VERSION 5.7 ;
BUSBITCHARS "[]" ;
DIVIDERCHAR "/" ;

PROPERTYDEFINITIONS
  MACRO deviceLevel STRING ;
  MACRO CatenaDesignType STRING ;
  MACRO oaTaper STRING ;
END PROPERTYDEFINITIONS

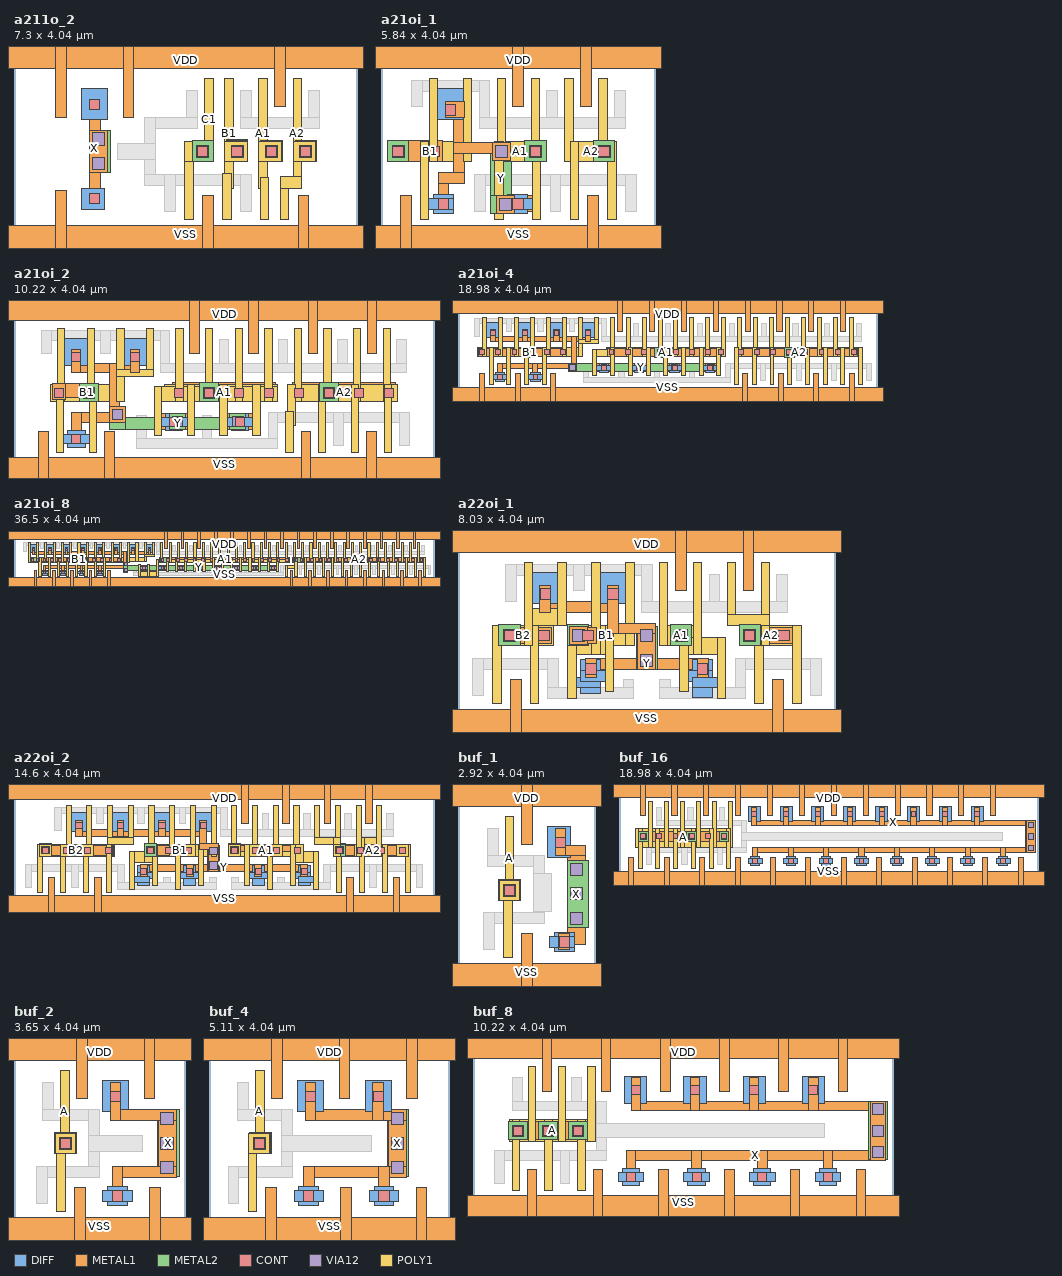
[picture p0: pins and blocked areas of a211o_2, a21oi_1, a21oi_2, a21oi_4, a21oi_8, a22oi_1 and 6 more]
MACRO a211o_2
  CLASS CORE ;
  ORIGIN 0 -0.35 ;
  FOREIGN a211o_2 0 0.35 ;
  SIZE 7.3 BY 4.04 ;
  SYMMETRY X Y ;
  SITE core ;
  PIN X
    DIRECTION INOUT ;
    USE SIGNAL ;
    ANTENNAPARTIALCUTAREA 0.1352 LAYER VIA12 ;
    ANTENNADIFFAREA 0.5676 LAYER METAL2 ;
    ANTENNADIFFAREA 0.5676 LAYER METAL1 ;
    PORT
      LAYER DIFF ;
        RECT 1.445 2.95 1.985 3.61 ;
        RECT 1.445 1.05 1.925 1.49 ;
      LAYER METAL1 ;
        RECT 1.6 1.83 1.98 2.73 ;
        RECT 1.6 1.09 1.83 3.57 ;
      LAYER METAL2 ;
        RECT 1.6 1.83 2.05 2.73 ;
      LAYER CONT ;
        RECT 1.605 3.17 1.825 3.39 ;
        RECT 1.605 1.16 1.825 1.38 ;
      LAYER VIA12 ;
        RECT 1.66 2.41 1.92 2.67 ;
        RECT 1.66 1.89 1.92 2.15 ;
    END
  END X
  PIN VSS
    DIRECTION INOUT ;
    USE GROUND ;
    PORT
      LAYER METAL1 ;
        RECT -0.57 0 7.87 0.7 ;
        RECT 6.04 0 6.27 1.33 ;
        RECT 4.01 0 4.24 1.33 ;
        RECT 0.88 0 1.11 1.45 ;
    END
  END VSS
  PIN A2
    DIRECTION INOUT ;
    USE SIGNAL ;
    ANTENNAPARTIALCUTAREA 0.0676 LAYER VIA12 ;
    ANTENNAMODEL OXIDE1 ;
      ANTENNAGATEAREA 0.1584 LAYER METAL2 ;
      ANTENNAGATEAREA 0.1584 LAYER METAL1 ;
      ANTENNAMAXAREACAR 1.278409 LAYER METAL2 ;
      ANTENNAMAXCUTCAR 0.426768 LAYER VIA12 ;
    PORT
      LAYER POLY1 ;
        RECT 5.935 2.07 6.415 2.49 ;
        RECT 5.935 1.49 6.115 3.83 ;
        RECT 5.665 1.49 6.115 1.74 ;
        RECT 5.665 0.83 5.845 1.74 ;
      LAYER METAL1 ;
        RECT 5.98 2.055 6.43 2.505 ;
      LAYER METAL2 ;
        RECT 5.98 2.055 6.43 2.505 ;
      LAYER CONT ;
        RECT 6.095 2.17 6.315 2.39 ;
      LAYER VIA12 ;
        RECT 6.075 2.15 6.335 2.41 ;
    END
  END A2
  PIN VDD
    DIRECTION INOUT ;
    USE POWER ;
    PORT
      LAYER METAL1 ;
        RECT -0.57 4.04 7.87 4.74 ;
        RECT 5.54 3.23 5.77 4.74 ;
        RECT 2.32 2.99 2.55 4.74 ;
        RECT 0.88 2.99 1.11 4.74 ;
    END
  END VDD
  PIN C1
    DIRECTION INOUT ;
    USE SIGNAL ;
    ANTENNAPARTIALCUTAREA 0.0676 LAYER VIA12 ;
    ANTENNAMODEL OXIDE1 ;
      ANTENNAGATEAREA 0.1584 LAYER METAL2 ;
      ANTENNAGATEAREA 0.1584 LAYER METAL1 ;
      ANTENNAMAXAREACAR 1.278409 LAYER METAL2 ;
      ANTENNAMAXCUTCAR 0.426768 LAYER VIA12 ;
    PORT
      LAYER POLY1 ;
        RECT 4.055 2.07 4.235 3.83 ;
        RECT 3.635 2.07 4.235 2.49 ;
        RECT 3.635 0.83 3.815 2.49 ;
      LAYER METAL1 ;
        RECT 3.79 2.055 4.24 2.505 ;
      LAYER METAL2 ;
        RECT 3.79 2.055 4.24 2.505 ;
      LAYER CONT ;
        RECT 3.905 2.17 4.125 2.39 ;
      LAYER VIA12 ;
        RECT 3.885 2.15 4.145 2.41 ;
    END
  END C1
  PIN B1
    DIRECTION INOUT ;
    USE SIGNAL ;
    ANTENNAPARTIALCUTAREA 0.0676 LAYER VIA12 ;
    ANTENNAMODEL OXIDE1 ;
      ANTENNAGATEAREA 0.1584 LAYER METAL2 ;
      ANTENNAGATEAREA 0.1584 LAYER METAL1 ;
      ANTENNAMAXAREACAR 1.278409 LAYER METAL2 ;
      ANTENNAMAXCUTCAR 0.426768 LAYER VIA12 ;
    PORT
      LAYER POLY1 ;
        RECT 4.485 2.07 4.955 2.49 ;
        RECT 4.485 1.49 4.665 3.83 ;
        RECT 4.435 0.83 4.615 1.815 ;
      LAYER METAL1 ;
        RECT 4.52 2.055 4.97 2.505 ;
      LAYER METAL2 ;
        RECT 4.52 2.055 4.97 2.52 ;
      LAYER CONT ;
        RECT 4.635 2.17 4.855 2.39 ;
      LAYER VIA12 ;
        RECT 4.615 2.15 4.875 2.41 ;
    END
  END B1
  PIN A1
    DIRECTION INOUT ;
    USE SIGNAL ;
    ANTENNAPARTIALCUTAREA 0.0676 LAYER VIA12 ;
    ANTENNAMODEL OXIDE1 ;
      ANTENNAGATEAREA 0.1584 LAYER METAL2 ;
      ANTENNAGATEAREA 0.1584 LAYER METAL1 ;
      ANTENNAMAXAREACAR 1.278409 LAYER METAL2 ;
      ANTENNAMAXCUTCAR 0.426768 LAYER VIA12 ;
    PORT
      LAYER POLY1 ;
        RECT 5.205 2.07 5.685 2.49 ;
        RECT 5.235 0.83 5.415 1.73 ;
        RECT 5.205 1.49 5.385 3.83 ;
      LAYER METAL1 ;
        RECT 5.25 2.055 5.7 2.505 ;
      LAYER METAL2 ;
        RECT 5.25 2.055 5.7 2.505 ;
      LAYER CONT ;
        RECT 5.365 2.17 5.585 2.39 ;
      LAYER VIA12 ;
        RECT 5.345 2.15 5.605 2.41 ;
    END
  END A1
  OBS
    LAYER METAL1 ;
      RECT 6.27 2.77 6.5 3.57 ;
      RECT 4.82 2.77 5.05 3.57 ;
      RECT 4.82 2.77 6.5 3 ;
      RECT 3.67 2.77 3.9 3.57 ;
      RECT 2.78 2.77 3.9 3 ;
      RECT 2.78 1.56 3.01 3 ;
      RECT 2.21 2.11 3.01 2.45 ;
      RECT 2.78 1.56 5.04 1.79 ;
      RECT 4.81 0.99 5.04 1.79 ;
      RECT 3.21 0.99 3.44 1.79 ;
  END
END a211o_2

MACRO a21oi_1
  CLASS CORE ;
  ORIGIN 0 -0.35 ;
  FOREIGN a21oi_1 0 0.35 ;
  SIZE 5.84 BY 4.04 ;
  SYMMETRY X Y ;
  SITE core ;
  PIN Y
    DIRECTION INOUT ;
    USE SIGNAL ;
    ANTENNAPARTIALCUTAREA 0.0676 LAYER VIA12 ;
    ANTENNADIFFAREA 0.7752 LAYER METAL2 ;
    ANTENNADIFFAREA 0.2204 LAYER METAL1 ;
    PORT
      LAYER DIFF ;
        RECT 2.6 1.05 3.22 1.27 ;
        RECT 2.7 0.95 3.12 1.37 ;
        RECT 1.21 2.95 1.75 3.61 ;
        RECT 1.12 0.95 1.54 1.37 ;
        RECT 1.02 1.05 1.54 1.27 ;
      LAYER METAL1 ;
        RECT 2.455 0.99 3.365 1.33 ;
        RECT 2.455 0.95 2.835 1.33 ;
        RECT 1.535 2.24 2.745 2.47 ;
        RECT 2.365 2.09 2.745 2.47 ;
        RECT 1.365 2.99 1.765 3.33 ;
        RECT 1.535 1.595 1.765 3.33 ;
        RECT 1.215 1.595 1.765 1.825 ;
        RECT 1.215 0.99 1.445 1.825 ;
      LAYER METAL2 ;
        RECT 2.33 0.95 2.835 1.33 ;
        RECT 2.33 0.95 2.78 2.47 ;
      LAYER CONT ;
        RECT 1.22 1.05 1.44 1.27 ;
        RECT 1.37 3.05 1.59 3.27 ;
        RECT 2.8 1.05 3.02 1.27 ;
      LAYER VIA12 ;
        RECT 2.425 2.15 2.685 2.41 ;
        RECT 2.515 1.01 2.775 1.27 ;
    END
  END Y
  PIN VSS
    DIRECTION INOUT ;
    USE GROUND ;
    PORT
      LAYER METAL1 ;
        RECT -0.57 0 6.41 0.7 ;
        RECT 4.395 0 4.625 1.33 ;
        RECT 0.415 0 0.645 1.33 ;
    END
  END VSS
  PIN A1
    DIRECTION INOUT ;
    USE SIGNAL ;
    ANTENNAPARTIALCUTAREA 0.0676 LAYER VIA12 ;
    ANTENNAMODEL OXIDE1 ;
      ANTENNAGATEAREA 0.3168 LAYER METAL2 ;
      ANTENNAGATEAREA 0.3168 LAYER METAL1 ;
      ANTENNAMAXAREACAR 0.639205 LAYER METAL2 ;
      ANTENNAMAXCUTCAR 0.213384 LAYER VIA12 ;
    PORT
      LAYER POLY1 ;
        RECT 2.42 2.07 3.495 2.49 ;
        RECT 3.22 0.83 3.4 2.49 ;
        RECT 3.19 2.07 3.37 3.83 ;
        RECT 2.47 2.07 2.65 3.83 ;
        RECT 2.42 0.83 2.6 2.49 ;
      LAYER METAL1 ;
        RECT 3.06 2.055 3.51 2.505 ;
      LAYER METAL2 ;
        RECT 3.06 2.055 3.51 2.505 ;
      LAYER CONT ;
        RECT 3.175 2.17 3.395 2.39 ;
      LAYER VIA12 ;
        RECT 3.155 2.15 3.415 2.41 ;
    END
  END A1
  PIN B1
    DIRECTION INOUT ;
    USE SIGNAL ;
    ANTENNAPARTIALCUTAREA 0.0676 LAYER VIA12 ;
    ANTENNAMODEL OXIDE1 ;
      ANTENNAGATEAREA 0.2772 LAYER METAL2 ;
      ANTENNAGATEAREA 0.2772 LAYER METAL1 ;
      ANTENNAMAXAREACAR 1.852543 LAYER METAL2 ;
      ANTENNAMAXCUTCAR 0.243867 LAYER VIA12 ;
    PORT
      LAYER POLY1 ;
        RECT 1.75 2.07 1.93 3.83 ;
        RECT 0.155 2.07 1.93 2.49 ;
        RECT 1.03 2.07 1.21 3.83 ;
        RECT 0.84 0.83 1.02 2.49 ;
      LAYER METAL1 ;
        RECT 0.14 2.07 1.305 2.505 ;
        RECT 0.14 2.055 0.59 2.505 ;
      LAYER METAL2 ;
        RECT 0.14 2.055 0.59 2.505 ;
      LAYER CONT ;
        RECT 0.255 2.17 0.475 2.39 ;
        RECT 1.025 2.17 1.245 2.39 ;
      LAYER VIA12 ;
        RECT 0.235 2.15 0.495 2.41 ;
    END
  END B1
  PIN VDD
    DIRECTION INOUT ;
    USE POWER ;
    PORT
      LAYER METAL1 ;
        RECT -0.57 4.04 6.41 4.74 ;
        RECT 4.245 3.23 4.475 4.74 ;
        RECT 2.805 3.23 3.035 4.74 ;
    END
  END VDD
  PIN A2
    DIRECTION INOUT ;
    USE SIGNAL ;
    ANTENNAPARTIALCUTAREA 0.0676 LAYER VIA12 ;
    ANTENNAMODEL OXIDE1 ;
      ANTENNAGATEAREA 0.3168 LAYER METAL2 ;
      ANTENNAGATEAREA 0.3168 LAYER METAL1 ;
      ANTENNAMAXAREACAR 0.639205 LAYER METAL2 ;
      ANTENNAMAXCUTCAR 0.213384 LAYER VIA12 ;
    PORT
      LAYER POLY1 ;
        RECT 3.91 2.07 5 2.49 ;
        RECT 4.82 0.83 5 2.49 ;
        RECT 4.63 2.07 4.81 3.83 ;
        RECT 4.02 0.83 4.2 2.49 ;
        RECT 3.91 2.07 4.09 3.83 ;
      LAYER METAL1 ;
        RECT 4.52 2.055 4.97 2.505 ;
      LAYER METAL2 ;
        RECT 4.52 2.055 4.97 2.505 ;
      LAYER CONT ;
        RECT 4.635 2.17 4.855 2.39 ;
      LAYER VIA12 ;
        RECT 4.615 2.15 4.875 2.41 ;
    END
  END A2
  OBS
    LAYER METAL1 ;
      RECT 1.995 1.56 5.425 1.79 ;
      RECT 5.195 0.99 5.425 1.79 ;
      RECT 3.595 0.99 3.825 1.79 ;
      RECT 1.995 0.99 2.225 1.79 ;
      RECT 0.645 3.56 2.315 3.79 ;
      RECT 2.085 2.77 2.315 3.79 ;
      RECT 4.965 2.77 5.195 3.57 ;
      RECT 3.525 2.77 3.755 3.57 ;
      RECT 0.645 3.23 0.875 3.79 ;
      RECT 2.085 2.77 5.195 3 ;
  END
END a21oi_1

MACRO a21oi_2
  CLASS CORE ;
  ORIGIN 0 -0.35 ;
  FOREIGN a21oi_2 0 0.35 ;
  SIZE 10.22 BY 4.04 ;
  SYMMETRY X Y ;
  SITE core ;
  PIN Y
    DIRECTION INOUT ;
    USE SIGNAL ;
    ANTENNAPARTIALCUTAREA 0.0676 LAYER VIA12 ;
    ANTENNADIFFAREA 1.374 LAYER METAL2 ;
    ANTENNADIFFAREA 0.2204 LAYER METAL1 ;
    PORT
      LAYER DIFF ;
        RECT 5.19 1.45 5.81 1.67 ;
        RECT 5.29 1.35 5.71 1.77 ;
        RECT 3.59 1.45 4.21 1.67 ;
        RECT 3.69 1.35 4.11 1.77 ;
        RECT 2.68 2.95 3.22 3.61 ;
        RECT 1.21 1.05 1.83 1.27 ;
        RECT 1.31 0.95 1.73 1.37 ;
        RECT 1.24 2.95 1.78 3.61 ;
      LAYER METAL1 ;
        RECT 5.115 1.39 5.885 1.77 ;
        RECT 3.515 1.39 4.285 1.77 ;
        RECT 2.835 2.77 3.065 3.33 ;
        RECT 1.395 2.77 3.065 3 ;
        RECT 2.33 1.56 2.71 1.94 ;
        RECT 2.33 1.56 2.56 3 ;
        RECT 1.405 1.56 2.71 1.79 ;
        RECT 1.405 0.99 1.635 1.79 ;
        RECT 1.395 2.77 1.625 3.33 ;
      LAYER METAL2 ;
        RECT 5.255 1.39 5.635 1.77 ;
        RECT 2.33 1.39 5.635 1.67 ;
        RECT 3.785 1.39 4.165 1.77 ;
        RECT 2.33 1.39 2.71 1.94 ;
      LAYER CONT ;
        RECT 1.4 3.05 1.62 3.27 ;
        RECT 1.41 1.05 1.63 1.27 ;
        RECT 2.84 3.05 3.06 3.27 ;
        RECT 3.79 1.45 4.01 1.67 ;
        RECT 5.39 1.45 5.61 1.67 ;
      LAYER VIA12 ;
        RECT 2.39 1.62 2.65 1.88 ;
        RECT 3.845 1.45 4.105 1.71 ;
        RECT 5.315 1.45 5.575 1.71 ;
    END
  END Y
  PIN VSS
    DIRECTION INOUT ;
    USE GROUND ;
    PORT
      LAYER METAL1 ;
        RECT -0.57 0 10.79 0.7 ;
        RECT 8.585 0 8.815 1.33 ;
        RECT 6.985 0 7.215 1.33 ;
        RECT 2.205 0 2.435 1.33 ;
        RECT 0.605 0 0.835 1.33 ;
    END
  END VSS
  PIN A1
    DIRECTION INOUT ;
    USE SIGNAL ;
    ANTENNAPARTIALCUTAREA 0.0676 LAYER VIA12 ;
    ANTENNAMODEL OXIDE1 ;
      ANTENNAGATEAREA 0.6336 LAYER METAL2 ;
      ANTENNAGATEAREA 0.6336 LAYER METAL1 ;
      ANTENNAMAXAREACAR 1.856771 LAYER METAL2 ;
      ANTENNAMAXCUTCAR 0.106692 LAYER VIA12 ;
    PORT
      LAYER POLY1 ;
        RECT 3.65 2.07 6.415 2.49 ;
        RECT 6.1 2.07 6.28 3.83 ;
        RECT 5.81 1.23 5.99 2.49 ;
        RECT 5.38 2.07 5.56 3.83 ;
        RECT 5.01 1.23 5.19 2.49 ;
        RECT 4.66 2.07 4.84 3.83 ;
        RECT 4.21 1.23 4.39 2.49 ;
        RECT 3.94 2.07 4.12 3.83 ;
        RECT 3.41 2.07 6.415 2.42 ;
        RECT 3.41 1.23 3.59 2.42 ;
      LAYER METAL1 ;
        RECT 3.845 2.055 6.375 2.52 ;
      LAYER METAL2 ;
        RECT 4.52 2.055 4.97 2.52 ;
      LAYER CONT ;
        RECT 3.905 2.17 4.125 2.39 ;
        RECT 4.635 2.17 4.855 2.39 ;
        RECT 5.365 2.17 5.585 2.39 ;
        RECT 6.095 2.17 6.315 2.39 ;
      LAYER VIA12 ;
        RECT 4.615 2.15 4.875 2.41 ;
    END
  END A1
  PIN B1
    DIRECTION INOUT ;
    USE SIGNAL ;
    ANTENNAPARTIALCUTAREA 0.0676 LAYER VIA12 ;
    ANTENNAMODEL OXIDE1 ;
      ANTENNAGATEAREA 0.5544 LAYER METAL2 ;
      ANTENNAGATEAREA 0.5544 LAYER METAL1 ;
      ANTENNAMAXAREACAR 0.820076 LAYER METAL2 ;
      ANTENNAMAXCUTCAR 0.121934 LAYER VIA12 ;
    PORT
      LAYER POLY1 ;
        RECT 3.22 2.67 3.4 3.83 ;
        RECT 2.5 2.67 3.4 2.85 ;
        RECT 2.5 2.07 2.68 3.83 ;
        RECT 0.885 2.07 2.68 2.49 ;
        RECT 1.83 0.83 2.01 2.49 ;
        RECT 1.78 2.07 1.96 3.83 ;
        RECT 1.06 2.07 1.24 3.83 ;
        RECT 1.03 0.83 1.21 2.49 ;
      LAYER METAL1 ;
        RECT 0.925 2.17 2.05 2.51 ;
        RECT 1.6 2.055 2.05 2.51 ;
        RECT 0.925 2.11 1.265 2.51 ;
      LAYER METAL2 ;
        RECT 1.6 2.055 2.05 2.51 ;
      LAYER CONT ;
        RECT 0.985 2.17 1.205 2.39 ;
        RECT 1.715 2.17 1.935 2.39 ;
      LAYER VIA12 ;
        RECT 1.695 2.15 1.955 2.41 ;
    END
  END B1
  PIN A2
    DIRECTION INOUT ;
    USE SIGNAL ;
    ANTENNAPARTIALCUTAREA 0.0676 LAYER VIA12 ;
    ANTENNAMODEL OXIDE1 ;
      ANTENNAGATEAREA 0.6336 LAYER METAL2 ;
      ANTENNAGATEAREA 0.6336 LAYER METAL1 ;
      ANTENNAMAXAREACAR 1.856771 LAYER METAL2 ;
      ANTENNAMAXCUTCAR 0.106692 LAYER VIA12 ;
    PORT
      LAYER POLY1 ;
        RECT 6.665 2.07 9.335 2.49 ;
        RECT 9.01 0.83 9.19 2.49 ;
        RECT 8.98 2.07 9.16 3.83 ;
        RECT 8.26 2.07 8.44 3.83 ;
        RECT 8.21 0.83 8.39 2.49 ;
        RECT 7.54 2.07 7.72 3.83 ;
        RECT 7.41 0.83 7.59 2.49 ;
        RECT 6.82 2.07 7 3.83 ;
        RECT 6.665 1.49 6.845 2.49 ;
        RECT 6.61 0.83 6.79 1.82 ;
      LAYER METAL1 ;
        RECT 6.765 2.055 9.295 2.52 ;
      LAYER METAL2 ;
        RECT 7.44 2.055 7.89 2.52 ;
      LAYER CONT ;
        RECT 6.825 2.17 7.045 2.39 ;
        RECT 7.555 2.17 7.775 2.39 ;
        RECT 8.285 2.17 8.505 2.39 ;
        RECT 9.015 2.17 9.235 2.39 ;
      LAYER VIA12 ;
        RECT 7.535 2.15 7.795 2.41 ;
    END
  END A2
  PIN VDD
    DIRECTION INOUT ;
    USE POWER ;
    PORT
      LAYER METAL1 ;
        RECT -0.57 4.04 10.79 4.74 ;
        RECT 8.595 3.23 8.825 4.74 ;
        RECT 7.155 3.23 7.385 4.74 ;
        RECT 5.715 3.23 5.945 4.74 ;
        RECT 4.275 3.23 4.505 4.74 ;
    END
  END VDD
  OBS
    LAYER METAL1 ;
      RECT 6.185 1.56 9.615 1.79 ;
      RECT 9.385 0.99 9.615 1.79 ;
      RECT 4.585 0.93 4.815 1.73 ;
      RECT 2.985 0.93 3.215 1.73 ;
      RECT 7.785 0.99 8.015 1.79 ;
      RECT 6.185 0.93 6.415 1.79 ;
      RECT 2.985 0.93 6.415 1.16 ;
      RECT 0.675 3.56 3.785 3.79 ;
      RECT 3.555 2.77 3.785 3.79 ;
      RECT 9.315 2.77 9.545 3.57 ;
      RECT 7.875 2.77 8.105 3.57 ;
      RECT 6.435 2.77 6.665 3.57 ;
      RECT 4.995 2.77 5.225 3.57 ;
      RECT 2.115 3.23 2.345 3.79 ;
      RECT 0.675 3.23 0.905 3.79 ;
      RECT 3.555 2.77 9.545 3 ;
  END
END a21oi_2

MACRO a21oi_4
  CLASS CORE ;
  ORIGIN 0 -0.35 ;
  FOREIGN a21oi_4 0 0.35 ;
  SIZE 18.98 BY 4.04 ;
  SYMMETRY X Y ;
  SITE core ;
  PIN Y
    DIRECTION INOUT ;
    USE SIGNAL ;
    ANTENNAPARTIALCUTAREA 0.0676 LAYER VIA12 ;
    ANTENNADIFFAREA 2.748 LAYER METAL2 ;
    ANTENNADIFFAREA 0.2204 LAYER METAL1 ;
    PORT
      LAYER DIFF ;
        RECT 11.08 1.45 11.7 1.67 ;
        RECT 11.18 1.35 11.6 1.77 ;
        RECT 9.48 1.45 10.1 1.67 ;
        RECT 9.58 1.35 10 1.77 ;
        RECT 7.88 1.45 8.5 1.67 ;
        RECT 7.98 1.35 8.4 1.77 ;
        RECT 6.28 1.45 6.9 1.67 ;
        RECT 6.38 1.35 6.8 1.77 ;
        RECT 5.62 2.95 6.16 3.61 ;
        RECT 4.18 2.95 4.72 3.61 ;
        RECT 3.19 1.05 3.81 1.27 ;
        RECT 3.29 0.95 3.71 1.37 ;
        RECT 2.74 2.95 3.28 3.61 ;
        RECT 1.59 1.05 2.21 1.27 ;
        RECT 1.69 0.95 2.11 1.37 ;
        RECT 1.3 2.95 1.84 3.61 ;
      LAYER METAL1 ;
        RECT 11.08 1.39 11.7 1.77 ;
        RECT 9.48 1.39 10.1 1.77 ;
        RECT 7.88 1.39 8.5 1.77 ;
        RECT 6.28 1.39 6.9 1.77 ;
        RECT 5.775 2.77 6.005 3.33 ;
        RECT 1.455 2.77 6.005 3 ;
        RECT 5.145 1.39 5.375 3 ;
        RECT 1.785 1.56 5.375 1.79 ;
        RECT 4.995 1.39 5.375 1.79 ;
        RECT 4.335 2.77 4.565 3.33 ;
        RECT 3.385 0.99 3.615 1.79 ;
        RECT 2.895 2.77 3.125 3.33 ;
        RECT 1.785 0.99 2.015 1.79 ;
        RECT 1.455 2.77 1.685 3.33 ;
      LAYER METAL2 ;
        RECT 4.995 1.39 11.585 1.77 ;
      LAYER CONT ;
        RECT 1.46 3.05 1.68 3.27 ;
        RECT 1.79 1.05 2.01 1.27 ;
        RECT 2.9 3.05 3.12 3.27 ;
        RECT 3.39 1.05 3.61 1.27 ;
        RECT 4.34 3.05 4.56 3.27 ;
        RECT 5.78 3.05 6 3.27 ;
        RECT 6.48 1.45 6.7 1.67 ;
        RECT 8.08 1.45 8.3 1.67 ;
        RECT 9.68 1.45 9.9 1.67 ;
        RECT 11.28 1.45 11.5 1.67 ;
      LAYER VIA12 ;
        RECT 5.055 1.45 5.315 1.71 ;
        RECT 6.465 1.45 6.725 1.71 ;
        RECT 8.065 1.45 8.325 1.71 ;
        RECT 9.665 1.45 9.925 1.71 ;
        RECT 11.265 1.45 11.525 1.71 ;
    END
  END Y
  PIN VSS
    DIRECTION INOUT ;
    USE GROUND ;
    PORT
      LAYER METAL1 ;
        RECT -0.57 0 19.55 0.7 ;
        RECT 17.675 0 17.905 1.33 ;
        RECT 16.075 0 16.305 1.33 ;
        RECT 14.475 0 14.705 1.33 ;
        RECT 12.875 0 13.105 1.33 ;
        RECT 4.185 0 4.415 1.33 ;
        RECT 2.585 0 2.815 1.33 ;
        RECT 0.985 0 1.215 1.33 ;
    END
  END VSS
  PIN A2
    DIRECTION INOUT ;
    USE SIGNAL ;
    ANTENNAPARTIALCUTAREA 0.0676 LAYER VIA12 ;
    ANTENNAMODEL OXIDE1 ;
      ANTENNAGATEAREA 1.2672 LAYER METAL2 ;
      ANTENNAGATEAREA 1.2672 LAYER METAL1 ;
      ANTENNAMAXAREACAR 1.501342 LAYER METAL2 ;
      ANTENNAMAXCUTCAR 0.053346 LAYER VIA12 ;
    PORT
      LAYER POLY1 ;
        RECT 12.5 2.07 18.28 2.49 ;
        RECT 18.1 0.83 18.28 2.49 ;
        RECT 17.68 2.07 17.86 3.83 ;
        RECT 17.3 0.83 17.48 2.49 ;
        RECT 16.96 2.07 17.14 3.83 ;
        RECT 16.5 0.83 16.68 2.49 ;
        RECT 16.24 2.07 16.42 3.83 ;
        RECT 15.7 0.83 15.88 2.49 ;
        RECT 15.52 2.07 15.7 3.83 ;
        RECT 14.9 0.83 15.08 2.49 ;
        RECT 14.8 2.07 14.98 3.83 ;
        RECT 14.1 0.83 14.28 2.49 ;
        RECT 14.08 2.07 14.26 3.83 ;
        RECT 13.36 2.07 13.54 3.83 ;
        RECT 13.3 0.83 13.48 2.49 ;
        RECT 12.64 2.07 12.82 3.83 ;
        RECT 12.5 0.83 12.68 2.49 ;
      LAYER METAL1 ;
        RECT 12.605 2.11 18.055 2.45 ;
        RECT 14.74 2.055 15.19 2.505 ;
      LAYER METAL2 ;
        RECT 14.74 2.055 15.19 2.505 ;
      LAYER CONT ;
        RECT 12.665 2.17 12.885 2.39 ;
        RECT 13.395 2.17 13.615 2.39 ;
        RECT 14.125 2.17 14.345 2.39 ;
        RECT 14.855 2.17 15.075 2.39 ;
        RECT 15.585 2.17 15.805 2.39 ;
        RECT 16.315 2.17 16.535 2.39 ;
        RECT 17.045 2.17 17.265 2.39 ;
        RECT 17.775 2.17 17.995 2.39 ;
      LAYER VIA12 ;
        RECT 14.835 2.15 15.095 2.41 ;
    END
  END A2
  PIN A1
    DIRECTION INOUT ;
    USE SIGNAL ;
    ANTENNAPARTIALCUTAREA 0.0676 LAYER VIA12 ;
    ANTENNAMODEL OXIDE1 ;
      ANTENNAGATEAREA 1.2672 LAYER METAL2 ;
      ANTENNAGATEAREA 1.2672 LAYER METAL1 ;
      ANTENNAMAXAREACAR 1.459754 LAYER METAL2 ;
      ANTENNAMAXCUTCAR 0.053346 LAYER VIA12 ;
    PORT
      LAYER POLY1 ;
        RECT 11.92 2.07 12.1 3.83 ;
        RECT 6.725 2.07 12.1 2.49 ;
        RECT 11.7 1.23 11.88 2.49 ;
        RECT 11.2 2.07 11.38 3.83 ;
        RECT 10.9 1.23 11.08 2.49 ;
        RECT 10.48 2.07 10.66 3.83 ;
        RECT 10.1 1.23 10.28 2.49 ;
        RECT 9.76 2.07 9.94 3.83 ;
        RECT 9.3 1.23 9.48 2.49 ;
        RECT 9.04 2.07 9.22 3.83 ;
        RECT 8.5 1.23 8.68 2.49 ;
        RECT 8.32 2.07 8.5 3.83 ;
        RECT 7.7 1.23 7.88 2.49 ;
        RECT 7.6 2.07 7.78 3.83 ;
        RECT 6.9 1.23 7.08 2.49 ;
        RECT 6.88 2.07 7.06 3.83 ;
        RECT 6.1 2.07 12.1 2.42 ;
        RECT 6.1 1.23 6.28 2.42 ;
      LAYER METAL1 ;
        RECT 6.765 2.11 12.06 2.45 ;
        RECT 8.9 2.055 9.35 2.505 ;
      LAYER METAL2 ;
        RECT 8.9 2.055 9.35 2.505 ;
      LAYER CONT ;
        RECT 6.825 2.17 7.045 2.39 ;
        RECT 7.555 2.17 7.775 2.39 ;
        RECT 8.285 2.17 8.505 2.39 ;
        RECT 9.015 2.17 9.235 2.39 ;
        RECT 9.745 2.17 9.965 2.39 ;
        RECT 10.475 2.17 10.695 2.39 ;
        RECT 11.205 2.17 11.425 2.39 ;
        RECT 11.78 2.17 12 2.39 ;
      LAYER VIA12 ;
        RECT 8.995 2.15 9.255 2.41 ;
    END
  END A1
  PIN B1
    DIRECTION INOUT ;
    USE SIGNAL ;
    ANTENNAPARTIALCUTAREA 0.0676 LAYER VIA12 ;
    ANTENNAMODEL OXIDE1 ;
      ANTENNAGATEAREA 1.1088 LAYER METAL2 ;
      ANTENNAGATEAREA 1.1088 LAYER METAL1 ;
      ANTENNAMAXAREACAR 1.268128 LAYER METAL2 ;
      ANTENNAMAXCUTCAR 0.060967 LAYER VIA12 ;
    PORT
      LAYER POLY1 ;
        RECT 6.16 2.67 6.34 3.83 ;
        RECT 5.44 2.67 6.34 2.85 ;
        RECT 5.44 2.07 5.62 3.83 ;
        RECT 0.885 2.07 5.62 2.49 ;
        RECT 4.72 2.07 4.9 3.83 ;
        RECT 4 2.07 4.18 3.83 ;
        RECT 3.81 0.83 3.99 2.49 ;
        RECT 3.28 2.07 3.46 3.83 ;
        RECT 3.01 0.83 3.19 2.49 ;
        RECT 2.56 2.07 2.74 3.83 ;
        RECT 2.21 0.83 2.39 2.49 ;
        RECT 1.84 2.07 2.02 3.83 ;
        RECT 1.41 0.83 1.59 2.49 ;
        RECT 1.12 2.07 1.3 3.83 ;
      LAYER METAL1 ;
        RECT 0.925 2.11 4.915 2.45 ;
        RECT 3.06 2.055 3.51 2.505 ;
      LAYER METAL2 ;
        RECT 3.06 2.055 3.51 2.505 ;
      LAYER CONT ;
        RECT 0.985 2.17 1.205 2.39 ;
        RECT 1.715 2.17 1.935 2.39 ;
        RECT 2.445 2.17 2.665 2.39 ;
        RECT 3.175 2.17 3.395 2.39 ;
        RECT 3.905 2.17 4.125 2.39 ;
        RECT 4.635 2.17 4.855 2.39 ;
      LAYER VIA12 ;
        RECT 3.155 2.15 3.415 2.41 ;
    END
  END B1
  PIN VDD
    DIRECTION INOUT ;
    USE POWER ;
    PORT
      LAYER METAL1 ;
        RECT -0.57 4.04 19.55 4.74 ;
        RECT 17.295 3.23 17.525 4.74 ;
        RECT 15.855 3.23 16.085 4.74 ;
        RECT 14.415 3.23 14.645 4.74 ;
        RECT 12.975 3.23 13.205 4.74 ;
        RECT 11.535 3.23 11.765 4.74 ;
        RECT 10.095 3.23 10.325 4.74 ;
        RECT 8.655 3.23 8.885 4.74 ;
        RECT 7.215 3.23 7.445 4.74 ;
    END
  END VDD
  OBS
    LAYER METAL1 ;
      RECT 12.075 1.56 18.705 1.79 ;
      RECT 18.475 0.99 18.705 1.79 ;
      RECT 10.475 0.93 10.705 1.73 ;
      RECT 8.875 0.93 9.105 1.73 ;
      RECT 7.275 0.93 7.505 1.73 ;
      RECT 5.675 0.93 5.905 1.73 ;
      RECT 16.875 0.99 17.105 1.79 ;
      RECT 15.275 0.99 15.505 1.79 ;
      RECT 13.675 0.99 13.905 1.79 ;
      RECT 12.075 0.93 12.305 1.79 ;
      RECT 5.675 0.93 12.305 1.16 ;
      RECT 0.735 3.56 6.725 3.79 ;
      RECT 6.495 2.77 6.725 3.79 ;
      RECT 18.015 2.77 18.245 3.57 ;
      RECT 16.575 2.77 16.805 3.57 ;
      RECT 15.135 2.77 15.365 3.57 ;
      RECT 13.695 2.77 13.925 3.57 ;
      RECT 12.255 2.77 12.485 3.57 ;
      RECT 10.815 2.77 11.045 3.57 ;
      RECT 9.375 2.77 9.605 3.57 ;
      RECT 7.935 2.77 8.165 3.57 ;
      RECT 5.055 3.23 5.285 3.79 ;
      RECT 3.615 3.23 3.845 3.79 ;
      RECT 2.175 3.23 2.405 3.79 ;
      RECT 0.735 2.99 0.965 3.79 ;
      RECT 6.495 2.77 18.245 3 ;
  END
END a21oi_4

MACRO a21oi_8
  CLASS CORE ;
  ORIGIN 0 -0.35 ;
  FOREIGN a21oi_8 0 0.35 ;
  SIZE 36.5 BY 4.04 ;
  SYMMETRY X Y ;
  SITE core ;
  PIN Y
    DIRECTION INOUT ;
    USE SIGNAL ;
    ANTENNAPARTIALCUTAREA 0.1352 LAYER VIA12 ;
    ANTENNADIFFAREA 5.496 LAYER METAL2 ;
    ANTENNADIFFAREA 0.2204 LAYER METAL1 ;
    PORT
      LAYER DIFF ;
        RECT 22.2 1.45 22.82 1.67 ;
        RECT 22.3 1.35 22.72 1.77 ;
        RECT 20.6 1.45 21.22 1.67 ;
        RECT 20.7 1.35 21.12 1.77 ;
        RECT 19 1.45 19.62 1.67 ;
        RECT 19.1 1.35 19.52 1.77 ;
        RECT 17.4 1.45 18.02 1.67 ;
        RECT 17.5 1.35 17.92 1.77 ;
        RECT 15.8 1.45 16.42 1.67 ;
        RECT 15.9 1.35 16.32 1.77 ;
        RECT 14.2 1.45 14.82 1.67 ;
        RECT 14.3 1.35 14.72 1.77 ;
        RECT 12.6 1.45 13.22 1.67 ;
        RECT 12.7 1.35 13.12 1.77 ;
        RECT 11.5 2.945 12.04 3.605 ;
        RECT 11 1.45 11.62 1.67 ;
        RECT 11.1 1.35 11.52 1.77 ;
        RECT 10.06 2.945 10.6 3.605 ;
        RECT 8.62 2.945 9.16 3.605 ;
        RECT 7.15 1.05 7.77 1.27 ;
        RECT 7.25 0.95 7.67 1.37 ;
        RECT 7.18 2.945 7.72 3.605 ;
        RECT 5.74 2.945 6.28 3.605 ;
        RECT 5.55 1.05 6.17 1.27 ;
        RECT 5.65 0.95 6.07 1.37 ;
        RECT 4.3 2.945 4.84 3.605 ;
        RECT 3.95 1.05 4.57 1.27 ;
        RECT 4.05 0.95 4.47 1.37 ;
        RECT 2.86 2.945 3.4 3.605 ;
        RECT 2.35 1.05 2.97 1.27 ;
        RECT 2.45 0.95 2.87 1.37 ;
        RECT 1.42 2.945 1.96 3.605 ;
      LAYER METAL1 ;
        RECT 22.2 1.39 22.82 1.77 ;
        RECT 20.6 1.39 21.22 1.77 ;
        RECT 19 1.39 19.62 1.77 ;
        RECT 17.4 1.39 18.02 1.77 ;
        RECT 15.8 1.39 16.42 1.77 ;
        RECT 14.2 1.39 14.82 1.77 ;
        RECT 12.6 1.39 13.22 1.77 ;
        RECT 11.655 2.765 11.885 3.325 ;
        RECT 1.575 2.765 11.885 2.995 ;
        RECT 10.215 2.765 10.445 3.325 ;
        RECT 9.525 1.17 9.905 2.07 ;
        RECT 9.525 1.17 9.755 2.995 ;
        RECT 2.545 1.56 9.905 1.79 ;
        RECT 8.775 2.765 9.005 3.325 ;
        RECT 7.345 0.99 7.575 1.79 ;
        RECT 7.335 2.765 7.565 3.325 ;
        RECT 5.895 2.765 6.125 3.325 ;
        RECT 5.745 0.99 5.975 1.79 ;
        RECT 4.455 2.765 4.685 3.325 ;
        RECT 4.145 0.99 4.375 1.79 ;
        RECT 3.015 2.765 3.245 3.325 ;
        RECT 2.545 0.99 2.775 1.79 ;
        RECT 1.575 2.765 1.805 3.325 ;
        RECT 11 1.39 11.62 1.77 ;
      LAYER METAL2 ;
        RECT 9.525 1.39 22.7 1.77 ;
        RECT 9.525 1.17 9.905 2.07 ;
      LAYER CONT ;
        RECT 1.58 3.045 1.8 3.265 ;
        RECT 2.55 1.05 2.77 1.27 ;
        RECT 3.02 3.045 3.24 3.265 ;
        RECT 4.15 1.05 4.37 1.27 ;
        RECT 4.46 3.045 4.68 3.265 ;
        RECT 5.75 1.05 5.97 1.27 ;
        RECT 5.9 3.045 6.12 3.265 ;
        RECT 7.34 3.045 7.56 3.265 ;
        RECT 7.35 1.05 7.57 1.27 ;
        RECT 8.78 3.045 9 3.265 ;
        RECT 10.22 3.045 10.44 3.265 ;
        RECT 11.2 1.45 11.42 1.67 ;
        RECT 11.66 3.045 11.88 3.265 ;
        RECT 12.8 1.45 13.02 1.67 ;
        RECT 14.4 1.45 14.62 1.67 ;
        RECT 16 1.45 16.22 1.67 ;
        RECT 17.6 1.45 17.82 1.67 ;
        RECT 19.2 1.45 19.42 1.67 ;
        RECT 20.8 1.45 21.02 1.67 ;
        RECT 22.4 1.45 22.62 1.67 ;
      LAYER VIA12 ;
        RECT 9.585 1.75 9.845 2.01 ;
        RECT 9.585 1.23 9.845 1.49 ;
        RECT 11.18 1.45 11.44 1.71 ;
        RECT 12.78 1.45 13.04 1.71 ;
        RECT 14.38 1.45 14.64 1.71 ;
        RECT 15.98 1.45 16.24 1.71 ;
        RECT 17.58 1.45 17.84 1.71 ;
        RECT 19.18 1.45 19.44 1.71 ;
        RECT 20.78 1.45 21.04 1.71 ;
        RECT 22.38 1.45 22.64 1.71 ;
    END
  END Y
  PIN VSS
    DIRECTION INOUT ;
    USE GROUND ;
    PORT
      LAYER METAL1 ;
        RECT -0.57 0 37.07 0.7 ;
        RECT 35.195 0 35.425 1.33 ;
        RECT 33.595 0 33.825 1.33 ;
        RECT 31.995 0 32.225 1.33 ;
        RECT 30.395 0 30.625 1.33 ;
        RECT 28.795 0 29.025 1.33 ;
        RECT 27.195 0 27.425 1.33 ;
        RECT 25.595 0 25.825 1.33 ;
        RECT 23.995 0 24.225 1.33 ;
        RECT 8.145 0 8.375 1.33 ;
        RECT 6.545 0 6.775 1.33 ;
        RECT 4.945 0 5.175 1.33 ;
        RECT 3.345 0 3.575 1.33 ;
        RECT 1.745 0 1.975 1.33 ;
    END
  END VSS
  PIN A2
    DIRECTION INOUT ;
    USE SIGNAL ;
    ANTENNAPARTIALCUTAREA 0.1352 LAYER VIA12 ;
    ANTENNAMODEL OXIDE1 ;
      ANTENNAGATEAREA 2.5344 LAYER METAL2 ;
      ANTENNAGATEAREA 2.5344 LAYER METAL1 ;
      ANTENNAMAXAREACAR 1.5567 LAYER METAL2 ;
      ANTENNAMAXCUTCAR 0.053346 LAYER VIA12 ;
    PORT
      LAYER POLY1 ;
        RECT 24.245 2.07 35.8 2.49 ;
        RECT 35.62 0.83 35.8 2.49 ;
        RECT 35.08 2.07 35.26 3.825 ;
        RECT 34.82 0.83 35 2.49 ;
        RECT 34.36 2.07 34.54 3.825 ;
        RECT 34.02 0.83 34.2 2.49 ;
        RECT 33.64 2.07 33.82 3.825 ;
        RECT 33.22 0.83 33.4 2.49 ;
        RECT 32.92 2.07 33.1 3.825 ;
        RECT 32.42 0.83 32.6 2.49 ;
        RECT 32.2 2.07 32.38 3.825 ;
        RECT 31.62 0.83 31.8 2.49 ;
        RECT 31.48 2.07 31.66 3.825 ;
        RECT 30.82 0.83 31 2.49 ;
        RECT 30.76 2.07 30.94 3.825 ;
        RECT 30.04 2.07 30.22 3.825 ;
        RECT 30.02 0.83 30.2 2.49 ;
        RECT 29.32 2.07 29.5 3.825 ;
        RECT 29.22 0.83 29.4 2.49 ;
        RECT 28.6 2.07 28.78 3.825 ;
        RECT 28.42 0.83 28.6 2.49 ;
        RECT 27.88 2.07 28.06 3.825 ;
        RECT 27.62 0.83 27.8 2.49 ;
        RECT 27.16 2.07 27.34 3.825 ;
        RECT 26.82 0.83 27 2.49 ;
        RECT 26.44 2.07 26.62 3.825 ;
        RECT 26.02 0.83 26.2 2.49 ;
        RECT 25.72 2.07 25.9 3.825 ;
        RECT 25.22 0.83 25.4 2.49 ;
        RECT 25 2.07 25.18 3.825 ;
        RECT 24.42 0.83 24.6 2.49 ;
        RECT 24.28 2.07 24.46 3.825 ;
        RECT 23.62 1.49 24.6 1.815 ;
        RECT 23.62 0.83 23.8 1.815 ;
      LAYER METAL1 ;
        RECT 24.285 2.11 35.575 2.45 ;
        RECT 24.285 2.055 25.255 2.505 ;
      LAYER METAL2 ;
        RECT 24.285 2.055 25.255 2.505 ;
      LAYER CONT ;
        RECT 24.425 2.17 24.645 2.39 ;
        RECT 24.895 2.17 25.115 2.39 ;
        RECT 25.805 2.17 26.025 2.39 ;
        RECT 26.535 2.17 26.755 2.39 ;
        RECT 27.265 2.17 27.485 2.39 ;
        RECT 27.995 2.17 28.215 2.39 ;
        RECT 28.725 2.17 28.945 2.39 ;
        RECT 29.455 2.17 29.675 2.39 ;
        RECT 30.185 2.17 30.405 2.39 ;
        RECT 30.915 2.17 31.135 2.39 ;
        RECT 31.645 2.17 31.865 2.39 ;
        RECT 32.375 2.17 32.595 2.39 ;
        RECT 33.105 2.17 33.325 2.39 ;
        RECT 33.835 2.17 34.055 2.39 ;
        RECT 34.565 2.17 34.785 2.39 ;
        RECT 35.295 2.17 35.515 2.39 ;
      LAYER VIA12 ;
        RECT 24.38 2.15 24.64 2.41 ;
        RECT 24.9 2.15 25.16 2.41 ;
    END
  END A2
  PIN A1
    DIRECTION INOUT ;
    USE SIGNAL ;
    ANTENNAPARTIALCUTAREA 0.1352 LAYER VIA12 ;
    ANTENNAMODEL OXIDE1 ;
      ANTENNAGATEAREA 2.5344 LAYER METAL2 ;
      ANTENNAGATEAREA 2.5344 LAYER METAL1 ;
      ANTENNAMAXAREACAR 1.549992 LAYER METAL2 ;
      ANTENNAMAXCUTCAR 0.053346 LAYER VIA12 ;
    PORT
      LAYER POLY1 ;
        RECT 12.69 2.07 23.935 2.49 ;
        RECT 23.56 2.07 23.74 3.825 ;
        RECT 22.84 2.07 23.02 3.825 ;
        RECT 22.82 1.23 23 2.49 ;
        RECT 22.12 2.07 22.3 3.825 ;
        RECT 22.02 1.23 22.2 2.49 ;
        RECT 21.4 2.07 21.58 3.825 ;
        RECT 21.22 1.23 21.4 2.49 ;
        RECT 20.68 2.07 20.86 3.825 ;
        RECT 20.42 1.23 20.6 2.49 ;
        RECT 19.96 2.07 20.14 3.825 ;
        RECT 19.62 1.23 19.8 2.49 ;
        RECT 19.24 2.07 19.42 3.825 ;
        RECT 18.82 1.23 19 2.49 ;
        RECT 18.52 2.07 18.7 3.825 ;
        RECT 18.02 1.23 18.2 2.49 ;
        RECT 17.8 2.07 17.98 3.825 ;
        RECT 17.22 1.23 17.4 2.49 ;
        RECT 17.08 2.07 17.26 3.825 ;
        RECT 16.42 1.23 16.6 2.49 ;
        RECT 16.36 2.07 16.54 3.825 ;
        RECT 15.64 2.07 15.82 3.825 ;
        RECT 15.62 1.23 15.8 2.49 ;
        RECT 14.92 2.07 15.1 3.825 ;
        RECT 14.82 1.23 15 2.49 ;
        RECT 14.2 2.07 14.38 3.825 ;
        RECT 14.02 1.23 14.2 2.49 ;
        RECT 13.48 2.07 13.66 3.825 ;
        RECT 13.22 1.23 13.4 2.49 ;
        RECT 12.76 2.07 12.94 3.825 ;
        RECT 12.42 2.07 23.935 2.295 ;
        RECT 12.42 0.805 12.6 2.295 ;
        RECT 10.82 0.805 12.6 1.23 ;
        RECT 11.62 0.805 11.8 1.89 ;
        RECT 10.82 0.805 11 1.89 ;
      LAYER METAL1 ;
        RECT 12.655 2.11 23.895 2.45 ;
        RECT 12.655 2.055 13.625 2.505 ;
      LAYER METAL2 ;
        RECT 12.655 2.055 13.625 2.505 ;
      LAYER CONT ;
        RECT 12.795 2.17 13.015 2.39 ;
        RECT 13.265 2.17 13.485 2.39 ;
        RECT 14.125 2.17 14.345 2.39 ;
        RECT 14.855 2.17 15.075 2.39 ;
        RECT 15.585 2.17 15.805 2.39 ;
        RECT 16.315 2.17 16.535 2.39 ;
        RECT 17.045 2.17 17.265 2.39 ;
        RECT 17.775 2.17 17.995 2.39 ;
        RECT 18.505 2.17 18.725 2.39 ;
        RECT 19.235 2.17 19.455 2.39 ;
        RECT 19.965 2.17 20.185 2.39 ;
        RECT 20.695 2.17 20.915 2.39 ;
        RECT 21.425 2.17 21.645 2.39 ;
        RECT 22.155 2.17 22.375 2.39 ;
        RECT 22.885 2.17 23.105 2.39 ;
        RECT 23.615 2.17 23.835 2.39 ;
      LAYER VIA12 ;
        RECT 12.75 2.15 13.01 2.41 ;
        RECT 13.27 2.15 13.53 2.41 ;
    END
  END A1
  PIN B1
    DIRECTION INOUT ;
    USE SIGNAL ;
    ANTENNAPARTIALCUTAREA 0.1352 LAYER VIA12 ;
    ANTENNAMODEL OXIDE1 ;
      ANTENNAGATEAREA 2.2176 LAYER METAL2 ;
      ANTENNAGATEAREA 2.2176 LAYER METAL1 ;
      ANTENNAMAXAREACAR 1.230519 LAYER METAL2 ;
      ANTENNAMAXCUTCAR 0.060967 LAYER VIA12 ;
    PORT
      LAYER POLY1 ;
        RECT 12.04 2.545 12.22 3.825 ;
        RECT 11.32 2.545 12.22 2.725 ;
        RECT 11.32 2.14 11.5 3.825 ;
        RECT 1.24 2.14 11.5 2.49 ;
        RECT 10.6 2.14 10.78 3.825 ;
        RECT 1.24 2.07 10.065 2.49 ;
        RECT 9.88 2.07 10.06 3.825 ;
        RECT 9.16 2.07 9.34 3.825 ;
        RECT 8.44 2.07 8.62 3.825 ;
        RECT 7.77 0.83 7.95 2.49 ;
        RECT 7.72 2.07 7.9 3.825 ;
        RECT 7 2.07 7.18 3.825 ;
        RECT 6.97 0.83 7.15 2.49 ;
        RECT 6.28 2.07 6.46 3.825 ;
        RECT 6.17 0.83 6.35 2.49 ;
        RECT 5.56 2.07 5.74 3.825 ;
        RECT 5.37 0.83 5.55 2.49 ;
        RECT 4.84 2.07 5.02 3.825 ;
        RECT 4.57 0.83 4.75 2.49 ;
        RECT 4.12 2.07 4.3 3.825 ;
        RECT 3.77 0.83 3.95 2.49 ;
        RECT 3.4 2.07 3.58 3.825 ;
        RECT 2.97 0.83 3.15 2.49 ;
        RECT 2.68 2.07 2.86 3.825 ;
        RECT 2.17 0.83 2.35 2.49 ;
        RECT 1.96 2.07 2.14 3.825 ;
        RECT 1.24 2.07 1.42 3.825 ;
      LAYER METAL1 ;
        RECT 1.375 2.11 9.295 2.45 ;
        RECT 1.375 2.09 2.275 2.47 ;
      LAYER METAL2 ;
        RECT 1.375 2.09 2.275 2.47 ;
      LAYER CONT ;
        RECT 1.48 2.17 1.7 2.39 ;
        RECT 1.95 2.17 2.17 2.39 ;
        RECT 2.555 2.17 2.775 2.39 ;
        RECT 3.175 2.17 3.395 2.39 ;
        RECT 3.905 2.17 4.125 2.39 ;
        RECT 4.635 2.17 4.855 2.39 ;
        RECT 5.365 2.17 5.585 2.39 ;
        RECT 6.095 2.17 6.315 2.39 ;
        RECT 6.825 2.17 7.045 2.39 ;
        RECT 7.555 2.17 7.775 2.39 ;
        RECT 8.285 2.17 8.505 2.39 ;
        RECT 9.015 2.17 9.235 2.39 ;
      LAYER VIA12 ;
        RECT 1.435 2.15 1.695 2.41 ;
        RECT 1.955 2.15 2.215 2.41 ;
    END
  END B1
  PIN VDD
    DIRECTION INOUT ;
    USE POWER ;
    PORT
      LAYER METAL1 ;
        RECT -0.57 4.04 37.07 4.74 ;
        RECT 34.695 3.225 34.925 4.74 ;
        RECT 33.255 3.225 33.485 4.74 ;
        RECT 31.815 3.225 32.045 4.74 ;
        RECT 30.375 3.225 30.605 4.74 ;
        RECT 28.935 3.225 29.165 4.74 ;
        RECT 27.495 3.225 27.725 4.74 ;
        RECT 26.055 3.225 26.285 4.74 ;
        RECT 24.615 3.225 24.845 4.74 ;
        RECT 23.175 3.225 23.405 4.74 ;
        RECT 21.735 3.225 21.965 4.74 ;
        RECT 20.295 3.225 20.525 4.74 ;
        RECT 18.855 3.225 19.085 4.74 ;
        RECT 17.415 3.225 17.645 4.74 ;
        RECT 15.975 3.225 16.205 4.74 ;
        RECT 14.535 3.225 14.765 4.74 ;
        RECT 13.095 3.225 13.325 4.74 ;
    END
  END VDD
  OBS
    LAYER METAL1 ;
      RECT 23.195 1.56 36.225 1.79 ;
      RECT 35.995 0.99 36.225 1.79 ;
      RECT 21.595 0.93 21.825 1.73 ;
      RECT 19.995 0.93 20.225 1.73 ;
      RECT 18.395 0.93 18.625 1.73 ;
      RECT 16.795 0.93 17.025 1.73 ;
      RECT 15.195 0.93 15.425 1.73 ;
      RECT 13.595 0.93 13.825 1.73 ;
      RECT 11.995 0.93 12.225 1.73 ;
      RECT 10.395 0.93 10.625 1.73 ;
      RECT 34.395 0.99 34.625 1.79 ;
      RECT 32.795 0.99 33.025 1.79 ;
      RECT 31.195 0.99 31.425 1.79 ;
      RECT 29.595 0.99 29.825 1.79 ;
      RECT 27.995 0.99 28.225 1.79 ;
      RECT 26.395 0.99 26.625 1.79 ;
      RECT 24.795 0.99 25.025 1.79 ;
      RECT 23.195 0.93 23.425 1.79 ;
      RECT 10.395 0.93 23.425 1.16 ;
      RECT 0.855 3.555 12.605 3.785 ;
      RECT 12.375 2.765 12.605 3.785 ;
      RECT 35.415 2.765 35.645 3.565 ;
      RECT 33.975 2.765 34.205 3.565 ;
      RECT 32.535 2.765 32.765 3.565 ;
      RECT 31.095 2.765 31.325 3.565 ;
      RECT 29.655 2.765 29.885 3.565 ;
      RECT 28.215 2.765 28.445 3.565 ;
      RECT 26.775 2.765 27.005 3.565 ;
      RECT 25.335 2.765 25.565 3.565 ;
      RECT 23.895 2.765 24.125 3.565 ;
      RECT 22.455 2.765 22.685 3.565 ;
      RECT 21.015 2.765 21.245 3.565 ;
      RECT 19.575 2.765 19.805 3.565 ;
      RECT 18.135 2.765 18.365 3.565 ;
      RECT 16.695 2.765 16.925 3.565 ;
      RECT 15.255 2.765 15.485 3.565 ;
      RECT 13.815 2.765 14.045 3.565 ;
      RECT 10.935 3.225 11.165 3.785 ;
      RECT 9.495 3.225 9.725 3.785 ;
      RECT 8.055 3.225 8.285 3.785 ;
      RECT 6.615 3.225 6.845 3.785 ;
      RECT 5.175 3.225 5.405 3.785 ;
      RECT 3.735 3.225 3.965 3.785 ;
      RECT 2.295 3.225 2.525 3.785 ;
      RECT 0.855 2.985 1.085 3.785 ;
      RECT 12.375 2.765 35.645 2.995 ;
  END
END a21oi_8

MACRO a22oi_1
  CLASS CORE ;
  ORIGIN 0 -0.35 ;
  FOREIGN a22oi_1 0 0.35 ;
  SIZE 8.03 BY 4.04 ;
  SYMMETRY X Y ;
  SITE core ;
  PIN B2
    DIRECTION INOUT ;
    USE SIGNAL ;
    ANTENNAPARTIALCUTAREA 0.0676 LAYER VIA12 ;
    ANTENNAMODEL OXIDE1 ;
      ANTENNAGATEAREA 0.3168 LAYER METAL2 ;
      ANTENNAGATEAREA 0.3168 LAYER METAL1 ;
      ANTENNAMAXAREACAR 1.363636 LAYER METAL2 ;
      ANTENNAMAXCUTCAR 0.213384 LAYER VIA12 ;
    PORT
      LAYER POLY1 ;
        RECT 2.125 2.49 2.305 3.83 ;
        RECT 1.405 2.49 2.305 2.85 ;
        RECT 0.735 2.07 2.035 2.49 ;
        RECT 1.535 0.83 1.715 2.85 ;
        RECT 1.405 2.07 1.585 3.83 ;
        RECT 0.735 0.83 0.915 2.49 ;
      LAYER METAL1 ;
        RECT 0.87 2.11 1.995 2.45 ;
        RECT 0.87 2.055 1.32 2.505 ;
      LAYER METAL2 ;
        RECT 0.87 2.055 1.32 2.505 ;
      LAYER CONT ;
        RECT 0.985 2.17 1.205 2.39 ;
        RECT 1.715 2.17 1.935 2.39 ;
      LAYER VIA12 ;
        RECT 0.965 2.15 1.225 2.41 ;
    END
  END B2
  PIN VSS
    DIRECTION INOUT ;
    USE GROUND ;
    PORT
      LAYER METAL1 ;
        RECT -0.57 0 8.6 0.7 ;
        RECT 6.69 0 6.92 1.33 ;
        RECT 1.11 0 1.34 1.33 ;
    END
  END VSS
  PIN VDD
    DIRECTION INOUT ;
    USE POWER ;
    PORT
      LAYER METAL1 ;
        RECT -0.57 4.04 8.6 4.74 ;
        RECT 6.06 3.23 6.29 4.74 ;
        RECT 4.62 3.23 4.85 4.74 ;
    END
  END VDD
  PIN Y
    DIRECTION INOUT ;
    USE SIGNAL ;
    ANTENNAPARTIALCUTAREA 0.1352 LAYER VIA12 ;
    ANTENNADIFFAREA 1.4476 LAYER METAL2 ;
    ANTENNADIFFAREA 1.4476 LAYER METAL1 ;
    PORT
      LAYER DIFF ;
        RECT 4.995 1.16 5.515 1.38 ;
        RECT 4.995 0.95 5.415 1.77 ;
        RECT 4.895 1.3 5.415 1.52 ;
        RECT 3.025 2.95 3.565 3.61 ;
        RECT 2.615 1.3 3.135 1.52 ;
        RECT 2.615 1.05 3.035 1.77 ;
        RECT 2.515 1.16 3.035 1.38 ;
        RECT 1.585 2.95 2.125 3.61 ;
      LAYER METAL1 ;
        RECT 2.71 1.56 5.32 1.79 ;
        RECT 5.09 1.39 5.32 1.79 ;
        RECT 3.18 2.31 4.205 2.54 ;
        RECT 3.825 1.56 4.205 2.54 ;
        RECT 3.18 2.31 3.41 3.33 ;
        RECT 1.74 2.77 3.41 3 ;
        RECT 2.71 1.39 2.94 1.79 ;
        RECT 1.74 2.77 1.97 3.33 ;
      LAYER METAL2 ;
        RECT 3.79 1.56 4.24 2.46 ;
      LAYER CONT ;
        RECT 1.745 3.05 1.965 3.27 ;
        RECT 2.715 1.45 2.935 1.67 ;
        RECT 3.185 3.05 3.405 3.27 ;
        RECT 5.095 1.45 5.315 1.67 ;
      LAYER VIA12 ;
        RECT 3.885 2.14 4.145 2.4 ;
        RECT 3.885 1.62 4.145 1.88 ;
    END
  END Y
  PIN B1
    DIRECTION INOUT ;
    USE SIGNAL ;
    ANTENNAPARTIALCUTAREA 0.0676 LAYER VIA12 ;
    ANTENNAMODEL OXIDE1 ;
      ANTENNAGATEAREA 0.3168 LAYER METAL2 ;
      ANTENNAGATEAREA 0.3168 LAYER METAL1 ;
      ANTENNAMAXAREACAR 0.659722 LAYER METAL2 ;
      ANTENNAMAXCUTCAR 0.213384 LAYER VIA12 ;
    PORT
      LAYER POLY1 ;
        RECT 3.565 2.07 3.745 3.83 ;
        RECT 2.555 2.07 3.745 2.49 ;
        RECT 2.335 1.87 3.315 2.24 ;
        RECT 3.135 1.08 3.315 2.49 ;
        RECT 2.845 1.87 3.025 3.83 ;
        RECT 2.335 0.94 2.515 2.24 ;
      LAYER METAL1 ;
        RECT 2.365 2.11 2.935 2.45 ;
        RECT 2.365 2.09 2.745 2.47 ;
      LAYER METAL2 ;
        RECT 2.33 2.055 2.78 2.505 ;
      LAYER CONT ;
        RECT 2.655 2.17 2.875 2.39 ;
      LAYER VIA12 ;
        RECT 2.425 2.15 2.685 2.41 ;
    END
  END B1
  PIN A2
    DIRECTION INOUT ;
    USE SIGNAL ;
    ANTENNAPARTIALCUTAREA 0.0676 LAYER VIA12 ;
    ANTENNAMODEL OXIDE1 ;
      ANTENNAGATEAREA 0.3168 LAYER METAL2 ;
      ANTENNAGATEAREA 0.3168 LAYER METAL1 ;
      ANTENNAMAXAREACAR 1.363636 LAYER METAL2 ;
      ANTENNAMAXCUTCAR 0.213384 LAYER VIA12 ;
    PORT
      LAYER POLY1 ;
        RECT 7.115 0.83 7.295 2.49 ;
        RECT 5.995 2.07 7.295 2.49 ;
        RECT 6.445 2.07 6.625 3.83 ;
        RECT 6.315 0.83 6.495 2.73 ;
        RECT 5.725 2.49 6.625 2.73 ;
        RECT 5.725 2.49 5.905 3.83 ;
      LAYER METAL1 ;
        RECT 5.98 2.11 7.105 2.45 ;
        RECT 5.98 2.055 6.43 2.505 ;
      LAYER METAL2 ;
        RECT 5.98 2.055 6.43 2.505 ;
      LAYER CONT ;
        RECT 6.095 2.17 6.315 2.39 ;
        RECT 6.825 2.17 7.045 2.39 ;
      LAYER VIA12 ;
        RECT 6.075 2.15 6.335 2.41 ;
    END
  END A2
  PIN A1
    DIRECTION INOUT ;
    USE SIGNAL ;
    ANTENNAPARTIALCUTAREA 0.0676 LAYER VIA12 ;
    ANTENNAMODEL OXIDE1 ;
      ANTENNAGATEAREA 0.3168 LAYER METAL2 ;
      ANTENNAGATEAREA 0.3168 LAYER METAL1 ;
      ANTENNAMAXAREACAR 0.639205 LAYER METAL2 ;
      ANTENNAMAXCUTCAR 0.213384 LAYER VIA12 ;
    PORT
      LAYER POLY1 ;
        RECT 5.515 0.94 5.695 2.24 ;
        RECT 4.715 1.87 5.695 2.24 ;
        RECT 5.005 1.87 5.185 3.83 ;
        RECT 4.285 2.07 5.185 2.49 ;
        RECT 4.715 1.08 4.895 2.49 ;
        RECT 4.285 2.07 4.465 3.83 ;
      LAYER METAL1 ;
        RECT 4.52 2.055 4.97 2.505 ;
      LAYER METAL2 ;
        RECT 4.52 2.055 4.97 2.505 ;
      LAYER CONT ;
        RECT 4.635 2.17 4.855 2.39 ;
      LAYER VIA12 ;
        RECT 4.615 2.15 4.875 2.41 ;
    END
  END A1
  OBS
    LAYER METAL1 ;
      RECT 5.89 1.56 7.72 1.79 ;
      RECT 7.49 0.99 7.72 1.79 ;
      RECT 5.89 0.93 6.12 1.79 ;
      RECT 4.29 0.93 4.52 1.33 ;
      RECT 4.29 0.93 6.12 1.16 ;
      RECT 1.02 3.56 4.13 3.79 ;
      RECT 3.9 2.77 4.13 3.79 ;
      RECT 6.78 2.77 7.01 3.57 ;
      RECT 5.34 2.77 5.57 3.57 ;
      RECT 2.46 3.23 2.69 3.79 ;
      RECT 1.02 2.99 1.25 3.79 ;
      RECT 3.9 2.77 7.01 3 ;
      RECT 0.31 1.56 2.14 1.79 ;
      RECT 1.91 0.93 2.14 1.79 ;
      RECT 0.31 0.99 0.54 1.79 ;
      RECT 3.51 0.93 3.74 1.33 ;
      RECT 1.91 0.93 3.74 1.16 ;
  END
END a22oi_1

MACRO a22oi_2
  CLASS CORE ;
  ORIGIN 0 -0.35 ;
  FOREIGN a22oi_2 0 0.35 ;
  SIZE 14.6 BY 4.04 ;
  SYMMETRY X Y ;
  SITE core ;
  PIN A2
    DIRECTION INOUT ;
    USE SIGNAL ;
    ANTENNAPARTIALCUTAREA 0.0676 LAYER VIA12 ;
    ANTENNAMODEL OXIDE1 ;
      ANTENNAGATEAREA 0.6336 LAYER METAL2 ;
      ANTENNAGATEAREA 0.6336 LAYER METAL1 ;
      ANTENNAMAXAREACAR 1.465278 LAYER METAL2 ;
      ANTENNAMAXCUTCAR 0.106692 LAYER VIA12 ;
    PORT
      LAYER POLY1 ;
        RECT 13.6 0.83 13.78 2.49 ;
        RECT 13.295 2.07 13.715 2.5 ;
        RECT 11.17 2.07 13.78 2.49 ;
        RECT 11.835 2.07 12.985 2.5 ;
        RECT 12.8 0.83 12.98 2.5 ;
        RECT 12.61 2.07 12.79 3.83 ;
        RECT 11.89 2.07 12.79 2.73 ;
        RECT 12 0.83 12.18 2.73 ;
        RECT 11.89 2.07 12.07 3.83 ;
        RECT 10.45 2.49 11.525 2.5 ;
        RECT 11.2 0.83 11.38 2.5 ;
        RECT 11.17 2.07 11.35 3.83 ;
        RECT 10.45 2.49 11.35 2.73 ;
        RECT 11.105 2.08 11.35 2.73 ;
        RECT 10.45 2.49 10.63 3.83 ;
      LAYER METAL1 ;
        RECT 11.09 2.12 13.675 2.46 ;
        RECT 11.09 2.065 11.54 2.515 ;
      LAYER METAL2 ;
        RECT 11.09 2.065 11.54 2.515 ;
      LAYER CONT ;
        RECT 11.205 2.18 11.425 2.4 ;
        RECT 11.935 2.18 12.155 2.4 ;
        RECT 12.665 2.18 12.885 2.4 ;
        RECT 13.395 2.18 13.615 2.4 ;
      LAYER VIA12 ;
        RECT 11.185 2.16 11.445 2.42 ;
    END
  END A2
  PIN A1
    DIRECTION INOUT ;
    USE SIGNAL ;
    ANTENNAPARTIALCUTAREA 0.0676 LAYER VIA12 ;
    ANTENNAMODEL OXIDE1 ;
      ANTENNAGATEAREA 0.6336 LAYER METAL2 ;
      ANTENNAGATEAREA 0.6336 LAYER METAL1 ;
      ANTENNAMAXAREACAR 1.465278 LAYER METAL2 ;
      ANTENNAMAXCUTCAR 0.106692 LAYER VIA12 ;
    PORT
      LAYER POLY1 ;
        RECT 10.4 0.94 10.58 2.24 ;
        RECT 7.57 2.07 10.58 2.24 ;
        RECT 9.6 1.87 10.58 2.24 ;
        RECT 9.645 1.87 10.065 2.5 ;
        RECT 9.73 1.87 9.91 3.83 ;
        RECT 9.6 1.08 9.78 2.49 ;
        RECT 7.455 2.08 10.065 2.49 ;
        RECT 8.915 2.07 9.335 2.5 ;
        RECT 9.01 2.07 9.19 3.83 ;
        RECT 8.8 0.94 8.98 2.49 ;
        RECT 8.185 2.07 8.605 2.5 ;
        RECT 8.29 2.07 8.47 3.83 ;
        RECT 8 1.08 8.18 2.49 ;
        RECT 7.455 2.08 7.875 2.5 ;
        RECT 7.57 2.07 7.75 3.83 ;
      LAYER METAL1 ;
        RECT 7.44 2.12 10.025 2.46 ;
        RECT 7.44 2.065 7.89 2.515 ;
      LAYER METAL2 ;
        RECT 7.44 2.065 7.89 2.515 ;
      LAYER CONT ;
        RECT 7.555 2.18 7.775 2.4 ;
        RECT 8.285 2.18 8.505 2.4 ;
        RECT 9.015 2.18 9.235 2.4 ;
        RECT 9.745 2.18 9.965 2.4 ;
      LAYER VIA12 ;
        RECT 7.535 2.16 7.795 2.42 ;
    END
  END A1
  PIN Y
    DIRECTION INOUT ;
    USE SIGNAL ;
    ANTENNAPARTIALCUTAREA 0.1352 LAYER VIA12 ;
    ANTENNADIFFAREA 2.8112 LAYER METAL2 ;
    ANTENNADIFFAREA 2.8112 LAYER METAL1 ;
    PORT
      LAYER DIFF ;
        RECT 9.88 1.16 10.4 1.38 ;
        RECT 9.88 1.05 10.3 1.77 ;
        RECT 9.78 1.3 10.3 1.52 ;
        RECT 8.18 1.3 8.8 1.52 ;
        RECT 8.28 1.05 8.7 1.77 ;
        RECT 6.31 2.95 6.85 3.61 ;
        RECT 5.8 1.3 6.42 1.52 ;
        RECT 5.9 1.05 6.32 1.77 ;
        RECT 4.87 2.95 5.41 3.61 ;
        RECT 4.3 1.3 4.82 1.52 ;
        RECT 4.3 1.05 4.72 1.77 ;
        RECT 4.2 1.16 4.72 1.38 ;
        RECT 3.43 2.95 3.97 3.61 ;
        RECT 1.99 2.95 2.53 3.61 ;
      LAYER METAL1 ;
        RECT 4.395 1.56 10.205 1.79 ;
        RECT 9.975 1.39 10.205 1.79 ;
        RECT 8.375 1.39 8.605 1.79 ;
        RECT 6.465 2.31 7.125 2.54 ;
        RECT 6.745 1.56 7.125 2.54 ;
        RECT 6.465 2.31 6.695 3.33 ;
        RECT 2.145 2.77 6.695 3 ;
        RECT 5.995 1.39 6.225 1.79 ;
        RECT 5.025 2.77 5.255 3.33 ;
        RECT 4.395 1.39 4.625 1.79 ;
        RECT 3.585 2.77 3.815 3.33 ;
        RECT 2.145 2.77 2.375 3.33 ;
      LAYER METAL2 ;
        RECT 6.71 1.56 7.16 2.46 ;
      LAYER CONT ;
        RECT 2.15 3.05 2.37 3.27 ;
        RECT 3.59 3.05 3.81 3.27 ;
        RECT 4.4 1.45 4.62 1.67 ;
        RECT 5.03 3.05 5.25 3.27 ;
        RECT 6 1.45 6.22 1.67 ;
        RECT 6.47 3.05 6.69 3.27 ;
        RECT 8.38 1.45 8.6 1.67 ;
        RECT 9.98 1.45 10.2 1.67 ;
      LAYER VIA12 ;
        RECT 6.805 2.14 7.065 2.4 ;
        RECT 6.805 1.62 7.065 1.88 ;
    END
  END Y
  PIN B1
    DIRECTION INOUT ;
    USE SIGNAL ;
    ANTENNAPARTIALCUTAREA 0.0676 LAYER VIA12 ;
    ANTENNAMODEL OXIDE1 ;
      ANTENNAGATEAREA 0.6336 LAYER METAL2 ;
      ANTENNAGATEAREA 0.6336 LAYER METAL1 ;
      ANTENNAMAXAREACAR 1.018387 LAYER METAL2 ;
      ANTENNAMAXCUTCAR 0.106692 LAYER VIA12 ;
    PORT
      LAYER POLY1 ;
        RECT 6.85 2.07 7.03 3.83 ;
        RECT 4.535 2.07 7.03 2.49 ;
        RECT 6.42 1.08 6.6 2.49 ;
        RECT 6.13 2.07 6.31 3.83 ;
        RECT 5.855 2.07 6.31 2.5 ;
        RECT 5.62 0.94 5.8 2.49 ;
        RECT 5.41 2.07 5.59 3.83 ;
        RECT 4.02 1.87 5 2.24 ;
        RECT 4.82 1.08 5 2.49 ;
        RECT 4.535 1.87 4.955 2.5 ;
        RECT 4.69 1.87 4.87 3.83 ;
        RECT 4.02 0.94 4.2 2.24 ;
      LAYER METAL1 ;
        RECT 4.52 2.11 6.235 2.46 ;
        RECT 4.52 2.065 4.97 2.515 ;
      LAYER METAL2 ;
        RECT 4.52 2.065 4.97 2.515 ;
      LAYER CONT ;
        RECT 4.635 2.18 4.855 2.4 ;
        RECT 5.27 2.17 5.49 2.39 ;
        RECT 5.955 2.18 6.175 2.4 ;
      LAYER VIA12 ;
        RECT 4.615 2.16 4.875 2.42 ;
    END
  END B1
  PIN B2
    DIRECTION INOUT ;
    USE SIGNAL ;
    ANTENNAPARTIALCUTAREA 0.0676 LAYER VIA12 ;
    ANTENNAMODEL OXIDE1 ;
      ANTENNAGATEAREA 0.6336 LAYER METAL2 ;
      ANTENNAGATEAREA 0.6336 LAYER METAL1 ;
      ANTENNAMAXAREACAR 1.465278 LAYER METAL2 ;
      ANTENNAMAXCUTCAR 0.106692 LAYER VIA12 ;
    PORT
      LAYER POLY1 ;
        RECT 3.97 2.49 4.15 3.83 ;
        RECT 3.25 2.49 4.15 2.73 ;
        RECT 0.82 2.08 3.495 2.49 ;
        RECT 3.25 2.08 3.43 3.83 ;
        RECT 0.82 2.07 3.4 2.49 ;
        RECT 3.075 2.49 4.15 2.5 ;
        RECT 3.22 0.83 3.4 2.5 ;
        RECT 2.345 2.07 2.765 2.5 ;
        RECT 2.53 2.07 2.71 3.83 ;
        RECT 2.42 0.83 2.6 2.5 ;
        RECT 1.615 2.07 2.035 2.5 ;
        RECT 1.81 2.07 1.99 3.83 ;
        RECT 1.62 0.83 1.8 2.5 ;
        RECT 0.885 2.07 1.305 2.5 ;
        RECT 0.82 0.83 1 2.49 ;
      LAYER METAL1 ;
        RECT 0.87 2.12 3.455 2.46 ;
        RECT 0.87 2.065 1.32 2.515 ;
      LAYER METAL2 ;
        RECT 0.87 2.065 1.32 2.515 ;
      LAYER CONT ;
        RECT 0.985 2.18 1.205 2.4 ;
        RECT 1.715 2.18 1.935 2.4 ;
        RECT 2.445 2.18 2.665 2.4 ;
        RECT 3.175 2.18 3.395 2.4 ;
      LAYER VIA12 ;
        RECT 0.965 2.16 1.225 2.42 ;
    END
  END B2
  PIN VSS
    DIRECTION INOUT ;
    USE GROUND ;
    PORT
      LAYER METAL1 ;
        RECT -0.57 0 15.17 0.7 ;
        RECT 13.175 0 13.405 1.33 ;
        RECT 11.575 0 11.805 1.33 ;
        RECT 2.795 0 3.025 1.33 ;
        RECT 1.195 0 1.425 1.33 ;
    END
  END VSS
  PIN VDD
    DIRECTION INOUT ;
    USE POWER ;
    PORT
      LAYER METAL1 ;
        RECT -0.57 4.04 15.17 4.74 ;
        RECT 12.225 3.23 12.455 4.74 ;
        RECT 10.785 3.23 11.015 4.74 ;
        RECT 9.345 3.23 9.575 4.74 ;
        RECT 7.905 3.23 8.135 4.74 ;
    END
  END VDD
  OBS
    LAYER METAL1 ;
      RECT 10.775 1.56 14.205 1.79 ;
      RECT 13.975 0.99 14.205 1.79 ;
      RECT 12.375 0.98 12.605 1.79 ;
      RECT 10.775 0.93 11.005 1.79 ;
      RECT 9.175 0.93 9.405 1.33 ;
      RECT 7.575 0.93 7.805 1.33 ;
      RECT 7.575 0.93 11.005 1.16 ;
      RECT 1.425 3.56 7.415 3.79 ;
      RECT 7.185 2.77 7.415 3.79 ;
      RECT 12.945 2.77 13.175 3.57 ;
      RECT 11.505 2.77 11.735 3.57 ;
      RECT 10.065 2.77 10.295 3.57 ;
      RECT 8.625 2.77 8.855 3.57 ;
      RECT 5.745 3.23 5.975 3.79 ;
      RECT 4.305 3.23 4.535 3.79 ;
      RECT 2.865 3.23 3.095 3.79 ;
      RECT 1.425 2.99 1.655 3.79 ;
      RECT 7.185 2.77 13.175 3 ;
      RECT 0.395 1.56 3.825 1.79 ;
      RECT 3.595 0.93 3.825 1.79 ;
      RECT 1.995 0.98 2.225 1.79 ;
      RECT 0.395 0.99 0.625 1.79 ;
      RECT 6.795 0.93 7.025 1.33 ;
      RECT 5.195 0.93 5.425 1.33 ;
      RECT 3.595 0.93 7.025 1.16 ;
  END
END a22oi_2

MACRO buf_1
  CLASS CORE ;
  ORIGIN 0 -0.35 ;
  FOREIGN buf_1 0 0.35 ;
  SIZE 2.92 BY 4.04 ;
  SYMMETRY X Y ;
  SITE core ;
  PIN VSS
    DIRECTION INOUT ;
    USE GROUND ;
    PORT
      LAYER METAL1 ;
        RECT -0.57 0 3.49 0.7 ;
        RECT 1.345 0 1.575 1.33 ;
    END
  END VSS
  PIN A
    DIRECTION INOUT ;
    USE SIGNAL ;
    ANTENNAPARTIALCUTAREA 0.0676 LAYER VIA12 ;
    ANTENNAMODEL OXIDE1 ;
      ANTENNAGATEAREA 0.1584 LAYER METAL2 ;
      ANTENNAGATEAREA 0.1584 LAYER METAL1 ;
      ANTENNAMAXAREACAR 1.278409 LAYER METAL2 ;
      ANTENNAMAXCUTCAR 0.426768 LAYER VIA12 ;
    PORT
      LAYER POLY1 ;
        RECT 0.885 2.05 1.305 2.47 ;
        RECT 1.01 2.05 1.19 3.83 ;
        RECT 0.97 0.83 1.15 2.47 ;
      LAYER METAL1 ;
        RECT 0.87 2.035 1.32 2.485 ;
      LAYER METAL2 ;
        RECT 0.87 2.035 1.32 2.485 ;
      LAYER CONT ;
        RECT 0.985 2.15 1.205 2.37 ;
      LAYER VIA12 ;
        RECT 0.965 2.13 1.225 2.39 ;
    END
  END A
  PIN VDD
    DIRECTION INOUT ;
    USE POWER ;
    PORT
      LAYER METAL1 ;
        RECT -0.57 4.04 3.49 4.74 ;
        RECT 1.345 3.23 1.575 4.74 ;
    END
  END VDD
  PIN X
    DIRECTION INOUT ;
    USE SIGNAL ;
    ANTENNAPARTIALCUTAREA 0.2028 LAYER VIA12 ;
    ANTENNADIFFAREA 0.5152 LAYER METAL2 ;
    ANTENNADIFFAREA 0.5152 LAYER METAL1 ;
    PORT
      LAYER DIFF ;
        RECT 2.05 0.95 2.47 1.37 ;
        RECT 1.95 1.05 2.47 1.27 ;
        RECT 1.91 2.95 2.39 3.61 ;
      LAYER METAL1 ;
        RECT 2.065 2.99 2.71 3.22 ;
        RECT 2.33 1.1 2.71 3.22 ;
        RECT 2.145 0.99 2.375 1.33 ;
        RECT 2.065 2.99 2.295 3.57 ;
      LAYER METAL2 ;
        RECT 2.33 1.475 2.78 2.895 ;
      LAYER CONT ;
        RECT 2.07 3.17 2.29 3.39 ;
        RECT 2.15 1.05 2.37 1.27 ;
      LAYER VIA12 ;
        RECT 2.39 2.575 2.65 2.835 ;
        RECT 2.39 2.055 2.65 2.315 ;
        RECT 2.39 1.535 2.65 1.795 ;
    END
  END X
  OBS
    LAYER METAL1 ;
      RECT 0.625 2.77 0.855 3.57 ;
      RECT 0.625 2.77 1.835 3 ;
      RECT 1.605 1.56 1.835 3 ;
      RECT 1.605 1.815 1.995 2.625 ;
      RECT 0.545 1.56 1.835 1.79 ;
      RECT 0.545 0.99 0.775 1.79 ;
  END
END buf_1

MACRO buf_16
  CLASS CORE ;
  ORIGIN 0 -0.35 ;
  FOREIGN buf_16 0 0.35 ;
  SIZE 18.98 BY 4.04 ;
  SYMMETRY X Y ;
  SITE core ;
  PIN X
    DIRECTION INOUT ;
    USE SIGNAL ;
    ANTENNAPARTIALCUTAREA 0.2028 LAYER VIA12 ;
    ANTENNADIFFAREA 4.6144 LAYER METAL2 ;
    ANTENNADIFFAREA 4.6144 LAYER METAL1 ;
    PORT
      LAYER DIFF ;
        RECT 17.05 1.05 17.67 1.27 ;
        RECT 17.15 0.95 17.57 1.37 ;
        RECT 15.92 2.95 16.46 3.61 ;
        RECT 15.45 1.05 16.07 1.27 ;
        RECT 15.55 0.95 15.97 1.37 ;
        RECT 14.48 2.95 15.02 3.61 ;
        RECT 13.85 1.05 14.47 1.27 ;
        RECT 13.95 0.95 14.37 1.37 ;
        RECT 13.04 2.95 13.58 3.61 ;
        RECT 12.25 1.05 12.87 1.27 ;
        RECT 12.35 0.95 12.77 1.37 ;
        RECT 11.6 2.95 12.14 3.61 ;
        RECT 10.65 1.05 11.27 1.27 ;
        RECT 10.75 0.95 11.17 1.37 ;
        RECT 10.16 2.95 10.7 3.61 ;
        RECT 9.05 1.05 9.67 1.27 ;
        RECT 9.15 0.95 9.57 1.37 ;
        RECT 8.72 2.95 9.26 3.61 ;
        RECT 7.45 1.05 8.07 1.27 ;
        RECT 7.55 0.95 7.97 1.37 ;
        RECT 7.28 2.95 7.82 3.61 ;
        RECT 5.85 1.05 6.47 1.27 ;
        RECT 5.95 0.95 6.37 1.37 ;
        RECT 5.84 2.95 6.38 3.61 ;
      LAYER METAL1 ;
        RECT 5.995 2.77 18.805 3 ;
        RECT 18.425 1.56 18.805 3 ;
        RECT 6.045 1.56 18.805 1.79 ;
        RECT 17.245 0.99 17.475 1.79 ;
        RECT 16.075 2.77 16.305 3.57 ;
        RECT 15.645 0.99 15.875 1.79 ;
        RECT 14.635 2.77 14.865 3.57 ;
        RECT 14.045 0.99 14.275 1.79 ;
        RECT 13.195 2.77 13.425 3.57 ;
        RECT 12.445 0.99 12.675 1.79 ;
        RECT 11.755 2.77 11.985 3.57 ;
        RECT 10.845 0.99 11.075 1.79 ;
        RECT 10.315 2.77 10.545 3.57 ;
        RECT 9.245 0.99 9.475 1.79 ;
        RECT 8.875 2.77 9.105 3.57 ;
        RECT 7.645 0.99 7.875 1.79 ;
        RECT 7.435 2.77 7.665 3.57 ;
        RECT 6.045 0.99 6.275 1.79 ;
        RECT 5.995 2.77 6.225 3.57 ;
      LAYER METAL2 ;
        RECT 18.39 1.565 18.84 2.985 ;
      LAYER CONT ;
        RECT 6 3.17 6.22 3.39 ;
        RECT 6.05 1.05 6.27 1.27 ;
        RECT 7.44 3.17 7.66 3.39 ;
        RECT 7.65 1.05 7.87 1.27 ;
        RECT 8.88 3.17 9.1 3.39 ;
        RECT 9.25 1.05 9.47 1.27 ;
        RECT 10.32 3.17 10.54 3.39 ;
        RECT 10.85 1.05 11.07 1.27 ;
        RECT 11.76 3.17 11.98 3.39 ;
        RECT 12.45 1.05 12.67 1.27 ;
        RECT 13.2 3.17 13.42 3.39 ;
        RECT 14.05 1.05 14.27 1.27 ;
        RECT 14.64 3.17 14.86 3.39 ;
        RECT 15.65 1.05 15.87 1.27 ;
        RECT 16.08 3.17 16.3 3.39 ;
        RECT 17.25 1.05 17.47 1.27 ;
      LAYER VIA12 ;
        RECT 18.485 2.665 18.745 2.925 ;
        RECT 18.485 2.145 18.745 2.405 ;
        RECT 18.485 1.625 18.745 1.885 ;
    END
  END X
  PIN A
    DIRECTION INOUT ;
    USE SIGNAL ;
    ANTENNAPARTIALMETALAREA 0.405 LAYER METAL2 ;
    ANTENNAPARTIALCUTAREA 0.2028 LAYER VIA12 ;
    ANTENNAMODEL OXIDE1 ;
      ANTENNAGATEAREA 0.9504 LAYER METAL2 ;
      ANTENNAGATEAREA 0.9504 LAYER METAL1 ;
      ANTENNAMAXAREACAR 2.367424 LAYER METAL2 ;
      ANTENNAMAXCUTCAR 0.213384 LAYER VIA12 ;
    PORT
      LAYER POLY1 ;
        RECT 4.94 1.785 5.12 3.83 ;
        RECT 4.87 0.83 5.05 2.625 ;
        RECT 0.74 1.785 5.12 2.625 ;
        RECT 4.22 1.785 4.4 3.83 ;
        RECT 4.07 0.83 4.25 2.625 ;
        RECT 3.5 1.785 3.68 3.83 ;
        RECT 3.27 0.83 3.45 2.625 ;
        RECT 2.78 1.785 2.96 3.83 ;
        RECT 2.47 0.83 2.65 2.625 ;
        RECT 2.06 1.785 2.24 3.83 ;
        RECT 1.67 0.83 1.85 2.625 ;
        RECT 1.34 1.785 1.52 3.83 ;
        RECT 0.87 0.83 1.05 2.625 ;
      LAYER METAL1 ;
        RECT 0.87 2.05 4.97 2.5 ;
      LAYER METAL2 ;
        RECT 4.52 2.05 4.97 2.5 ;
        RECT 3.06 2.05 3.51 2.5 ;
        RECT 0.87 2.05 1.32 2.5 ;
      LAYER CONT ;
        RECT 0.985 2.165 1.205 2.385 ;
        RECT 1.715 2.165 1.935 2.385 ;
        RECT 2.445 2.165 2.665 2.385 ;
        RECT 3.175 2.165 3.395 2.385 ;
        RECT 3.905 2.165 4.125 2.385 ;
        RECT 4.635 2.165 4.855 2.385 ;
      LAYER VIA12 ;
        RECT 0.965 2.145 1.225 2.405 ;
        RECT 3.155 2.145 3.415 2.405 ;
        RECT 4.615 2.145 4.875 2.405 ;
    END
  END A
  PIN VDD
    DIRECTION INOUT ;
    USE POWER ;
    PORT
      LAYER METAL1 ;
        RECT -0.57 4.04 19.55 4.74 ;
        RECT 16.795 3.23 17.025 4.74 ;
        RECT 15.355 3.23 15.585 4.74 ;
        RECT 13.915 3.23 14.145 4.74 ;
        RECT 12.475 3.23 12.705 4.74 ;
        RECT 11.035 3.23 11.265 4.74 ;
        RECT 9.595 3.23 9.825 4.74 ;
        RECT 8.155 3.23 8.385 4.74 ;
        RECT 6.715 3.23 6.945 4.74 ;
        RECT 5.275 3.23 5.505 4.74 ;
        RECT 3.835 3.23 4.065 4.74 ;
        RECT 2.395 3.23 2.625 4.74 ;
        RECT 0.955 3.23 1.185 4.74 ;
    END
  END VDD
  PIN VSS
    DIRECTION INOUT ;
    USE GROUND ;
    PORT
      LAYER METAL1 ;
        RECT -0.57 0 19.55 0.7 ;
        RECT 18.045 0 18.275 1.33 ;
        RECT 16.445 0 16.675 1.33 ;
        RECT 14.845 0 15.075 1.33 ;
        RECT 13.245 0 13.475 1.33 ;
        RECT 11.645 0 11.875 1.33 ;
        RECT 10.045 0 10.275 1.33 ;
        RECT 8.445 0 8.675 1.33 ;
        RECT 6.845 0 7.075 1.33 ;
        RECT 5.245 0 5.475 1.33 ;
        RECT 3.645 0 3.875 1.33 ;
        RECT 2.045 0 2.275 1.33 ;
        RECT 0.445 0 0.675 1.33 ;
    END
  END VSS
  OBS
    LAYER METAL1 ;
      RECT 4.555 2.77 4.785 3.57 ;
      RECT 3.115 2.77 3.345 3.57 ;
      RECT 1.675 2.77 1.905 3.57 ;
      RECT 1.675 2.77 5.765 3 ;
      RECT 5.535 1.56 5.765 3 ;
      RECT 5.535 2.105 17.325 2.445 ;
      RECT 1.245 1.56 5.765 1.79 ;
      RECT 4.445 0.99 4.675 1.79 ;
      RECT 2.845 0.99 3.075 1.79 ;
      RECT 1.245 0.99 1.475 1.79 ;
  END
END buf_16

MACRO buf_2
  CLASS CORE ;
  ORIGIN 0 -0.35 ;
  FOREIGN buf_2 0 0.35 ;
  SIZE 3.65 BY 4.04 ;
  SYMMETRY X Y ;
  SITE core ;
  PIN VSS
    DIRECTION INOUT ;
    USE GROUND ;
    PORT
      LAYER METAL1 ;
        RECT -0.57 0 4.22 0.7 ;
        RECT 2.885 0 3.115 1.33 ;
        RECT 1.285 0 1.515 1.33 ;
    END
  END VSS
  PIN A
    DIRECTION INOUT ;
    USE SIGNAL ;
    ANTENNAPARTIALCUTAREA 0.0676 LAYER VIA12 ;
    ANTENNAMODEL OXIDE1 ;
      ANTENNAGATEAREA 0.1584 LAYER METAL2 ;
      ANTENNAGATEAREA 0.1584 LAYER METAL1 ;
      ANTENNAMAXAREACAR 1.278409 LAYER METAL2 ;
      ANTENNAMAXCUTCAR 0.426768 LAYER VIA12 ;
    PORT
      LAYER POLY1 ;
        RECT 0.885 2.07 1.305 2.49 ;
        RECT 0.99 2.07 1.17 3.83 ;
        RECT 0.91 0.83 1.09 2.49 ;
      LAYER METAL1 ;
        RECT 0.87 2.055 1.32 2.505 ;
      LAYER METAL2 ;
        RECT 0.87 2.055 1.32 2.505 ;
      LAYER CONT ;
        RECT 0.985 2.17 1.205 2.39 ;
      LAYER VIA12 ;
        RECT 0.965 2.15 1.225 2.41 ;
    END
  END A
  PIN VDD
    DIRECTION INOUT ;
    USE POWER ;
    PORT
      LAYER METAL1 ;
        RECT -0.57 4.04 4.22 4.74 ;
        RECT 2.765 3.23 2.995 4.74 ;
        RECT 1.325 3.23 1.555 4.74 ;
    END
  END VDD
  PIN X
    DIRECTION INOUT ;
    USE SIGNAL ;
    ANTENNAPARTIALCUTAREA 0.2028 LAYER VIA12 ;
    ANTENNADIFFAREA 0.5768 LAYER METAL2 ;
    ANTENNADIFFAREA 0.5768 LAYER METAL1 ;
    PORT
      LAYER DIFF ;
        RECT 1.89 1.05 2.51 1.27 ;
        RECT 1.99 0.95 2.41 1.37 ;
        RECT 1.89 2.95 2.43 3.61 ;
      LAYER METAL1 ;
        RECT 2.045 2.77 3.445 3 ;
        RECT 3.065 1.56 3.445 3 ;
        RECT 2.085 1.56 3.445 1.79 ;
        RECT 2.085 0.99 2.315 1.79 ;
        RECT 2.045 2.77 2.275 3.57 ;
      LAYER METAL2 ;
        RECT 3.06 1.57 3.51 2.99 ;
      LAYER CONT ;
        RECT 2.05 3.17 2.27 3.39 ;
        RECT 2.09 1.05 2.31 1.27 ;
      LAYER VIA12 ;
        RECT 3.125 2.67 3.385 2.93 ;
        RECT 3.125 2.15 3.385 2.41 ;
        RECT 3.125 1.63 3.385 1.89 ;
    END
  END X
  OBS
    LAYER METAL1 ;
      RECT 0.605 2.77 0.835 3.57 ;
      RECT 0.605 2.77 1.815 3 ;
      RECT 1.585 1.56 1.815 3 ;
      RECT 1.585 2.11 2.725 2.45 ;
      RECT 0.485 1.56 1.815 1.79 ;
      RECT 0.485 0.99 0.715 1.79 ;
  END
END buf_2

MACRO buf_4
  CLASS CORE ;
  ORIGIN 0 -0.35 ;
  FOREIGN buf_4 0 0.35 ;
  SIZE 5.11 BY 4.04 ;
  SYMMETRY X Y ;
  SITE core ;
  PIN VSS
    DIRECTION INOUT ;
    USE GROUND ;
    PORT
      LAYER METAL1 ;
        RECT -0.57 0 5.68 0.7 ;
        RECT 4.405 0 4.635 1.33 ;
        RECT 2.805 0 3.035 1.33 ;
        RECT 1.205 0 1.435 1.33 ;
    END
  END VSS
  PIN A
    DIRECTION INOUT ;
    USE SIGNAL ;
    ANTENNAPARTIALCUTAREA 0.0676 LAYER VIA12 ;
    ANTENNAMODEL OXIDE1 ;
      ANTENNAGATEAREA 0.1584 LAYER METAL2 ;
      ANTENNAGATEAREA 0.1584 LAYER METAL1 ;
      ANTENNAMAXAREACAR 1.278409 LAYER METAL2 ;
      ANTENNAMAXCUTCAR 0.426768 LAYER VIA12 ;
    PORT
      LAYER POLY1 ;
        RECT 0.83 2.07 1.29 2.49 ;
        RECT 0.99 2.07 1.17 3.83 ;
        RECT 0.83 0.83 1.01 2.49 ;
      LAYER METAL1 ;
        RECT 0.855 2.055 1.305 2.505 ;
      LAYER METAL2 ;
        RECT 0.87 2.055 1.32 2.505 ;
      LAYER CONT ;
        RECT 0.97 2.17 1.19 2.39 ;
      LAYER VIA12 ;
        RECT 0.95 2.15 1.21 2.41 ;
    END
  END A
  PIN VDD
    DIRECTION INOUT ;
    USE POWER ;
    PORT
      LAYER METAL1 ;
        RECT -0.57 4.04 5.68 4.74 ;
        RECT 4.205 3.23 4.435 4.74 ;
        RECT 2.765 3.23 2.995 4.74 ;
        RECT 1.325 3.23 1.555 4.74 ;
    END
  END VDD
  PIN X
    DIRECTION INOUT ;
    USE SIGNAL ;
    ANTENNAPARTIALCUTAREA 0.2028 LAYER VIA12 ;
    ANTENNADIFFAREA 1.1536 LAYER METAL2 ;
    ANTENNADIFFAREA 1.1536 LAYER METAL1 ;
    PORT
      LAYER DIFF ;
        RECT 3.41 1.05 4.03 1.27 ;
        RECT 3.51 0.95 3.93 1.37 ;
        RECT 3.33 2.95 3.87 3.61 ;
        RECT 1.81 1.05 2.43 1.27 ;
        RECT 1.91 0.95 2.33 1.37 ;
        RECT 1.89 2.95 2.43 3.61 ;
      LAYER METAL1 ;
        RECT 2.045 2.77 4.205 3 ;
        RECT 3.825 1.56 4.205 3 ;
        RECT 3.605 0.99 3.835 1.79 ;
        RECT 3.485 2.77 3.715 3.57 ;
        RECT 2.005 1.56 4.205 1.79 ;
        RECT 2.045 2.77 2.275 3.57 ;
        RECT 2.005 0.99 2.235 1.79 ;
      LAYER METAL2 ;
        RECT 3.79 1.57 4.24 2.99 ;
      LAYER CONT ;
        RECT 2.01 1.05 2.23 1.27 ;
        RECT 2.05 3.17 2.27 3.39 ;
        RECT 3.49 3.17 3.71 3.39 ;
        RECT 3.61 1.05 3.83 1.27 ;
      LAYER VIA12 ;
        RECT 3.885 2.67 4.145 2.93 ;
        RECT 3.885 2.15 4.145 2.41 ;
        RECT 3.885 1.63 4.145 1.89 ;
    END
  END X
  OBS
    LAYER METAL1 ;
      RECT 0.605 2.77 0.835 3.57 ;
      RECT 0.605 2.77 1.775 3 ;
      RECT 1.545 1.56 1.775 3 ;
      RECT 1.545 2.11 3.455 2.45 ;
      RECT 0.405 1.56 1.775 1.79 ;
      RECT 0.405 0.99 0.635 1.79 ;
  END
END buf_4

MACRO buf_8
  CLASS CORE ;
  ORIGIN 0 -0.35 ;
  FOREIGN buf_8 0 0.35 ;
  SIZE 10.22 BY 4.04 ;
  SYMMETRY X Y ;
  SITE core ;
  PIN VSS
    DIRECTION INOUT ;
    USE GROUND ;
    PORT
      LAYER METAL1 ;
        RECT -0.57 0 10.79 0.7 ;
        RECT 9.325 0 9.555 1.33 ;
        RECT 7.725 0 7.955 1.33 ;
        RECT 6.125 0 6.355 1.33 ;
        RECT 4.525 0 4.755 1.33 ;
        RECT 2.925 0 3.155 1.33 ;
        RECT 1.325 0 1.555 1.33 ;
    END
  END VSS
  PIN A
    DIRECTION INOUT ;
    USE SIGNAL ;
    ANTENNAPARTIALMETALAREA 0.405 LAYER METAL2 ;
    ANTENNAPARTIALCUTAREA 0.2028 LAYER VIA12 ;
    ANTENNAMODEL OXIDE1 ;
      ANTENNAGATEAREA 0.4752 LAYER METAL2 ;
      ANTENNAGATEAREA 0.4752 LAYER METAL1 ;
      ANTENNAMAXAREACAR 2.660985 LAYER METAL2 ;
      ANTENNAMAXCUTCAR 0.426768 LAYER VIA12 ;
    PORT
      LAYER POLY1 ;
        RECT 2.79 2.015 2.97 3.83 ;
        RECT 0.885 2.015 2.97 2.545 ;
        RECT 2.55 0.83 2.73 2.545 ;
        RECT 2.07 2.015 2.25 3.83 ;
        RECT 1.75 0.83 1.93 2.545 ;
        RECT 1.35 2.015 1.53 3.83 ;
        RECT 0.95 0.83 1.13 2.545 ;
      LAYER METAL1 ;
        RECT 0.87 2.055 2.78 2.505 ;
      LAYER METAL2 ;
        RECT 2.33 2.055 2.78 2.505 ;
        RECT 1.6 2.055 2.05 2.505 ;
        RECT 0.87 2.055 1.32 2.505 ;
      LAYER CONT ;
        RECT 0.985 2.17 1.205 2.39 ;
        RECT 1.715 2.17 1.935 2.39 ;
        RECT 2.445 2.17 2.665 2.39 ;
      LAYER VIA12 ;
        RECT 0.965 2.15 1.225 2.41 ;
        RECT 1.695 2.15 1.955 2.41 ;
        RECT 2.425 2.15 2.685 2.41 ;
    END
  END A
  PIN VDD
    DIRECTION INOUT ;
    USE POWER ;
    PORT
      LAYER METAL1 ;
        RECT -0.57 4.04 10.79 4.74 ;
        RECT 8.885 3.23 9.115 4.74 ;
        RECT 7.445 3.23 7.675 4.74 ;
        RECT 6.005 3.23 6.235 4.74 ;
        RECT 4.565 3.23 4.795 4.74 ;
        RECT 3.125 3.23 3.355 4.74 ;
        RECT 1.685 3.23 1.915 4.74 ;
    END
  END VDD
  PIN X
    DIRECTION INOUT ;
    USE SIGNAL ;
    ANTENNAPARTIALCUTAREA 0.2028 LAYER VIA12 ;
    ANTENNADIFFAREA 2.3072 LAYER METAL2 ;
    ANTENNADIFFAREA 2.3072 LAYER METAL1 ;
    PORT
      LAYER DIFF ;
        RECT 8.33 1.05 8.95 1.27 ;
        RECT 8.43 0.95 8.85 1.37 ;
        RECT 8.01 2.95 8.55 3.61 ;
        RECT 6.73 1.05 7.35 1.27 ;
        RECT 6.83 0.95 7.25 1.37 ;
        RECT 6.57 2.95 7.11 3.61 ;
        RECT 5.13 1.05 5.75 1.27 ;
        RECT 5.23 0.95 5.65 1.37 ;
        RECT 5.13 2.95 5.67 3.61 ;
        RECT 3.69 2.95 4.23 3.61 ;
        RECT 3.53 1.05 4.15 1.27 ;
        RECT 3.63 0.95 4.05 1.37 ;
      LAYER METAL1 ;
        RECT 3.845 2.77 10.045 3 ;
        RECT 9.665 1.56 10.045 3 ;
        RECT 3.725 1.56 10.045 1.79 ;
        RECT 8.525 0.99 8.755 1.79 ;
        RECT 8.165 2.77 8.395 3.57 ;
        RECT 6.925 0.99 7.155 1.79 ;
        RECT 6.725 2.77 6.955 3.57 ;
        RECT 5.325 0.99 5.555 1.79 ;
        RECT 5.285 2.77 5.515 3.57 ;
        RECT 3.845 2.77 4.075 3.57 ;
        RECT 3.725 0.99 3.955 1.79 ;
      LAYER METAL2 ;
        RECT 9.63 1.57 10.08 2.99 ;
      LAYER CONT ;
        RECT 3.73 1.05 3.95 1.27 ;
        RECT 3.85 3.17 4.07 3.39 ;
        RECT 5.29 3.17 5.51 3.39 ;
        RECT 5.33 1.05 5.55 1.27 ;
        RECT 6.73 3.17 6.95 3.39 ;
        RECT 6.93 1.05 7.15 1.27 ;
        RECT 8.17 3.17 8.39 3.39 ;
        RECT 8.53 1.05 8.75 1.27 ;
      LAYER VIA12 ;
        RECT 9.725 2.67 9.985 2.93 ;
        RECT 9.725 2.15 9.985 2.41 ;
        RECT 9.725 1.63 9.985 1.89 ;
    END
  END X
  OBS
    LAYER METAL1 ;
      RECT 2.405 2.77 2.635 3.57 ;
      RECT 0.965 2.77 1.195 3.57 ;
      RECT 0.965 2.77 3.24 3 ;
      RECT 3.01 1.56 3.24 3 ;
      RECT 3.01 2.11 8.565 2.45 ;
      RECT 0.525 1.56 3.24 1.79 ;
      RECT 2.125 0.99 2.355 1.79 ;
      RECT 0.525 0.99 0.755 1.79 ;
  END
END buf_8

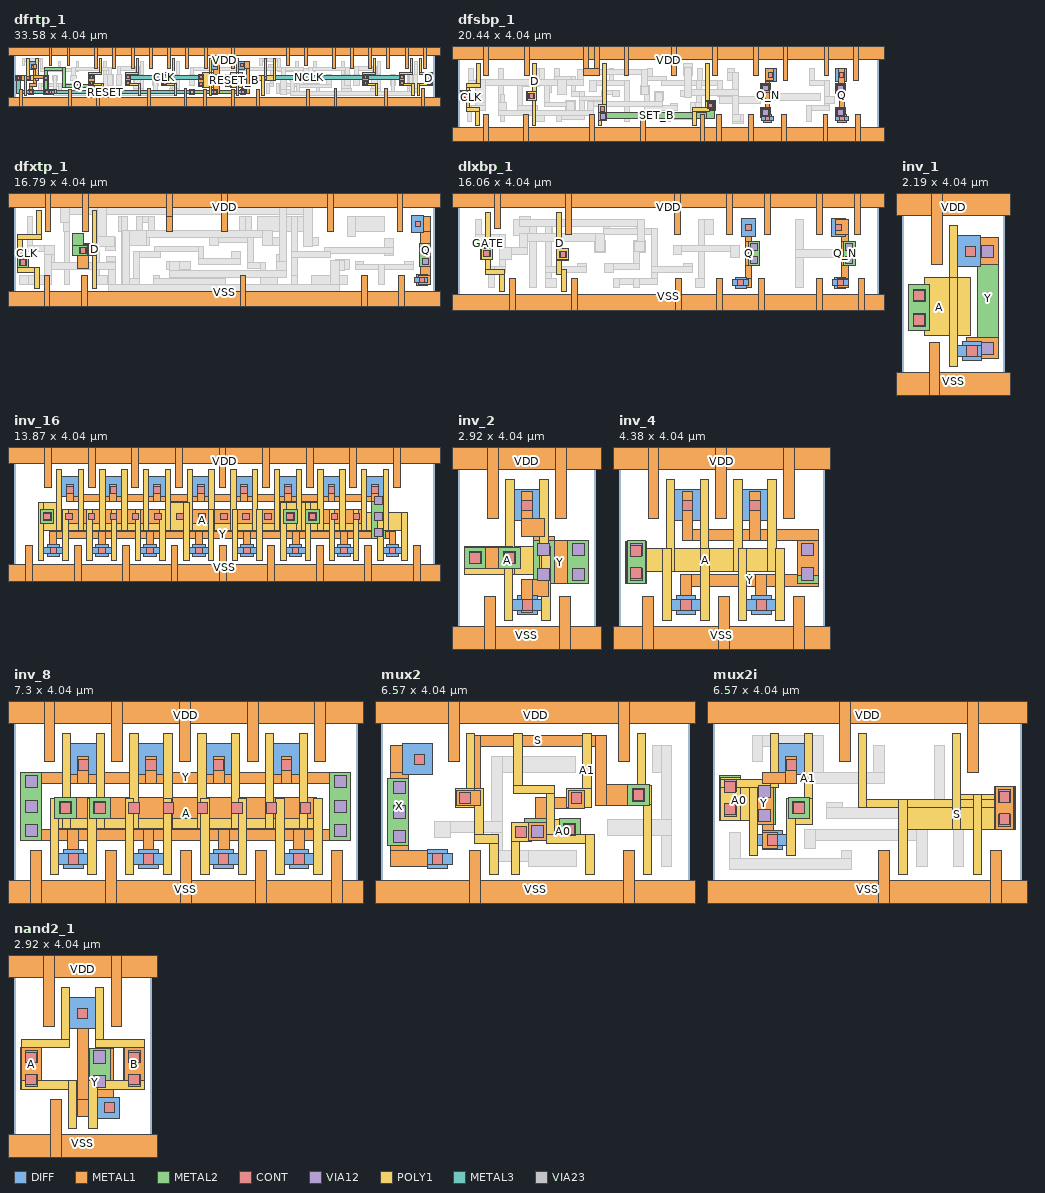
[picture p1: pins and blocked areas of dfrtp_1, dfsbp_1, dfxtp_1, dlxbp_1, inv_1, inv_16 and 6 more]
MACRO dfrtp_1
  CLASS CORE ;
  ORIGIN 0 -0.35 ;
  FOREIGN dfrtp_1 0 0.35 ;
  SIZE 33.58 BY 4.04 ;
  SYMMETRY X Y ;
  SITE core ;
  PIN RESET
    USE SIGNAL ;
    ANTENNAPARTIALMETALAREA 1.4424 LAYER METAL2 ;
    ANTENNAPARTIALCUTAREA 0.1352 LAYER VIA12 ;
    ANTENNAPARTIALCUTAREA 0.0676 LAYER VIA23 ;
    ANTENNADIFFAREA 0.5152 LAYER METAL1 ;
    ANTENNADIFFAREA 0.5152 LAYER METAL2 ;
    ANTENNADIFFAREA 0.5152 LAYER METAL3 ;
    ANTENNAMODEL OXIDE1 ;
      ANTENNAGATEAREA 0.2772 LAYER METAL1 ;
      ANTENNAGATEAREA 0.2772 LAYER METAL2 ;
      ANTENNAGATEAREA 0.5544 LAYER METAL3 ;
      ANTENNAMAXAREACAR 12.416306 LAYER METAL3 ;
      ANTENNAMAXAREACAR 11.685786 LAYER METAL2 ;
      ANTENNAMAXCUTCAR 0.487734 LAYER VIA12 ;
      ANTENNAMAXCUTCAR 0.731602 LAYER VIA23 ;
    PORT
      LAYER METAL3 ;
        RECT 14.01 0.93 14.46 1.38 ;
        RECT 0.225 0.99 14.46 1.27 ;
        RECT 0.14 2.055 0.59 2.505 ;
        RECT 0.225 0.99 0.505 2.505 ;
      LAYER METAL2 ;
        RECT 19.12 2.055 19.57 2.505 ;
        RECT 18.165 0.99 18.615 1.44 ;
        RECT 14.01 0.99 18.615 1.27 ;
        RECT 14.01 0.93 14.46 1.38 ;
        RECT 0.14 2.055 0.59 2.505 ;
      LAYER POLY1 ;
        RECT 20.73 2.07 20.91 3.83 ;
        RECT 19.135 2.07 20.91 2.49 ;
        RECT 20.01 2.07 20.19 3.83 ;
        RECT 19.82 0.83 20 2.49 ;
        RECT 1.75 2.07 1.93 3.83 ;
        RECT 0.155 2.07 1.93 2.49 ;
        RECT 1.03 2.07 1.21 3.83 ;
        RECT 0.84 0.83 1.02 2.49 ;
      LAYER DIFF ;
        RECT 18.07 0.95 18.49 1.37 ;
        RECT 17.97 1.05 18.49 1.27 ;
        RECT 17.98 2.95 18.46 3.61 ;
      LAYER METAL1 ;
        RECT 18.56 2.055 20.285 2.505 ;
        RECT 18.135 2.99 18.84 3.57 ;
        RECT 18.56 0.99 18.84 3.57 ;
        RECT 18.165 0.99 18.84 1.44 ;
        RECT 0.14 2.055 1.305 2.505 ;
      LAYER CONT ;
        RECT 0.255 2.17 0.475 2.39 ;
        RECT 1.025 2.17 1.245 2.39 ;
        RECT 18.14 3.17 18.36 3.39 ;
        RECT 18.17 1.05 18.39 1.27 ;
        RECT 19.235 2.17 19.455 2.39 ;
        RECT 20.005 2.17 20.225 2.39 ;
      LAYER VIA23 ;
        RECT 0.235 2.15 0.495 2.41 ;
        RECT 14.105 1.025 14.365 1.285 ;
      LAYER VIA12 ;
        RECT 0.235 2.15 0.495 2.41 ;
        RECT 18.26 1.085 18.52 1.345 ;
        RECT 19.215 2.15 19.475 2.41 ;
    END
  END RESET
  PIN VSS
    DIRECTION INOUT ;
    USE GROUND ;
    PORT
      LAYER METAL1 ;
        RECT -0.57 0 34.15 0.7 ;
        RECT 32.58 0 32.81 1.45 ;
        RECT 29.66 0 29.89 1.45 ;
        RECT 25.59 0 25.82 1.45 ;
        RECT 23.375 0 23.605 1.33 ;
        RECT 19.395 0 19.625 1.33 ;
        RECT 17.365 0 17.595 1.33 ;
        RECT 15.175 0 15.405 1.33 ;
        RECT 13.6 0 13.83 1.45 ;
        RECT 10.68 0 10.91 1.45 ;
        RECT 6.61 0 6.84 1.45 ;
        RECT 4.395 0 4.625 1.33 ;
        RECT 0.415 0 0.645 1.33 ;
    END
  END VSS
  PIN VDD
    DIRECTION INOUT ;
    USE POWER ;
    PORT
      LAYER METAL1 ;
        RECT -0.57 4.04 34.15 4.74 ;
        RECT 32.725 2.99 32.955 4.74 ;
        RECT 31.285 2.99 31.515 4.74 ;
        RECT 29.805 2.99 30.035 4.74 ;
        RECT 28.365 2.99 28.595 4.74 ;
        RECT 26.885 2.99 27.115 4.74 ;
        RECT 25.445 2.99 25.675 4.74 ;
        RECT 23.225 3.23 23.455 4.74 ;
        RECT 21.785 3.23 22.015 4.74 ;
        RECT 17.415 2.99 17.645 4.74 ;
        RECT 15.225 2.99 15.455 4.74 ;
        RECT 13.745 2.99 13.975 4.74 ;
        RECT 12.305 2.99 12.535 4.74 ;
        RECT 10.825 2.99 11.055 4.74 ;
        RECT 9.385 2.99 9.615 4.74 ;
        RECT 7.905 2.99 8.135 4.74 ;
        RECT 6.465 2.99 6.695 4.74 ;
        RECT 4.245 3.23 4.475 4.74 ;
        RECT 2.805 3.23 3.035 4.74 ;
    END
  END VDD
  PIN NCLK
    USE SIGNAL ;
    ANTENNAPARTIALCUTAREA 0.1352 LAYER VIA12 ;
    ANTENNAPARTIALCUTAREA 0.0676 LAYER VIA23 ;
    ANTENNADIFFAREA 0.5152 LAYER METAL1 ;
    ANTENNADIFFAREA 0.5152 LAYER METAL2 ;
    ANTENNADIFFAREA 0.5152 LAYER METAL3 ;
    ANTENNAMODEL OXIDE1 ;
      ANTENNAGATEAREA 0.198 LAYER METAL1 ;
      ANTENNAGATEAREA 0.198 LAYER METAL2 ;
      ANTENNAGATEAREA 0.396 LAYER METAL3 ;
      ANTENNAMAXAREACAR 3.910606 LAYER METAL3 ;
      ANTENNAMAXAREACAR 1.887879 LAYER METAL2 ;
      ANTENNAMAXCUTCAR 0.682828 LAYER VIA12 ;
      ANTENNAMAXCUTCAR 1.024242 LAYER VIA23 ;
    PORT
      LAYER METAL3 ;
        RECT 30.8 2.1 31.25 2.55 ;
        RECT 15.945 2.185 31.25 2.465 ;
        RECT 27.88 2.1 28.33 2.55 ;
        RECT 15.945 2.1 16.395 2.55 ;
      LAYER METAL2 ;
        RECT 30.8 1.66 31.25 2.55 ;
        RECT 27.88 1.66 28.33 2.55 ;
        RECT 15.945 2.1 16.395 2.55 ;
      LAYER POLY1 ;
        RECT 30.815 1.66 31.995 1.84 ;
        RECT 31.815 0.83 31.995 1.84 ;
        RECT 31.67 2.55 31.85 3.83 ;
        RECT 30.815 2.55 31.85 2.73 ;
        RECT 30.815 1.66 31.235 2.73 ;
        RECT 27.895 1.66 29.075 1.84 ;
        RECT 28.895 0.83 29.075 1.84 ;
        RECT 28.75 2.55 28.93 3.83 ;
        RECT 27.895 2.55 28.93 2.73 ;
        RECT 27.895 1.66 28.315 2.73 ;
      LAYER DIFF ;
        RECT 15.88 0.95 16.3 1.37 ;
        RECT 15.78 1.05 16.3 1.27 ;
        RECT 15.79 2.95 16.27 3.61 ;
      LAYER METAL1 ;
        RECT 30.815 1.66 31.235 2.55 ;
        RECT 27.895 1.66 28.315 2.55 ;
        RECT 15.945 0.99 16.395 3.57 ;
      LAYER CONT ;
        RECT 15.95 3.17 16.17 3.39 ;
        RECT 15.98 1.05 16.2 1.27 ;
        RECT 27.995 2.23 28.215 2.45 ;
        RECT 27.995 1.76 28.215 1.98 ;
        RECT 30.915 2.23 31.135 2.45 ;
        RECT 30.915 1.76 31.135 1.98 ;
      LAYER VIA23 ;
        RECT 16.04 2.195 16.3 2.455 ;
        RECT 27.975 2.195 28.235 2.455 ;
        RECT 30.895 2.195 31.155 2.455 ;
      LAYER VIA12 ;
        RECT 16.04 2.195 16.3 2.455 ;
        RECT 27.975 2.235 28.235 2.495 ;
        RECT 27.975 1.715 28.235 1.975 ;
        RECT 30.895 2.235 31.155 2.495 ;
        RECT 30.895 1.715 31.155 1.975 ;
    END
  END NCLK
  PIN D
    DIRECTION INOUT ;
    USE SIGNAL ;
    ANTENNAPARTIALCUTAREA 0.1352 LAYER VIA12 ;
    ANTENNAMODEL OXIDE1 ;
      ANTENNAGATEAREA 0.198 LAYER METAL2 ;
      ANTENNAGATEAREA 0.198 LAYER METAL1 ;
      ANTENNAMAXAREACAR 1.887879 LAYER METAL2 ;
      ANTENNAMAXCUTCAR 0.682828 LAYER VIA12 ;
    PORT
      LAYER METAL2 ;
        RECT 32.99 1.66 33.44 2.55 ;
      LAYER POLY1 ;
        RECT 32.39 2.55 33.425 2.73 ;
        RECT 33.005 1.66 33.425 2.73 ;
        RECT 32.245 1.66 33.425 1.84 ;
        RECT 32.39 2.55 32.57 3.83 ;
        RECT 32.245 0.83 32.425 1.84 ;
      LAYER METAL1 ;
        RECT 33.005 1.66 33.425 2.55 ;
      LAYER CONT ;
        RECT 33.105 2.23 33.325 2.45 ;
        RECT 33.105 1.76 33.325 1.98 ;
      LAYER VIA12 ;
        RECT 33.085 2.235 33.345 2.495 ;
        RECT 33.085 1.715 33.345 1.975 ;
    END
  END D
  PIN Q
    DIRECTION INOUT ;
    USE SIGNAL ;
    ANTENNAPARTIALCUTAREA 0.1352 LAYER VIA12 ;
    ANTENNADIFFAREA 0.7752 LAYER METAL2 ;
    ANTENNADIFFAREA 0.2204 LAYER METAL1 ;
    ANTENNAMODEL OXIDE1 ;
      ANTENNAGATEAREA 0.198 LAYER METAL2 ;
      ANTENNAGATEAREA 0.198 LAYER METAL1 ;
      ANTENNAMAXAREACAR 1.887879 LAYER METAL2 ;
      ANTENNAMAXCUTCAR 0.682828 LAYER VIA12 ;
    PORT
      LAYER METAL2 ;
        RECT 5.98 1.495 6.43 2.55 ;
        RECT 3.875 1.495 6.43 1.775 ;
        RECT 2.415 2.83 4.155 3.11 ;
        RECT 3.875 1.495 4.155 3.11 ;
        RECT 2.33 0.95 2.835 1.33 ;
        RECT 2.33 0.95 2.78 2.47 ;
        RECT 2.415 0.95 2.695 3.11 ;
      LAYER POLY1 ;
        RECT 5.995 1.66 7.175 1.84 ;
        RECT 6.995 0.83 7.175 1.84 ;
        RECT 6.85 2.55 7.03 3.83 ;
        RECT 5.995 2.55 7.03 2.73 ;
        RECT 5.995 1.66 6.415 2.73 ;
      LAYER DIFF ;
        RECT 2.6 1.05 3.22 1.27 ;
        RECT 2.7 0.95 3.12 1.37 ;
        RECT 1.21 2.95 1.75 3.61 ;
        RECT 1.12 0.95 1.54 1.37 ;
        RECT 1.02 1.05 1.54 1.27 ;
      LAYER METAL1 ;
        RECT 5.995 1.66 6.415 2.55 ;
        RECT 2.455 0.99 3.365 1.33 ;
        RECT 2.455 0.95 2.835 1.33 ;
        RECT 1.535 2.24 2.745 2.47 ;
        RECT 2.365 2.09 2.745 2.47 ;
        RECT 1.365 2.99 1.765 3.33 ;
        RECT 1.535 1.595 1.765 3.33 ;
        RECT 1.215 1.595 1.765 1.825 ;
        RECT 1.215 0.99 1.445 1.825 ;
      LAYER CONT ;
        RECT 1.22 1.05 1.44 1.27 ;
        RECT 1.37 3.05 1.59 3.27 ;
        RECT 2.8 1.05 3.02 1.27 ;
        RECT 6.095 2.23 6.315 2.45 ;
        RECT 6.095 1.76 6.315 1.98 ;
      LAYER VIA12 ;
        RECT 2.425 2.15 2.685 2.41 ;
        RECT 2.515 1.01 2.775 1.27 ;
        RECT 6.075 2.235 6.335 2.495 ;
        RECT 6.075 1.715 6.335 1.975 ;
    END
  END Q
  PIN CLK
    DIRECTION INOUT ;
    USE CLOCK ;
    ANTENNAPARTIALCUTAREA 0.1352 LAYER VIA12 ;
    ANTENNAPARTIALCUTAREA 0.0676 LAYER VIA23 ;
    ANTENNAMODEL OXIDE1 ;
      ANTENNAGATEAREA 0.1584 LAYER METAL1 ;
      ANTENNAGATEAREA 0.1584 LAYER METAL2 ;
      ANTENNAGATEAREA 0.5544 LAYER METAL3 ;
      ANTENNAMAXAREACAR 5.539773 LAYER METAL3 ;
      ANTENNAMAXAREACAR 2.769886 LAYER METAL2 ;
      ANTENNAMAXCUTCAR 0.853535 LAYER VIA12 ;
      ANTENNAMAXCUTCAR 1.280303 LAYER VIA23 ;
    PORT
      LAYER METAL3 ;
        RECT 14.775 2.145 15.155 2.525 ;
        RECT 8.9 2.185 15.155 2.465 ;
        RECT 11.82 2.1 12.27 2.55 ;
        RECT 8.9 2.1 9.35 2.55 ;
      LAYER METAL2 ;
        RECT 14.74 1.59 15.19 2.565 ;
        RECT 11.82 1.66 12.27 2.55 ;
        RECT 8.9 1.66 9.35 2.55 ;
      LAYER POLY1 ;
        RECT 15.08 1.49 16.065 2.73 ;
        RECT 15.61 1.49 15.79 3.83 ;
        RECT 15.6 0.83 15.78 2.73 ;
        RECT 14.74 1.595 16.065 2.565 ;
        RECT 11.835 1.66 13.015 1.84 ;
        RECT 12.835 0.83 13.015 1.84 ;
        RECT 12.69 2.55 12.87 3.83 ;
        RECT 11.835 2.55 12.87 2.73 ;
        RECT 11.835 1.66 12.255 2.73 ;
        RECT 8.915 1.66 10.095 1.84 ;
        RECT 9.915 0.83 10.095 1.84 ;
        RECT 9.77 2.55 9.95 3.83 ;
        RECT 8.915 2.55 9.95 2.73 ;
        RECT 8.915 1.66 9.335 2.73 ;
      LAYER METAL1 ;
        RECT 14.74 1.59 15.19 2.565 ;
        RECT 11.835 1.66 12.255 2.55 ;
        RECT 8.915 1.66 9.335 2.55 ;
      LAYER CONT ;
        RECT 9.015 2.23 9.235 2.45 ;
        RECT 9.015 1.76 9.235 1.98 ;
        RECT 11.935 2.23 12.155 2.45 ;
        RECT 11.935 1.76 12.155 1.98 ;
        RECT 14.855 2.225 15.075 2.445 ;
        RECT 14.855 1.705 15.075 1.925 ;
      LAYER VIA23 ;
        RECT 8.995 2.195 9.255 2.455 ;
        RECT 11.915 2.195 12.175 2.455 ;
        RECT 14.835 2.205 15.095 2.465 ;
      LAYER VIA12 ;
        RECT 8.995 2.235 9.255 2.495 ;
        RECT 8.995 1.715 9.255 1.975 ;
        RECT 11.915 2.235 12.175 2.495 ;
        RECT 11.915 1.715 12.175 1.975 ;
        RECT 14.835 2.205 15.095 2.465 ;
        RECT 14.835 1.685 15.095 1.945 ;
    END
  END CLK
  PIN RESET_B
    DIRECTION INOUT ;
    USE SIGNAL ;
    ANTENNAPARTIALCUTAREA 0.1352 LAYER VIA12 ;
    ANTENNAMODEL OXIDE1 ;
      ANTENNAGATEAREA 0.1584 LAYER METAL2 ;
      ANTENNAGATEAREA 0.1584 LAYER METAL1 ;
      ANTENNAMAXAREACAR 2.769886 LAYER METAL2 ;
      ANTENNAMAXCUTCAR 0.853535 LAYER VIA12 ;
    PORT
      LAYER METAL2 ;
        RECT 16.93 1.59 17.38 2.565 ;
      LAYER POLY1 ;
        RECT 17.27 1.49 18.255 2.73 ;
        RECT 17.8 1.49 17.98 3.83 ;
        RECT 17.79 0.83 17.97 2.73 ;
        RECT 16.93 1.595 18.255 2.565 ;
      LAYER METAL1 ;
        RECT 16.93 1.59 17.38 2.565 ;
      LAYER CONT ;
        RECT 17.045 2.225 17.265 2.445 ;
        RECT 17.045 1.705 17.265 1.925 ;
      LAYER VIA12 ;
        RECT 17.025 2.205 17.285 2.465 ;
        RECT 17.025 1.685 17.285 1.945 ;
    END
  END RESET_B
  OBS
    LAYER METAL1 ;
      RECT 32.005 1.09 32.235 3.57 ;
      RECT 31.465 1.09 32.235 2.52 ;
      RECT 31.43 1.09 32.235 1.45 ;
      RECT 29.085 1.09 29.315 3.57 ;
      RECT 28.545 1.09 29.315 2.52 ;
      RECT 28.51 1.09 29.315 1.45 ;
      RECT 26.165 1.09 26.395 3.57 ;
      RECT 26.165 1.09 26.935 2.52 ;
      RECT 26.165 1.09 26.97 1.45 ;
      RECT 20.975 1.56 24.405 1.79 ;
      RECT 24.175 0.99 24.405 1.79 ;
      RECT 22.575 0.99 22.805 1.79 ;
      RECT 20.975 0.99 21.205 1.79 ;
      RECT 19.625 3.56 21.295 3.79 ;
      RECT 21.065 2.77 21.295 3.79 ;
      RECT 23.945 2.77 24.175 3.57 ;
      RECT 22.505 2.77 22.735 3.57 ;
      RECT 19.625 3.23 19.855 3.79 ;
      RECT 21.065 2.77 24.175 3 ;
      RECT 21.435 0.99 22.345 1.33 ;
      RECT 21.435 0.95 21.815 1.33 ;
      RECT 20.345 2.99 20.745 3.33 ;
      RECT 20.515 1.595 20.745 3.33 ;
      RECT 20.515 2.24 21.725 2.47 ;
      RECT 21.345 2.09 21.725 2.47 ;
      RECT 20.195 1.595 20.745 1.825 ;
      RECT 20.195 0.99 20.425 1.825 ;
      RECT 13.025 1.09 13.255 3.57 ;
      RECT 12.485 1.09 13.255 2.52 ;
      RECT 12.45 1.09 13.255 1.45 ;
      RECT 10.105 1.09 10.335 3.57 ;
      RECT 9.565 1.09 10.335 2.52 ;
      RECT 9.53 1.09 10.335 1.45 ;
      RECT 7.185 1.09 7.415 3.57 ;
      RECT 7.185 1.09 7.955 2.52 ;
      RECT 7.185 1.09 7.99 1.45 ;
      RECT 1.995 1.56 5.425 1.79 ;
      RECT 5.195 0.99 5.425 1.79 ;
      RECT 3.595 0.99 3.825 1.79 ;
      RECT 1.995 0.99 2.225 1.79 ;
      RECT 0.645 3.56 2.315 3.79 ;
      RECT 2.085 2.77 2.315 3.79 ;
      RECT 4.965 2.77 5.195 3.57 ;
      RECT 3.525 2.77 3.755 3.57 ;
      RECT 0.645 3.23 0.875 3.79 ;
      RECT 2.085 2.77 5.195 3 ;
      RECT 30.085 1.66 30.505 2.55 ;
      RECT 27.165 1.66 27.585 2.55 ;
      RECT 24.975 1.66 25.395 2.55 ;
      RECT 23.5 2.055 23.95 2.505 ;
      RECT 22.04 2.055 22.49 2.505 ;
      RECT 14.025 1.66 14.445 2.55 ;
      RECT 11.105 1.66 11.525 2.55 ;
      RECT 8.185 1.66 8.605 2.55 ;
      RECT 4.52 2.055 4.97 2.505 ;
      RECT 3.06 2.055 3.51 2.505 ;
    LAYER VIA12 ;
      RECT 31.625 1.7 31.885 1.96 ;
      RECT 31.625 2.22 31.885 2.48 ;
      RECT 30.165 1.715 30.425 1.975 ;
      RECT 30.165 2.235 30.425 2.495 ;
      RECT 28.705 1.7 28.965 1.96 ;
      RECT 28.705 2.22 28.965 2.48 ;
      RECT 27.245 1.715 27.505 1.975 ;
      RECT 27.245 2.235 27.505 2.495 ;
      RECT 26.515 1.7 26.775 1.96 ;
      RECT 26.515 2.22 26.775 2.48 ;
      RECT 25.055 1.715 25.315 1.975 ;
      RECT 25.055 2.235 25.315 2.495 ;
      RECT 23.595 2.15 23.855 2.41 ;
      RECT 22.135 2.15 22.395 2.41 ;
      RECT 21.495 1.01 21.755 1.27 ;
      RECT 21.405 2.15 21.665 2.41 ;
      RECT 14.105 1.715 14.365 1.975 ;
      RECT 14.105 2.235 14.365 2.495 ;
      RECT 12.645 1.7 12.905 1.96 ;
      RECT 12.645 2.22 12.905 2.48 ;
      RECT 11.185 1.715 11.445 1.975 ;
      RECT 11.185 2.235 11.445 2.495 ;
      RECT 9.725 1.7 9.985 1.96 ;
      RECT 9.725 2.22 9.985 2.48 ;
      RECT 8.265 1.715 8.525 1.975 ;
      RECT 8.265 2.235 8.525 2.495 ;
      RECT 7.535 1.7 7.795 1.96 ;
      RECT 7.535 2.22 7.795 2.48 ;
      RECT 4.615 2.15 4.875 2.41 ;
      RECT 3.155 2.15 3.415 2.41 ;
    LAYER METAL2 ;
      RECT 30.07 1.66 30.52 2.55 ;
      RECT 31.53 1.66 31.98 2.52 ;
      RECT 22.04 2.055 22.49 2.505 ;
      RECT 22.125 0.89 22.405 2.505 ;
      RECT 31.615 0.89 31.895 2.52 ;
      RECT 30.155 0.89 30.435 2.55 ;
      RECT 22.125 0.89 31.895 1.215 ;
      RECT 27.235 2.83 28.975 3.155 ;
      RECT 28.695 1.66 28.975 3.155 ;
      RECT 27.235 1.66 27.515 3.155 ;
      RECT 27.15 1.66 27.6 2.55 ;
      RECT 28.61 1.66 29.06 2.52 ;
      RECT 23.585 2.83 26.785 3.11 ;
      RECT 26.505 1.66 26.785 3.11 ;
      RECT 23.585 2.055 23.865 3.11 ;
      RECT 26.42 1.66 26.87 2.52 ;
      RECT 23.5 2.055 23.95 2.505 ;
      RECT 14.095 2.845 23.135 3.125 ;
      RECT 22.855 1.495 23.135 3.125 ;
      RECT 21.395 2.83 23.135 3.125 ;
      RECT 14.095 1.66 14.375 3.125 ;
      RECT 21.395 0.95 21.675 3.125 ;
      RECT 24.96 1.495 25.41 2.55 ;
      RECT 14.01 1.66 14.46 2.55 ;
      RECT 21.31 0.95 21.76 2.47 ;
      RECT 22.855 1.495 25.41 1.775 ;
      RECT 21.31 0.95 21.815 1.33 ;
      RECT 11.09 1.66 11.54 2.55 ;
      RECT 12.55 1.66 13 2.52 ;
      RECT 3.06 2.055 3.51 2.505 ;
      RECT 3.145 0.89 3.425 2.505 ;
      RECT 12.635 0.89 12.915 2.52 ;
      RECT 11.175 0.89 11.455 2.55 ;
      RECT 3.145 0.89 12.915 1.215 ;
      RECT 8.255 2.83 9.995 3.155 ;
      RECT 9.715 1.66 9.995 3.155 ;
      RECT 8.255 1.66 8.535 3.155 ;
      RECT 8.17 1.66 8.62 2.55 ;
      RECT 9.63 1.66 10.08 2.52 ;
      RECT 4.605 2.83 7.805 3.11 ;
      RECT 7.525 1.66 7.805 3.11 ;
      RECT 4.605 2.055 4.885 3.11 ;
      RECT 7.44 1.66 7.89 2.52 ;
      RECT 4.52 2.055 4.97 2.505 ;
  END
END dfrtp_1

MACRO dfsbp_1
  CLASS CORE ;
  ORIGIN 0 -0.35 ;
  FOREIGN dfsbp_1 0 0.35 ;
  SIZE 20.44 BY 4.04 ;
  SYMMETRY X Y ;
  SITE core ;
  PIN VSS
    DIRECTION INOUT ;
    USE GROUND ;
    PORT
      LAYER METAL1 ;
        RECT -0.57 0 21.01 0.7 ;
        RECT 19.365 0 19.595 1.33 ;
        RECT 17.765 0 17.995 1.33 ;
        RECT 15.75 0 15.98 1.33 ;
        RECT 14.15 0 14.38 1.33 ;
        RECT 12.57 0 12.8 1.33 ;
        RECT 11.79 0 12.02 1.33 ;
        RECT 8.9 0 9.13 1.33 ;
        RECT 6.395 0 6.625 1.33 ;
        RECT 3.18 0 3.41 1.33 ;
        RECT 1.245 0 1.475 1.33 ;
    END
  END VSS
  PIN CLK
    DIRECTION INOUT ;
    USE CLOCK ;
    ANTENNAPARTIALCUTAREA 0.0676 LAYER VIA12 ;
    ANTENNAMODEL OXIDE1 ;
      ANTENNAGATEAREA 0.1584 LAYER METAL2 ;
      ANTENNAGATEAREA 0.1584 LAYER METAL1 ;
      ANTENNAMAXAREACAR 1.420455 LAYER METAL2 ;
      ANTENNAMAXCUTCAR 0.426768 LAYER VIA12 ;
    PORT
      LAYER POLY1 ;
        RECT 0.915 2.67 1.095 3.83 ;
        RECT 0.395 1.49 1.05 1.67 ;
        RECT 0.87 0.83 1.05 1.67 ;
        RECT 0.395 2.67 1.095 2.85 ;
        RECT 0.395 1.49 0.575 2.85 ;
        RECT 0.155 2.06 0.575 2.48 ;
      LAYER METAL1 ;
        RECT 0.14 2.02 0.59 2.52 ;
      LAYER METAL2 ;
        RECT 0.14 2.02 0.59 2.52 ;
      LAYER CONT ;
        RECT 0.255 2.16 0.475 2.38 ;
      LAYER VIA12 ;
        RECT 0.235 2.14 0.495 2.4 ;
    END
  END CLK
  PIN VDD
    DIRECTION INOUT ;
    USE POWER ;
    PORT
      LAYER METAL1 ;
        RECT -0.57 4.04 21.01 4.74 ;
        RECT 19.26 2.99 19.49 4.74 ;
        RECT 17.82 3.23 18.05 4.74 ;
        RECT 15.82 2.99 16.05 4.74 ;
        RECT 14.38 3.23 14.61 4.74 ;
        RECT 12.38 3.23 12.61 4.74 ;
        RECT 10.38 3.23 10.61 4.74 ;
        RECT 8.08 3.23 8.31 4.74 ;
        RECT 6.64 3.23 6.87 4.74 ;
        RECT 6.1 3.23 6.87 3.57 ;
        RECT 6.1 3.23 6.33 4.74 ;
        RECT 3.255 3.23 3.485 4.74 ;
        RECT 1.25 3.23 1.48 4.74 ;
    END
  END VDD
  PIN D
    DIRECTION INOUT ;
    USE SIGNAL ;
    ANTENNAPARTIALCUTAREA 0.0676 LAYER VIA12 ;
    ANTENNAMODEL OXIDE1 ;
      ANTENNAGATEAREA 0.1584 LAYER METAL2 ;
      ANTENNAGATEAREA 0.1584 LAYER METAL1 ;
      ANTENNAMAXAREACAR 1.278409 LAYER METAL2 ;
      ANTENNAMAXCUTCAR 0.426768 LAYER VIA12 ;
    PORT
      LAYER POLY1 ;
        RECT 3.64 2.035 3.82 3.83 ;
        RECT 3.605 0.83 3.785 2.455 ;
        RECT 3.365 2.035 3.82 2.455 ;
      LAYER METAL1 ;
        RECT 3.35 2.02 3.8 2.47 ;
      LAYER METAL2 ;
        RECT 3.35 2.02 3.8 2.47 ;
      LAYER CONT ;
        RECT 3.465 2.135 3.685 2.355 ;
      LAYER VIA12 ;
        RECT 3.445 2.115 3.705 2.375 ;
    END
  END D
  PIN SET_B
    DIRECTION INOUT ;
    USE SIGNAL ;
    ANTENNAPARTIALCUTAREA 0.0676 LAYER VIA12 ;
    ANTENNAMODEL OXIDE1 ;
      ANTENNAGATEAREA 0.3168 LAYER METAL2 ;
      ANTENNAGATEAREA 0.1584 LAYER METAL1 ;
      ANTENNAMAXAREACAR 1.641414 LAYER METAL2 ;
      ANTENNAMAXCUTCAR 0.426768 LAYER VIA12 ;
    PORT
      LAYER POLY1 ;
        RECT 12.045 1.575 12.505 1.995 ;
        RECT 12.045 1.49 12.225 3.83 ;
        RECT 11.415 1.49 12.225 1.67 ;
        RECT 11.415 0.83 11.595 1.67 ;
        RECT 6.82 1.4 7.24 1.82 ;
        RECT 7.025 1.4 7.205 3.83 ;
        RECT 6.82 0.83 7 1.82 ;
      LAYER METAL1 ;
        RECT 12.07 1.56 12.52 2.01 ;
        RECT 6.86 1.06 7.24 1.44 ;
        RECT 6.86 1.06 7.2 1.78 ;
      LAYER METAL2 ;
        RECT 12.07 1.56 12.52 2.01 ;
        RECT 12.07 1.16 12.485 2.01 ;
        RECT 6.86 1.16 12.485 1.44 ;
        RECT 6.86 1.06 7.24 1.44 ;
      LAYER CONT ;
        RECT 6.92 1.5 7.14 1.72 ;
        RECT 12.185 1.675 12.405 1.895 ;
      LAYER VIA12 ;
        RECT 6.92 1.12 7.18 1.38 ;
        RECT 12.165 1.655 12.425 1.915 ;
    END
  END SET_B
  PIN Q_N
    DIRECTION INOUT ;
    USE SIGNAL ;
    ANTENNAPARTIALMETALAREA 0.20475 LAYER METAL2 ;
    ANTENNAPARTIALCUTAREA 0.1352 LAYER VIA12 ;
    ANTENNADIFFAREA 0.5768 LAYER METAL2 ;
    ANTENNADIFFAREA 0.5768 LAYER METAL1 ;
    PORT
      LAYER DIFF ;
        RECT 14.945 2.95 15.485 3.61 ;
        RECT 14.755 1.05 15.375 1.27 ;
        RECT 14.855 0.95 15.275 1.37 ;
      LAYER METAL1 ;
        RECT 14.95 2.99 15.33 3.57 ;
        RECT 14.95 0.99 15.18 3.57 ;
        RECT 14.775 2.44 15.18 2.82 ;
        RECT 14.775 1.26 15.18 1.64 ;
      LAYER METAL2 ;
        RECT 14.74 1.22 15.19 1.675 ;
        RECT 14.74 2.4 15.19 2.855 ;
      LAYER CONT ;
        RECT 14.955 1.05 15.175 1.27 ;
        RECT 15.105 3.17 15.325 3.39 ;
      LAYER VIA12 ;
        RECT 14.835 2.5 15.095 2.76 ;
        RECT 14.835 1.32 15.095 1.58 ;
    END
  END Q_N
  PIN Q
    DIRECTION INOUT ;
    USE SIGNAL ;
    ANTENNAPARTIALMETALAREA 0.20925 LAYER METAL2 ;
    ANTENNAPARTIALCUTAREA 0.1352 LAYER VIA12 ;
    ANTENNADIFFAREA 0.5768 LAYER METAL2 ;
    ANTENNADIFFAREA 0.5768 LAYER METAL1 ;
    PORT
      LAYER DIFF ;
        RECT 18.37 1.05 18.99 1.27 ;
        RECT 18.47 0.95 18.89 1.37 ;
        RECT 18.385 2.95 18.925 3.61 ;
      LAYER METAL1 ;
        RECT 18.425 2.44 18.805 2.82 ;
        RECT 18.425 1.26 18.805 1.64 ;
        RECT 18.54 2.44 18.795 3.57 ;
        RECT 18.565 0.99 18.795 3.57 ;
      LAYER METAL2 ;
        RECT 18.39 1.22 18.84 1.685 ;
        RECT 18.39 2.39 18.84 2.855 ;
      LAYER CONT ;
        RECT 18.545 3.17 18.765 3.39 ;
        RECT 18.57 1.05 18.79 1.27 ;
      LAYER VIA12 ;
        RECT 18.485 2.5 18.745 2.76 ;
        RECT 18.485 1.32 18.745 1.58 ;
    END
  END Q
  OBS
    LAYER METAL1 ;
      RECT 17.1 2.77 17.33 3.57 ;
      RECT 17.1 2.77 18.085 3 ;
      RECT 17.855 1.56 18.085 3 ;
      RECT 17.855 1.87 18.335 2.21 ;
      RECT 16.965 1.56 18.085 1.79 ;
      RECT 16.965 0.99 17.195 1.79 ;
      RECT 11.66 2.77 11.89 3.57 ;
      RECT 9.23 2.99 9.46 3.57 ;
      RECT 9.23 2.99 10.15 3.22 ;
      RECT 9.92 2.77 12.87 3 ;
      RECT 12.64 2.24 12.87 3 ;
      RECT 11.61 1.7 11.84 3 ;
      RECT 12.75 1.87 12.98 2.47 ;
      RECT 12.75 1.87 14.72 2.21 ;
      RECT 11.33 1.7 11.84 1.93 ;
      RECT 11.33 1.1 11.56 1.93 ;
      RECT 10.13 1.1 11.56 1.33 ;
      RECT 10.13 0.99 10.36 1.33 ;
      RECT 13.375 0.93 13.875 1.365 ;
      RECT 13.37 0.99 13.875 1.33 ;
      RECT 10.815 2.2 11.38 2.54 ;
      RECT 11 2.16 11.38 2.54 ;
      RECT 8.88 2.31 9.33 2.76 ;
      RECT 9.1 1.56 9.33 2.76 ;
      RECT 10.355 1.56 10.695 1.9 ;
      RECT 9.1 1.56 10.695 1.79 ;
      RECT 7.36 2.77 7.59 3.57 ;
      RECT 6.395 2.77 8.35 3 ;
      RECT 8.12 0.99 8.35 3 ;
      RECT 6.395 2.47 6.735 3 ;
      RECT 4.695 2.99 4.925 3.57 ;
      RECT 4.695 2.99 5.735 3.22 ;
      RECT 5.505 2.24 5.735 3.22 ;
      RECT 6.965 2.31 7.87 2.54 ;
      RECT 7.53 2.2 7.87 2.54 ;
      RECT 5.505 2.24 6.165 2.47 ;
      RECT 5.935 1.1 6.165 2.47 ;
      RECT 6.965 2.01 7.195 2.54 ;
      RECT 5.935 2.01 7.195 2.24 ;
      RECT 4.81 1.1 6.165 1.33 ;
      RECT 4.81 0.99 5.04 1.33 ;
      RECT 4.21 2.42 4.55 2.76 ;
      RECT 4.21 1.72 4.44 2.76 ;
      RECT 5.255 1.56 5.705 2.01 ;
      RECT 4.21 1.72 5.705 1.95 ;
      RECT 3.715 2.99 4.205 3.57 ;
      RECT 3.715 2.7 3.975 3.57 ;
      RECT 2.89 2.7 3.975 2.93 ;
      RECT 2.89 1.56 3.12 2.93 ;
      RECT 2.89 1.56 3.87 1.79 ;
      RECT 3.64 0.99 3.87 1.79 ;
      RECT 3.64 0.99 4.21 1.33 ;
      RECT 1.97 1.55 2.2 3.57 ;
      RECT 2.045 0.99 2.275 2.32 ;
      RECT 1.97 1.55 2.35 1.93 ;
      RECT 0.53 2.77 0.76 3.57 ;
      RECT 0.53 2.77 1.145 3 ;
      RECT 0.87 1.56 1.32 2.77 ;
      RECT 0.445 1.56 1.32 1.79 ;
      RECT 0.445 0.99 0.675 1.79 ;
      RECT 15.41 2.03 17.625 2.37 ;
      RECT 13.1 2.99 13.48 3.57 ;
      RECT 10.97 3.23 11.42 3.81 ;
      RECT 9.56 2.02 10.01 2.47 ;
      RECT 4.825 2.31 5.275 2.76 ;
    LAYER VIA12 ;
      RECT 13.435 1.045 13.695 1.305 ;
      RECT 13.16 3.05 13.42 3.31 ;
      RECT 11.065 3.325 11.325 3.585 ;
      RECT 11.06 2.22 11.32 2.48 ;
      RECT 9.655 2.115 9.915 2.375 ;
      RECT 8.975 2.405 9.235 2.665 ;
      RECT 5.35 1.655 5.61 1.915 ;
      RECT 4.92 2.405 5.18 2.665 ;
      RECT 2.03 1.61 2.29 1.87 ;
      RECT 0.965 2.04 1.225 2.3 ;
    LAYER METAL2 ;
      RECT 11 2.29 11.385 3.645 ;
      RECT 13.1 2.99 13.655 3.37 ;
      RECT 13.375 0.985 13.655 3.37 ;
      RECT 11 2.29 13.655 2.57 ;
      RECT 11 2.16 11.38 3.645 ;
      RECT 13.375 0.985 13.755 1.365 ;
      RECT 9.595 1.72 9.975 2.435 ;
      RECT 6.3 1.72 9.975 2 ;
      RECT 5.29 1.28 5.67 1.975 ;
      RECT 1.97 1.28 2.35 1.93 ;
      RECT 6.3 1.28 6.58 2 ;
      RECT 1.97 1.28 6.58 1.56 ;
      RECT 5.805 3.28 9.22 3.56 ;
      RECT 8.91 2.695 9.22 3.56 ;
      RECT 5.805 2.77 6.085 3.56 ;
      RECT 0.87 2.77 6.085 3.05 ;
      RECT 4.825 2.31 5.275 3.05 ;
      RECT 0.87 1.92 1.32 3.05 ;
      RECT 8.915 2.345 9.295 2.725 ;
  END
  PROPERTY deviceLevel "CatenaDesignType" ;
  PROPERTY CatenaDesignType "deviceLevel" ;
  PROPERTY oaTaper "virtuosoDefaultSetup" ;
END dfsbp_1

MACRO dfxtp_1
  CLASS CORE ;
  ORIGIN 0 -0.35 ;
  FOREIGN dfxtp_1 0 0.35 ;
  SIZE 16.79 BY 4.04 ;
  SYMMETRY X Y ;
  SITE core ;
  PIN VDD
    DIRECTION INOUT ;
    USE POWER ;
    PORT
      LAYER METAL1 ;
        RECT -0.57 4.04 17.36 4.74 ;
        RECT 15.32 3.09 15.55 4.74 ;
        RECT 12.55 3.09 12.78 4.74 ;
        RECT 8.285 3.09 8.515 4.74 ;
        RECT 6.095 3.67 6.33 4.74 ;
        RECT 6.095 3.09 6.325 4.74 ;
        RECT 2.745 3.09 2.975 4.74 ;
        RECT 1.245 3.09 1.475 4.74 ;
    END
  END VDD
  PIN Q
    DIRECTION INOUT ;
    USE SIGNAL ;
    ANTENNAPARTIALCUTAREA 0.1352 LAYER VIA12 ;
    ANTENNADIFFAREA 0.5152 LAYER METAL2 ;
    ANTENNADIFFAREA 0.5152 LAYER METAL1 ;
    PORT
      LAYER DIFF ;
        RECT 16.095 0.94 16.515 1.36 ;
        RECT 15.995 1.04 16.515 1.26 ;
        RECT 15.885 3.05 16.365 3.71 ;
      LAYER METAL1 ;
        RECT 16.04 3.09 16.65 3.67 ;
        RECT 16.27 0.98 16.65 3.67 ;
        RECT 16.19 0.98 16.65 1.32 ;
      LAYER METAL2 ;
        RECT 16.2 1.695 16.65 2.595 ;
      LAYER CONT ;
        RECT 16.045 3.27 16.265 3.49 ;
        RECT 16.195 1.04 16.415 1.26 ;
      LAYER VIA12 ;
        RECT 16.33 2.275 16.59 2.535 ;
        RECT 16.33 1.755 16.59 2.015 ;
    END
  END Q
  PIN VSS
    DIRECTION INOUT ;
    USE GROUND ;
    PORT
      LAYER METAL1 ;
        RECT -0.57 0 17.36 0.7 ;
        RECT 15.39 0 15.62 1.32 ;
        RECT 13.89 0 14.12 1.32 ;
        RECT 9.04 0 9.27 1.32 ;
        RECT 2.705 0 2.935 1.32 ;
        RECT 1.205 0 1.435 1.32 ;
    END
  END VSS
  PIN CLK
    DIRECTION INOUT ;
    USE CLOCK ;
    ANTENNAPARTIALCUTAREA 0.0676 LAYER VIA12 ;
    ANTENNAMODEL OXIDE1 ;
      ANTENNAGATEAREA 0.1584 LAYER METAL2 ;
      ANTENNAGATEAREA 0.1584 LAYER METAL1 ;
      ANTENNAMAXAREACAR 1.278409 LAYER METAL2 ;
      ANTENNAMAXCUTCAR 0.426768 LAYER VIA12 ;
    PORT
      LAYER POLY1 ;
        RECT 0.91 2.77 1.09 3.93 ;
        RECT 0.83 0.82 1.01 1.64 ;
        RECT 0.155 2.77 1.09 2.95 ;
        RECT 0.155 1.46 1.01 1.64 ;
        RECT 0.14 1.625 0.59 2.075 ;
        RECT 0.155 1.46 0.335 2.95 ;
      LAYER METAL1 ;
        RECT 0.14 1.625 0.59 2.075 ;
      LAYER METAL2 ;
        RECT 0.14 1.625 0.59 2.075 ;
      LAYER CONT ;
        RECT 0.255 1.74 0.475 1.96 ;
      LAYER VIA12 ;
        RECT 0.235 1.72 0.495 1.98 ;
    END
  END CLK
  PIN D
    DIRECTION INOUT ;
    USE SIGNAL ;
    ANTENNAPARTIALCUTAREA 0.0676 LAYER VIA12 ;
    ANTENNAMODEL OXIDE1 ;
      ANTENNAGATEAREA 0.1584 LAYER METAL2 ;
      ANTENNAGATEAREA 0.1584 LAYER METAL1 ;
      ANTENNAMAXAREACAR 2.698864 LAYER METAL2 ;
      ANTENNAMAXCUTCAR 0.426768 LAYER VIA12 ;
    PORT
      LAYER POLY1 ;
        RECT 3.13 0.82 3.31 3.93 ;
        RECT 2.33 2.11 3.31 2.62 ;
      LAYER METAL1 ;
        RECT 2.525 1.61 2.975 2.56 ;
      LAYER METAL2 ;
        RECT 2.33 2.145 2.94 2.525 ;
        RECT 2.33 2.11 2.78 3.025 ;
      LAYER CONT ;
        RECT 2.64 2.225 2.86 2.445 ;
      LAYER VIA12 ;
        RECT 2.62 2.205 2.88 2.465 ;
    END
  END D
  OBS
    LAYER METAL1 ;
      RECT 15.615 1.55 15.955 1.89 ;
      RECT 13.635 1.55 13.975 1.89 ;
      RECT 13.635 1.55 15.955 1.78 ;
      RECT 14.59 0.98 14.82 1.78 ;
      RECT 9.725 3.09 11.63 3.67 ;
      RECT 11.105 0.98 11.335 3.67 ;
      RECT 14.815 2.12 15.155 2.79 ;
      RECT 12.405 2.22 15.155 2.45 ;
      RECT 11.105 2.06 12.635 2.29 ;
      RECT 11.105 0.98 11.34 1.32 ;
      RECT 13.325 3.09 14.83 3.67 ;
      RECT 13.325 2.87 13.665 3.67 ;
      RECT 9.005 3.09 9.495 3.67 ;
      RECT 9.265 2.63 9.495 3.67 ;
      RECT 7.825 2.63 9.565 2.86 ;
      RECT 9.335 1.61 9.565 2.86 ;
      RECT 7.825 2.52 8.165 2.86 ;
      RECT 9.335 1.61 10.07 1.84 ;
      RECT 9.84 0.98 10.07 1.84 ;
      RECT 9.84 0.98 10.54 1.32 ;
      RECT 4.185 3.09 4.535 3.67 ;
      RECT 4.305 0.98 4.535 3.67 ;
      RECT 5.635 2.275 7.595 2.505 ;
      RECT 7.365 1.765 7.595 2.505 ;
      RECT 4.78 2.06 5.865 2.29 ;
      RECT 8.71 1.765 9.05 2.27 ;
      RECT 4.78 0.98 5.01 2.29 ;
      RECT 7.365 1.765 9.05 2.01 ;
      RECT 4.305 0.98 5.01 1.21 ;
      RECT 8.24 0.98 8.47 1.32 ;
      RECT 5.58 0.98 5.81 1.32 ;
      RECT 5.58 0.98 8.47 1.21 ;
      RECT 4.905 3.44 5.605 3.67 ;
      RECT 5.375 3.09 5.605 3.67 ;
      RECT 4.905 3.09 5.135 3.67 ;
      RECT 3.205 3.09 3.695 3.67 ;
      RECT 3.205 0.98 3.435 3.67 ;
      RECT 3.205 0.98 3.735 1.32 ;
      RECT 1.855 3.43 2.235 3.81 ;
      RECT 2.005 0.98 2.235 3.81 ;
      RECT 1.965 3.09 2.235 3.81 ;
      RECT 0.525 2.305 0.755 3.67 ;
      RECT 0.525 2.305 1.61 2.535 ;
      RECT 1.23 1.83 1.61 2.535 ;
      RECT 12.865 1.55 13.405 1.965 ;
      RECT 11.91 0.98 13.32 1.32 ;
      RECT 11.565 2.52 12.175 2.86 ;
      RECT 10.495 1.55 10.875 2.165 ;
      RECT 9.935 2.52 10.765 2.86 ;
      RECT 6.095 1.55 7.04 1.89 ;
      RECT 4.765 2.52 5.405 2.86 ;
      RECT 3.69 1.55 4.07 2.085 ;
      RECT 3.665 2.325 4.045 2.86 ;
      RECT 0.22 0.98 0.975 1.32 ;
    LAYER VIA12 ;
      RECT 12.925 1.59 13.185 1.85 ;
      RECT 11.625 2.56 11.885 2.82 ;
      RECT 10.555 1.59 10.815 1.85 ;
      RECT 9.995 2.56 10.255 2.82 ;
      RECT 6.28 1.59 6.54 1.85 ;
      RECT 4.97 2.56 5.23 2.82 ;
      RECT 3.75 1.59 4.01 1.85 ;
      RECT 3.725 2.56 3.985 2.82 ;
      RECT 1.915 3.49 2.175 3.75 ;
      RECT 1.29 1.87 1.55 2.13 ;
      RECT 0.655 1.02 0.915 1.28 ;
    LAYER METAL2 ;
      RECT 4.35 2.86 10.315 3.14 ;
      RECT 9.935 2.52 10.315 3.14 ;
      RECT 4.35 2.52 5.29 3.14 ;
      RECT 4.35 0.7 4.63 3.14 ;
      RECT 1.23 1.55 1.61 2.17 ;
      RECT 12.655 1.53 13.225 1.91 ;
      RECT 3.69 1.55 4.07 1.89 ;
      RECT 3.79 0.7 4.07 1.89 ;
      RECT 1.23 1.55 4.07 1.83 ;
      RECT 1.23 0.98 1.51 2.17 ;
      RECT 12.655 0.7 12.995 1.91 ;
      RECT 0.595 0.98 1.51 1.32 ;
      RECT 3.79 0.7 12.995 0.98 ;
      RECT 1.855 3.76 11.925 4.04 ;
      RECT 11.585 2.5 11.925 4.04 ;
      RECT 10.595 1.26 10.875 4.04 ;
      RECT 3.345 2.5 3.685 4.04 ;
      RECT 1.855 3.43 2.235 4.04 ;
      RECT 3.345 2.5 4.025 2.88 ;
      RECT 10.495 1.26 10.875 1.89 ;
      RECT 6.22 1.26 6.6 1.89 ;
      RECT 6.22 1.26 10.875 1.54 ;
  END
  PROPERTY deviceLevel "CatenaDesignType" ;
  PROPERTY CatenaDesignType "deviceLevel" ;
END dfxtp_1

MACRO dlxbp_1
  CLASS CORE ;
  ORIGIN 0 -0.35 ;
  FOREIGN dlxbp_1 0 0.35 ;
  SIZE 16.06 BY 4.04 ;
  SYMMETRY X Y ;
  SITE core ;
  PIN VSS
    DIRECTION INOUT ;
    USE GROUND ;
    PORT
      LAYER METAL1 ;
        RECT -0.57 0 16.63 0.7 ;
        RECT 15.3 0 15.53 1.33 ;
        RECT 13.7 0 13.93 1.33 ;
        RECT 11.495 0 11.725 1.33 ;
        RECT 9.895 0 10.125 1.33 ;
        RECT 8.315 0 8.545 1.33 ;
        RECT 4.335 0 4.565 1.33 ;
        RECT 1.955 0 2.185 1.33 ;
    END
  END VSS
  PIN VDD
    DIRECTION INOUT ;
    USE POWER ;
    PORT
      LAYER METAL1 ;
        RECT -0.57 4.04 16.63 4.74 ;
        RECT 15.155 2.99 15.385 4.74 ;
        RECT 13.715 2.99 13.945 4.74 ;
        RECT 11.715 2.99 11.945 4.74 ;
        RECT 10.275 2.99 10.505 4.74 ;
        RECT 8.275 2.99 8.505 4.74 ;
        RECT 4.115 2.99 4.345 4.74 ;
        RECT 1.395 3.23 1.625 4.74 ;
    END
  END VDD
  PIN Q_N
    DIRECTION INOUT ;
    USE SIGNAL ;
    ANTENNAPARTIALCUTAREA 0.1352 LAYER VIA12 ;
    ANTENNADIFFAREA 0.5768 LAYER METAL2 ;
    ANTENNADIFFAREA 0.5768 LAYER METAL1 ;
    PORT
      LAYER DIFF ;
        RECT 14.305 1.05 14.925 1.27 ;
        RECT 14.405 0.95 14.825 1.37 ;
        RECT 14.28 2.95 14.82 3.61 ;
      LAYER METAL1 ;
        RECT 14.665 1.83 15.155 2.73 ;
        RECT 14.435 2.99 14.925 3.57 ;
        RECT 14.665 0.99 14.925 3.57 ;
        RECT 14.5 0.99 14.925 1.33 ;
      LAYER METAL2 ;
        RECT 14.74 1.83 15.19 2.73 ;
      LAYER CONT ;
        RECT 14.44 3.17 14.66 3.39 ;
        RECT 14.505 1.05 14.725 1.27 ;
      LAYER VIA12 ;
        RECT 14.835 2.41 15.095 2.67 ;
        RECT 14.835 1.89 15.095 2.15 ;
    END
  END Q_N
  PIN D
    DIRECTION INOUT ;
    USE SIGNAL ;
    ANTENNAPARTIALCUTAREA 0.0676 LAYER VIA12 ;
    ANTENNAMODEL OXIDE1 ;
      ANTENNAGATEAREA 0.1584 LAYER METAL2 ;
      ANTENNAGATEAREA 0.1584 LAYER METAL1 ;
      ANTENNAMAXAREACAR 1.278409 LAYER METAL2 ;
      ANTENNAMAXCUTCAR 0.426768 LAYER VIA12 ;
    PORT
      LAYER POLY1 ;
        RECT 3.78 2.035 4.225 2.455 ;
        RECT 3.96 0.83 4.14 1.67 ;
        RECT 3.78 1.49 3.96 3.83 ;
      LAYER METAL1 ;
        RECT 3.79 2.02 4.24 2.47 ;
      LAYER METAL2 ;
        RECT 3.79 2.02 4.24 2.47 ;
      LAYER CONT ;
        RECT 3.905 2.135 4.125 2.355 ;
      LAYER VIA12 ;
        RECT 3.885 2.115 4.145 2.375 ;
    END
  END D
  PIN Q
    DIRECTION INOUT ;
    USE SIGNAL ;
    ANTENNAPARTIALCUTAREA 0.1352 LAYER VIA12 ;
    ANTENNADIFFAREA 0.5768 LAYER METAL2 ;
    ANTENNADIFFAREA 0.5768 LAYER METAL1 ;
    PORT
      LAYER DIFF ;
        RECT 10.84 2.95 11.38 3.61 ;
        RECT 10.5 1.05 11.12 1.27 ;
        RECT 10.6 0.95 11.02 1.37 ;
      LAYER METAL1 ;
        RECT 10.995 1.83 11.505 2.73 ;
        RECT 10.995 0.99 11.225 3.57 ;
        RECT 10.695 0.99 11.225 1.33 ;
      LAYER METAL2 ;
        RECT 11.09 1.83 11.54 2.73 ;
      LAYER CONT ;
        RECT 10.7 1.05 10.92 1.27 ;
        RECT 11 3.17 11.22 3.39 ;
      LAYER VIA12 ;
        RECT 11.185 2.41 11.445 2.67 ;
        RECT 11.185 1.89 11.445 2.15 ;
    END
  END Q
  PIN GATE
    DIRECTION INOUT ;
    USE SIGNAL ;
    ANTENNAPARTIALCUTAREA 0.0676 LAYER VIA12 ;
    ANTENNAMODEL OXIDE1 ;
      ANTENNAGATEAREA 0.1584 LAYER METAL2 ;
      ANTENNAGATEAREA 0.1584 LAYER METAL1 ;
      ANTENNAMAXAREACAR 1.278409 LAYER METAL2 ;
      ANTENNAMAXCUTCAR 0.426768 LAYER VIA12 ;
    PORT
      LAYER POLY1 ;
        RECT 1.06 1.49 1.76 1.67 ;
        RECT 1.58 0.83 1.76 1.67 ;
        RECT 0.885 2.07 1.305 2.49 ;
        RECT 1.06 1.49 1.24 3.83 ;
      LAYER METAL1 ;
        RECT 0.87 2.055 1.32 2.505 ;
      LAYER METAL2 ;
        RECT 0.87 2.055 1.32 2.52 ;
      LAYER CONT ;
        RECT 0.985 2.17 1.205 2.39 ;
      LAYER VIA12 ;
        RECT 0.965 2.15 1.225 2.41 ;
    END
  END GATE
  OBS
    LAYER METAL1 ;
      RECT 12.9 0.99 13.225 3.57 ;
      RECT 12.9 2.11 14.405 2.45 ;
      RECT 9.19 2.99 9.785 3.57 ;
      RECT 9.19 0.99 9.42 3.57 ;
      RECT 8.225 2.34 10.755 2.57 ;
      RECT 10.415 2.11 10.755 2.57 ;
      RECT 8.225 2.23 8.565 2.57 ;
      RECT 9.095 0.99 9.42 1.33 ;
      RECT 6.835 2.99 7.065 3.57 ;
      RECT 5.555 2.99 5.785 3.57 ;
      RECT 5.555 2.99 7.62 3.22 ;
      RECT 7.39 1.1 7.62 3.22 ;
      RECT 8.62 1.56 8.96 1.9 ;
      RECT 7.39 1.56 8.96 1.79 ;
      RECT 5.935 1.1 7.62 1.33 ;
      RECT 6.715 0.99 6.945 1.33 ;
      RECT 5.935 0.99 6.165 1.33 ;
      RECT 6.71 2.31 7.16 2.76 ;
      RECT 6.71 1.67 6.94 2.76 ;
      RECT 5.595 1.67 6.94 1.9 ;
      RECT 5.595 1.56 5.935 1.9 ;
      RECT 3.33 2.99 3.625 3.57 ;
      RECT 3.33 0.99 3.56 3.57 ;
      RECT 4.56 1.56 4.9 1.9 ;
      RECT 3.33 1.56 4.9 1.79 ;
      RECT 3.33 0.99 3.765 1.33 ;
      RECT 2.365 2.985 2.745 3.69 ;
      RECT 2.115 2.985 2.985 3.57 ;
      RECT 2.745 0.99 2.985 3.57 ;
      RECT 0.675 2.77 0.905 3.57 ;
      RECT 0.675 2.77 1.83 3 ;
      RECT 1.6 1.56 1.83 3 ;
      RECT 1.6 2.055 2.05 2.505 ;
      RECT 1.155 1.56 1.83 1.79 ;
      RECT 1.155 0.99 1.385 1.79 ;
      RECT 5.205 2.31 5.655 2.76 ;
    LAYER VIA12 ;
      RECT 6.805 2.405 7.065 2.665 ;
      RECT 5.3 2.405 5.56 2.665 ;
      RECT 2.425 3.37 2.685 3.63 ;
      RECT 1.695 2.15 1.955 2.41 ;
    LAYER METAL2 ;
      RECT 2.365 3.31 2.78 3.69 ;
      RECT 2.365 3.31 7.125 3.59 ;
      RECT 6.845 2.345 7.125 3.59 ;
      RECT 6.745 2.345 7.125 2.725 ;
      RECT 2.36 2.75 5.62 3.03 ;
      RECT 5.24 2.345 5.62 3.03 ;
      RECT 2.36 2.24 2.64 3.03 ;
      RECT 1.6 2.24 2.64 2.52 ;
      RECT 1.6 2.055 2.05 2.52 ;
  END
END dlxbp_1

MACRO inv_1
  CLASS CORE ;
  ORIGIN 0 -0.35 ;
  FOREIGN inv_1 0 0.35 ;
  SIZE 2.19 BY 4.04 ;
  SYMMETRY X Y ;
  SITE core ;
  PIN Y
    DIRECTION INOUT ;
    USE SIGNAL ;
    ANTENNAPARTIALCUTAREA 0.0676 LAYER VIA12 ;
    ANTENNADIFFAREA 0.5152 LAYER METAL2 ;
    ANTENNADIFFAREA 0.1984 LAYER METAL1 ;
    PORT
      LAYER DIFF ;
        RECT 1.28 0.95 1.7 1.37 ;
        RECT 1.18 1.05 1.7 1.27 ;
        RECT 1.19 2.95 1.67 3.61 ;
      LAYER METAL1 ;
        RECT 1.375 0.99 2.05 1.44 ;
        RECT 1.345 2.99 2.05 3.57 ;
      LAYER METAL2 ;
        RECT 1.6 0.99 2.05 3.57 ;
      LAYER CONT ;
        RECT 1.35 3.17 1.57 3.39 ;
        RECT 1.38 1.05 1.6 1.27 ;
      LAYER VIA12 ;
        RECT 1.695 3.15 1.955 3.41 ;
        RECT 1.695 1.085 1.955 1.345 ;
    END
  END Y
  PIN VSS
    DIRECTION INOUT ;
    USE GROUND ;
    PORT
      LAYER METAL1 ;
        RECT -0.57 0 2.76 0.7 ;
        RECT 0.575 0 0.805 1.33 ;
    END
  END VSS
  PIN A
    DIRECTION INOUT ;
    USE SIGNAL ;
    ANTENNAPARTIALCUTAREA 0.1352 LAYER VIA12 ;
    ANTENNAMODEL OXIDE1 ;
      ANTENNAGATEAREA 0.1584 LAYER METAL2 ;
      ANTENNAGATEAREA 0.1584 LAYER METAL1 ;
      ANTENNAMAXAREACAR 2.769886 LAYER METAL2 ;
      ANTENNAMAXCUTCAR 0.853535 LAYER VIA12 ;
    PORT
      LAYER POLY1 ;
        RECT 0.48 1.49 1.465 2.73 ;
        RECT 1.01 1.49 1.19 3.83 ;
        RECT 1 0.83 1.18 2.73 ;
        RECT 0.14 1.595 1.465 2.565 ;
      LAYER METAL1 ;
        RECT 0.14 1.59 0.59 2.565 ;
      LAYER METAL2 ;
        RECT 0.14 1.59 0.59 2.565 ;
      LAYER CONT ;
        RECT 0.255 2.225 0.475 2.445 ;
        RECT 0.255 1.705 0.475 1.925 ;
      LAYER VIA12 ;
        RECT 0.235 2.205 0.495 2.465 ;
        RECT 0.235 1.685 0.495 1.945 ;
    END
  END A
  PIN VDD
    DIRECTION INOUT ;
    USE POWER ;
    PORT
      LAYER METAL1 ;
        RECT -0.57 4.04 2.76 4.74 ;
        RECT 0.625 2.99 0.855 4.74 ;
    END
  END VDD
END inv_1

MACRO inv_16
  CLASS CORE ;
  ORIGIN 0 -0.35 ;
  FOREIGN inv_16 0 0.35 ;
  SIZE 13.87 BY 4.04 ;
  SYMMETRY X Y ;
  SITE core ;
  PIN A
    DIRECTION INOUT ;
    USE SIGNAL ;
    ANTENNAPARTIALMETALAREA 0.405 LAYER METAL2 ;
    ANTENNAPARTIALCUTAREA 0.2028 LAYER VIA12 ;
    ANTENNAMODEL OXIDE1 ;
      ANTENNAGATEAREA 2.5344 LAYER METAL2 ;
      ANTENNAGATEAREA 2.5344 LAYER METAL1 ;
      ANTENNAMAXAREACAR 2.051669 LAYER METAL2 ;
      ANTENNAMAXCUTCAR 0.080019 LAYER VIA12 ;
    PORT
      LAYER POLY1 ;
        RECT 0.81 1.81 12.99 2.41 ;
        RECT 12.81 0.83 12.99 2.41 ;
        RECT 12.195 1.81 12.375 3.83 ;
        RECT 12.01 0.83 12.19 2.41 ;
        RECT 11.475 1.81 11.655 3.83 ;
        RECT 0.81 1.81 11.655 2.505 ;
        RECT 11.21 0.83 11.39 2.505 ;
        RECT 10.755 1.81 10.935 3.83 ;
        RECT 10.41 0.83 10.59 2.505 ;
        RECT 10.035 1.81 10.215 3.83 ;
        RECT 8.595 1.81 10.215 2.73 ;
        RECT 9.61 0.83 9.79 2.73 ;
        RECT 9.315 1.81 9.495 3.83 ;
        RECT 8.81 0.83 8.99 2.73 ;
        RECT 8.595 1.81 8.775 3.83 ;
        RECT 8.01 0.83 8.19 2.505 ;
        RECT 7.875 1.81 8.055 3.83 ;
        RECT 7.21 0.83 7.39 2.505 ;
        RECT 7.155 1.81 7.335 3.83 ;
        RECT 6.435 1.81 6.615 3.83 ;
        RECT 6.41 0.83 6.59 2.505 ;
        RECT 5.715 1.81 5.895 3.83 ;
        RECT 5.61 0.83 5.79 2.73 ;
        RECT 4.995 1.81 5.895 2.73 ;
        RECT 4.995 1.81 5.175 3.83 ;
        RECT 4.81 0.83 4.99 2.505 ;
        RECT 4.275 1.81 4.455 3.83 ;
        RECT 4.01 0.83 4.19 2.505 ;
        RECT 3.555 1.81 3.735 3.83 ;
        RECT 3.21 0.83 3.39 2.505 ;
        RECT 2.835 1.81 3.015 3.83 ;
        RECT 2.41 0.83 2.59 2.505 ;
        RECT 2.115 1.81 2.295 3.83 ;
        RECT 1.61 0.83 1.79 2.505 ;
        RECT 1.395 1.81 1.575 3.83 ;
        RECT 0.81 1.81 1.575 2.73 ;
        RECT 0.81 0.83 0.99 2.73 ;
      LAYER METAL1 ;
        RECT 0.87 2.055 11.525 2.505 ;
      LAYER METAL2 ;
        RECT 9.63 2.055 10.08 2.505 ;
        RECT 8.9 2.055 9.35 2.505 ;
        RECT 0.87 2.055 1.32 2.505 ;
      LAYER CONT ;
        RECT 0.985 2.17 1.205 2.39 ;
        RECT 1.715 2.17 1.935 2.39 ;
        RECT 2.445 2.17 2.665 2.39 ;
        RECT 3.175 2.17 3.395 2.39 ;
        RECT 3.905 2.17 4.125 2.39 ;
        RECT 4.635 2.17 4.855 2.39 ;
        RECT 5.365 2.17 5.585 2.39 ;
        RECT 6.095 2.17 6.315 2.39 ;
        RECT 6.825 2.17 7.045 2.39 ;
        RECT 7.555 2.17 7.775 2.39 ;
        RECT 8.285 2.17 8.505 2.39 ;
        RECT 9.015 2.17 9.235 2.39 ;
        RECT 9.745 2.17 9.965 2.39 ;
        RECT 10.475 2.17 10.695 2.39 ;
        RECT 11.205 2.17 11.425 2.39 ;
      LAYER VIA12 ;
        RECT 0.965 2.15 1.225 2.41 ;
        RECT 8.995 2.15 9.255 2.41 ;
        RECT 9.725 2.15 9.985 2.41 ;
    END
  END A
  PIN Y
    DIRECTION INOUT ;
    USE SIGNAL ;
    ANTENNAPARTIALCUTAREA 0.2028 LAYER VIA12 ;
    ANTENNADIFFAREA 4.6144 LAYER METAL2 ;
    ANTENNADIFFAREA 4.6144 LAYER METAL1 ;
    PORT
      LAYER DIFF ;
        RECT 12.19 1.05 12.81 1.27 ;
        RECT 12.29 0.95 12.71 1.37 ;
        RECT 11.655 2.95 12.195 3.61 ;
        RECT 10.59 1.05 11.21 1.27 ;
        RECT 10.69 0.95 11.11 1.37 ;
        RECT 10.215 2.95 10.755 3.61 ;
        RECT 8.99 1.05 9.61 1.27 ;
        RECT 9.09 0.95 9.51 1.37 ;
        RECT 8.775 2.95 9.315 3.61 ;
        RECT 7.39 1.05 8.01 1.27 ;
        RECT 7.49 0.95 7.91 1.37 ;
        RECT 7.335 2.95 7.875 3.61 ;
        RECT 5.895 2.95 6.435 3.61 ;
        RECT 5.79 1.05 6.41 1.27 ;
        RECT 5.89 0.95 6.31 1.37 ;
        RECT 4.455 2.95 4.995 3.61 ;
        RECT 4.19 1.05 4.81 1.27 ;
        RECT 4.29 0.95 4.71 1.37 ;
        RECT 3.015 2.95 3.555 3.61 ;
        RECT 2.59 1.05 3.21 1.27 ;
        RECT 2.69 0.95 3.11 1.37 ;
        RECT 1.575 2.95 2.115 3.61 ;
        RECT 0.99 1.05 1.61 1.27 ;
        RECT 1.09 0.95 1.51 1.37 ;
      LAYER METAL1 ;
        RECT 1.185 1.56 12.615 1.79 ;
        RECT 12.385 0.99 12.615 1.79 ;
        RECT 1.73 2.77 12.27 3 ;
        RECT 11.82 1.56 12.27 3 ;
        RECT 11.81 2.77 12.04 3.33 ;
        RECT 10.785 0.99 11.015 1.79 ;
        RECT 10.37 2.77 10.6 3.33 ;
        RECT 9.185 0.99 9.415 1.79 ;
        RECT 8.93 2.77 9.16 3.33 ;
        RECT 7.585 0.99 7.815 1.79 ;
        RECT 7.49 2.77 7.72 3.33 ;
        RECT 6.05 2.77 6.28 3.33 ;
        RECT 5.985 0.99 6.215 1.79 ;
        RECT 4.61 2.77 4.84 3.33 ;
        RECT 4.385 0.99 4.615 1.79 ;
        RECT 3.17 2.77 3.4 3.33 ;
        RECT 2.785 0.99 3.015 1.79 ;
        RECT 1.73 2.77 1.96 3.33 ;
        RECT 1.185 0.99 1.415 1.79 ;
      LAYER METAL2 ;
        RECT 11.82 1.56 12.27 3 ;
      LAYER CONT ;
        RECT 1.19 1.05 1.41 1.27 ;
        RECT 1.735 3.05 1.955 3.27 ;
        RECT 2.79 1.05 3.01 1.27 ;
        RECT 3.175 3.05 3.395 3.27 ;
        RECT 4.39 1.05 4.61 1.27 ;
        RECT 4.615 3.05 4.835 3.27 ;
        RECT 5.99 1.05 6.21 1.27 ;
        RECT 6.055 3.05 6.275 3.27 ;
        RECT 7.495 3.05 7.715 3.27 ;
        RECT 7.59 1.05 7.81 1.27 ;
        RECT 8.935 3.05 9.155 3.27 ;
        RECT 9.19 1.05 9.41 1.27 ;
        RECT 10.375 3.05 10.595 3.27 ;
        RECT 10.79 1.05 11.01 1.27 ;
        RECT 11.815 3.05 12.035 3.27 ;
        RECT 12.39 1.05 12.61 1.27 ;
      LAYER VIA12 ;
        RECT 11.915 2.67 12.175 2.93 ;
        RECT 11.915 2.15 12.175 2.41 ;
        RECT 11.915 1.63 12.175 1.89 ;
    END
  END Y
  PIN VDD
    DIRECTION INOUT ;
    USE POWER ;
    PORT
      LAYER METAL1 ;
        RECT -0.57 4.04 14.44 4.74 ;
        RECT 12.53 3.23 12.76 4.74 ;
        RECT 11.09 3.23 11.32 4.74 ;
        RECT 9.65 3.23 9.88 4.74 ;
        RECT 8.21 3.23 8.44 4.74 ;
        RECT 6.77 3.23 7 4.74 ;
        RECT 5.33 3.23 5.56 4.74 ;
        RECT 3.89 3.23 4.12 4.74 ;
        RECT 2.45 3.23 2.68 4.74 ;
        RECT 1.01 3.23 1.24 4.74 ;
    END
  END VDD
  PIN VSS
    DIRECTION INOUT ;
    USE GROUND ;
    PORT
      LAYER METAL1 ;
        RECT -0.57 0 14.44 0.7 ;
        RECT 13.185 0 13.415 1.33 ;
        RECT 11.585 0 11.815 1.33 ;
        RECT 9.985 0 10.215 1.33 ;
        RECT 8.385 0 8.615 1.33 ;
        RECT 6.785 0 7.015 1.33 ;
        RECT 5.185 0 5.415 1.33 ;
        RECT 3.585 0 3.815 1.33 ;
        RECT 1.985 0 2.215 1.33 ;
        RECT 0.385 0 0.615 1.33 ;
    END
  END VSS
END inv_16

MACRO inv_2
  CLASS CORE ;
  ORIGIN 0 -0.35 ;
  FOREIGN inv_2 0 0.35 ;
  SIZE 2.92 BY 4.04 ;
  SYMMETRY X Y ;
  SITE core ;
  PIN Y
    DIRECTION INOUT ;
    USE SIGNAL ;
    ANTENNAPARTIALMETALAREA 0.405 LAYER METAL2 ;
    ANTENNAPARTIALCUTAREA 0.2704 LAYER VIA12 ;
    ANTENNADIFFAREA 0.5768 LAYER METAL2 ;
    ANTENNADIFFAREA 0.5768 LAYER METAL1 ;
    PORT
      LAYER DIFF ;
        RECT 1.165 1.05 1.785 1.27 ;
        RECT 1.265 0.95 1.685 1.37 ;
        RECT 1.2 2.95 1.74 3.61 ;
      LAYER METAL1 ;
        RECT 1.6 1.62 2.745 2.52 ;
        RECT 1.6 1.62 2.05 2.615 ;
        RECT 1.36 1.33 1.93 1.705 ;
        RECT 1.355 2.615 1.845 2.99 ;
        RECT 1.36 0.99 1.59 1.705 ;
        RECT 1.355 2.615 1.585 3.57 ;
      LAYER METAL2 ;
        RECT 2.33 1.62 2.78 2.52 ;
        RECT 1.6 1.62 2.05 2.52 ;
      LAYER CONT ;
        RECT 1.36 3.17 1.58 3.39 ;
        RECT 1.365 1.05 1.585 1.27 ;
      LAYER VIA12 ;
        RECT 1.695 2.2 1.955 2.46 ;
        RECT 1.695 1.68 1.955 1.94 ;
        RECT 2.425 2.2 2.685 2.46 ;
        RECT 2.425 1.68 2.685 1.94 ;
    END
  END Y
  PIN VSS
    DIRECTION INOUT ;
    USE GROUND ;
    PORT
      LAYER METAL1 ;
        RECT -0.57 0 3.49 0.7 ;
        RECT 2.16 0 2.39 1.33 ;
        RECT 0.56 0 0.79 1.33 ;
    END
  END VSS
  PIN A
    DIRECTION INOUT ;
    USE SIGNAL ;
    ANTENNAPARTIALMETALAREA 0.2025 LAYER METAL2 ;
    ANTENNAPARTIALCUTAREA 0.1352 LAYER VIA12 ;
    ANTENNAMODEL OXIDE1 ;
      ANTENNAGATEAREA 0.3168 LAYER METAL2 ;
      ANTENNAGATEAREA 0.3168 LAYER METAL1 ;
      ANTENNAMAXAREACAR 2.315341 LAYER METAL2 ;
      ANTENNAMAXCUTCAR 0.426768 LAYER VIA12 ;
    PORT
      LAYER POLY1 ;
        RECT 0.14 1.81 1.965 2.41 ;
        RECT 1.785 0.83 1.965 2.41 ;
        RECT 1.74 1.81 1.92 3.83 ;
        RECT 1.02 1.81 1.2 3.83 ;
        RECT 0.985 0.83 1.165 2.41 ;
      LAYER METAL1 ;
        RECT 0.14 1.935 1.32 2.385 ;
      LAYER METAL2 ;
        RECT 0.87 1.935 1.32 2.385 ;
        RECT 0.14 1.935 0.59 2.385 ;
      LAYER CONT ;
        RECT 0.255 2.05 0.475 2.27 ;
        RECT 0.985 2.05 1.205 2.27 ;
      LAYER VIA12 ;
        RECT 0.235 2.03 0.495 2.29 ;
        RECT 0.965 2.03 1.225 2.29 ;
    END
  END A
  PIN VDD
    DIRECTION INOUT ;
    USE POWER ;
    PORT
      LAYER METAL1 ;
        RECT -0.57 4.04 3.49 4.74 ;
        RECT 2.075 2.99 2.305 4.74 ;
        RECT 0.635 2.99 0.865 4.74 ;
    END
  END VDD
END inv_2

MACRO inv_4
  CLASS CORE ;
  ORIGIN 0 -0.35 ;
  FOREIGN inv_4 0 0.35 ;
  SIZE 4.38 BY 4.04 ;
  SYMMETRY X Y ;
  SITE core ;
  PIN Y
    DIRECTION INOUT ;
    USE SIGNAL ;
    ANTENNAPARTIALCUTAREA 0.1352 LAYER VIA12 ;
    ANTENNADIFFAREA 1.1536 LAYER METAL2 ;
    ANTENNADIFFAREA 1.1536 LAYER METAL1 ;
    PORT
      LAYER DIFF ;
        RECT 2.715 1.05 3.335 1.27 ;
        RECT 2.815 0.95 3.235 1.37 ;
        RECT 2.625 2.95 3.165 3.61 ;
        RECT 1.115 1.05 1.735 1.27 ;
        RECT 1.215 0.95 1.635 1.37 ;
        RECT 1.185 2.95 1.725 3.61 ;
      LAYER METAL1 ;
        RECT 3.795 1.79 4.245 2.53 ;
        RECT 1.34 2.52 4.24 2.76 ;
        RECT 1.31 1.56 4.24 1.8 ;
        RECT 2.91 0.99 3.14 1.8 ;
        RECT 2.78 2.52 3.01 3.57 ;
        RECT 1.34 2.52 1.57 3.57 ;
        RECT 1.31 0.99 1.54 1.8 ;
      LAYER METAL2 ;
        RECT 3.79 1.62 4.24 2.525 ;
      LAYER CONT ;
        RECT 1.315 1.05 1.535 1.27 ;
        RECT 1.345 3.17 1.565 3.39 ;
        RECT 2.785 3.17 3.005 3.39 ;
        RECT 2.915 1.05 3.135 1.27 ;
      LAYER VIA12 ;
        RECT 3.875 2.205 4.135 2.465 ;
        RECT 3.875 1.685 4.135 1.945 ;
    END
  END Y
  PIN VSS
    DIRECTION INOUT ;
    USE GROUND ;
    PORT
      LAYER METAL1 ;
        RECT -0.57 0 4.95 0.7 ;
        RECT 3.71 0 3.94 1.33 ;
        RECT 2.11 0 2.34 1.33 ;
        RECT 0.51 0 0.74 1.33 ;
    END
  END VSS
  PIN A
    DIRECTION INOUT ;
    USE SIGNAL ;
    ANTENNAPARTIALCUTAREA 0.1352 LAYER VIA12 ;
    ANTENNAMODEL OXIDE1 ;
      ANTENNAGATEAREA 0.6336 LAYER METAL2 ;
      ANTENNAGATEAREA 0.6336 LAYER METAL1 ;
      ANTENNAMAXAREACAR 0.539773 LAYER METAL2 ;
      ANTENNAMAXCUTCAR 0.213384 LAYER VIA12 ;
    PORT
      LAYER POLY1 ;
        RECT 0.155 1.86 3.515 2.36 ;
        RECT 3.335 0.83 3.515 2.36 ;
        RECT 3.165 1.86 3.345 3.83 ;
        RECT 2.535 0.83 2.715 2.36 ;
        RECT 2.445 1.86 2.625 3.83 ;
        RECT 1.735 0.83 1.915 2.36 ;
        RECT 1.725 1.86 1.905 3.83 ;
        RECT 1.005 1.86 1.185 3.83 ;
        RECT 0.935 0.83 1.115 2.36 ;
        RECT 0.155 1.625 0.575 2.515 ;
      LAYER METAL1 ;
        RECT 0.175 1.62 0.555 2.52 ;
      LAYER METAL2 ;
        RECT 0.14 1.62 0.59 2.515 ;
        RECT 0.175 1.62 0.555 2.52 ;
      LAYER CONT ;
        RECT 0.255 2.195 0.475 2.415 ;
        RECT 0.255 1.725 0.475 1.945 ;
      LAYER VIA12 ;
        RECT 0.235 2.2 0.495 2.46 ;
        RECT 0.235 1.68 0.495 1.94 ;
    END
  END A
  PIN VDD
    DIRECTION INOUT ;
    USE POWER ;
    PORT
      LAYER METAL1 ;
        RECT -0.57 4.04 4.95 4.74 ;
        RECT 3.5 2.99 3.73 4.74 ;
        RECT 2.06 2.99 2.29 4.74 ;
        RECT 0.62 2.99 0.85 4.74 ;
    END
  END VDD
  PROPERTY deviceLevel "CatenaDesignType" ;
  PROPERTY CatenaDesignType "deviceLevel" ;
END inv_4

MACRO inv_8
  CLASS CORE ;
  ORIGIN 0 -0.35 ;
  FOREIGN inv_8 0 0.35 ;
  SIZE 7.3 BY 4.04 ;
  SYMMETRY X Y ;
  SITE core ;
  PIN Y
    DIRECTION INOUT ;
    USE SIGNAL ;
    ANTENNAPARTIALMETALAREA 0.648 LAYER METAL2 ;
    ANTENNAPARTIALCUTAREA 0.4056 LAYER VIA12 ;
    ANTENNADIFFAREA 2.3072 LAYER METAL2 ;
    ANTENNADIFFAREA 2.3072 LAYER METAL1 ;
    PORT
      LAYER DIFF ;
        RECT 5.75 1.05 6.37 1.27 ;
        RECT 5.85 0.95 6.27 1.37 ;
        RECT 5.525 2.95 6.065 3.61 ;
        RECT 4.15 1.05 4.77 1.27 ;
        RECT 4.25 0.95 4.67 1.37 ;
        RECT 4.085 2.95 4.625 3.61 ;
        RECT 2.645 2.95 3.185 3.61 ;
        RECT 2.55 1.05 3.17 1.27 ;
        RECT 2.65 0.95 3.07 1.37 ;
        RECT 1.205 2.95 1.745 3.61 ;
        RECT 0.95 1.05 1.57 1.27 ;
        RECT 1.05 0.95 1.47 1.37 ;
      LAYER METAL1 ;
        RECT 0.14 2.77 7.16 3 ;
        RECT 6.71 1.56 7.16 3 ;
        RECT 0.14 1.56 7.16 1.79 ;
        RECT 5.945 0.99 6.175 1.79 ;
        RECT 5.68 2.77 5.91 3.33 ;
        RECT 4.345 0.99 4.575 1.79 ;
        RECT 4.24 2.77 4.47 3.33 ;
        RECT 2.8 2.77 3.03 3.33 ;
        RECT 2.745 0.99 2.975 1.79 ;
        RECT 1.36 2.77 1.59 3.33 ;
        RECT 1.145 0.99 1.375 1.79 ;
        RECT 0.14 1.56 0.59 3 ;
      LAYER METAL2 ;
        RECT 6.71 1.56 7.16 3 ;
        RECT 0.14 1.56 0.59 3 ;
      LAYER CONT ;
        RECT 1.15 1.05 1.37 1.27 ;
        RECT 1.365 3.05 1.585 3.27 ;
        RECT 2.75 1.05 2.97 1.27 ;
        RECT 2.805 3.05 3.025 3.27 ;
        RECT 4.245 3.05 4.465 3.27 ;
        RECT 4.35 1.05 4.57 1.27 ;
        RECT 5.685 3.05 5.905 3.27 ;
        RECT 5.95 1.05 6.17 1.27 ;
      LAYER VIA12 ;
        RECT 0.235 2.67 0.495 2.93 ;
        RECT 0.235 2.15 0.495 2.41 ;
        RECT 0.235 1.63 0.495 1.89 ;
        RECT 6.805 2.67 7.065 2.93 ;
        RECT 6.805 2.15 7.065 2.41 ;
        RECT 6.805 1.63 7.065 1.89 ;
    END
  END Y
  PIN VSS
    DIRECTION INOUT ;
    USE GROUND ;
    PORT
      LAYER METAL1 ;
        RECT -0.57 0 7.87 0.7 ;
        RECT 6.745 0 6.975 1.33 ;
        RECT 5.145 0 5.375 1.33 ;
        RECT 3.545 0 3.775 1.33 ;
        RECT 1.945 0 2.175 1.33 ;
        RECT 0.345 0 0.575 1.33 ;
    END
  END VSS
  PIN A
    DIRECTION INOUT ;
    USE SIGNAL ;
    ANTENNAPARTIALMETALAREA 0.2025 LAYER METAL2 ;
    ANTENNAPARTIALCUTAREA 0.1352 LAYER VIA12 ;
    ANTENNAMODEL OXIDE1 ;
      ANTENNAGATEAREA 1.2672 LAYER METAL2 ;
      ANTENNAGATEAREA 1.2672 LAYER METAL1 ;
      ANTENNAMAXAREACAR 2.134233 LAYER METAL2 ;
      ANTENNAMAXCUTCAR 0.106692 LAYER VIA12 ;
    PORT
      LAYER POLY1 ;
        RECT 0.77 1.81 6.55 2.455 ;
        RECT 6.37 0.83 6.55 2.455 ;
        RECT 6.065 1.81 6.245 3.83 ;
        RECT 5.57 0.83 5.75 2.455 ;
        RECT 5.345 1.81 5.525 3.83 ;
        RECT 4.77 0.83 4.95 2.455 ;
        RECT 4.625 1.81 4.805 3.83 ;
        RECT 3.97 0.83 4.15 2.455 ;
        RECT 3.905 1.81 4.085 3.83 ;
        RECT 3.185 1.81 3.365 3.83 ;
        RECT 3.17 0.83 3.35 2.455 ;
        RECT 2.465 1.81 2.645 3.83 ;
        RECT 2.37 0.83 2.55 2.455 ;
        RECT 1.745 1.81 1.925 3.83 ;
        RECT 1.57 0.83 1.75 2.455 ;
        RECT 1.025 1.81 1.205 3.83 ;
        RECT 0.77 0.83 0.95 2.455 ;
      LAYER METAL1 ;
        RECT 0.87 2.02 6.43 2.47 ;
      LAYER METAL2 ;
        RECT 1.6 2.02 2.05 2.47 ;
        RECT 0.87 2.02 1.32 2.47 ;
      LAYER CONT ;
        RECT 0.985 2.135 1.205 2.355 ;
        RECT 1.715 2.135 1.935 2.355 ;
        RECT 2.445 2.135 2.665 2.355 ;
        RECT 3.175 2.135 3.395 2.355 ;
        RECT 3.905 2.135 4.125 2.355 ;
        RECT 4.635 2.135 4.855 2.355 ;
        RECT 5.365 2.135 5.585 2.355 ;
        RECT 6.095 2.135 6.315 2.355 ;
      LAYER VIA12 ;
        RECT 0.965 2.115 1.225 2.375 ;
        RECT 1.695 2.115 1.955 2.375 ;
    END
  END A
  PIN VDD
    DIRECTION INOUT ;
    USE POWER ;
    PORT
      LAYER METAL1 ;
        RECT -0.57 4.04 7.87 4.74 ;
        RECT 6.4 3.23 6.63 4.74 ;
        RECT 4.96 3.23 5.19 4.74 ;
        RECT 3.52 3.23 3.75 4.74 ;
        RECT 2.08 3.23 2.31 4.74 ;
        RECT 0.64 3.23 0.87 4.74 ;
    END
  END VDD
END inv_8

MACRO mux2
  CLASS CORE ;
  ORIGIN 0 -0.35 ;
  FOREIGN mux2 0 0.35 ;
  SIZE 6.57 BY 4.04 ;
  SYMMETRY X Y ;
  SITE core ;
  PIN X
    DIRECTION INOUT ;
    USE SIGNAL ;
    ANTENNAPARTIALCUTAREA 0.2028 LAYER VIA12 ;
    ANTENNADIFFAREA 0.6175 LAYER METAL2 ;
    ANTENNADIFFAREA 0.6175 LAYER METAL1 ;
    PORT
      LAYER DIFF ;
        RECT 0.995 1.05 1.515 1.27 ;
        RECT 0.995 0.95 1.415 1.37 ;
        RECT 0.46 2.95 1.095 3.61 ;
      LAYER METAL1 ;
        RECT 0.21 0.99 1.32 1.33 ;
        RECT 0.21 2.99 0.94 3.57 ;
        RECT 0.21 0.99 0.59 3.57 ;
      LAYER METAL2 ;
        RECT 0.14 1.445 0.59 2.865 ;
      LAYER CONT ;
        RECT 0.715 3.17 0.935 3.39 ;
        RECT 1.095 1.05 1.315 1.27 ;
      LAYER VIA12 ;
        RECT 0.27 2.545 0.53 2.805 ;
        RECT 0.27 2.025 0.53 2.285 ;
        RECT 0.27 1.505 0.53 1.765 ;
    END
  END X
  PIN VSS
    DIRECTION INOUT ;
    USE GROUND ;
    PORT
      LAYER METAL1 ;
        RECT -0.57 0 7.14 0.7 ;
        RECT 5.155 0 5.385 1.33 ;
        RECT 1.89 0 2.12 1.33 ;
    END
  END VSS
  PIN VDD
    DIRECTION INOUT ;
    USE POWER ;
    PORT
      LAYER METAL1 ;
        RECT -0.57 4.04 7.14 4.74 ;
        RECT 5.06 3.23 5.29 4.74 ;
        RECT 1.43 3.23 1.66 4.74 ;
    END
  END VDD
  PIN A1
    DIRECTION INOUT ;
    USE SIGNAL ;
    ANTENNAPARTIALCUTAREA 0.0676 LAYER VIA12 ;
    ANTENNAMODEL OXIDE1 ;
      ANTENNAGATEAREA 0.1584 LAYER METAL2 ;
      ANTENNAGATEAREA 0.1584 LAYER METAL1 ;
      ANTENNAMAXAREACAR 3.884154 LAYER METAL2 ;
      ANTENNAMAXCUTCAR 0.426768 LAYER VIA12 ;
    PORT
      LAYER POLY1 ;
        RECT 4.295 2.245 4.475 3.83 ;
        RECT 3.945 2.245 4.475 2.665 ;
        RECT 2.77 1.52 3.19 1.94 ;
        RECT 2.77 0.83 2.95 1.94 ;
      LAYER METAL1 ;
        RECT 3.985 2.24 4.325 2.625 ;
        RECT 3.28 2.24 4.325 2.47 ;
        RECT 3.28 1.56 3.51 2.47 ;
        RECT 3.13 1.56 3.51 1.94 ;
        RECT 2.81 1.56 3.51 1.9 ;
      LAYER METAL2 ;
        RECT 3.06 1.56 3.51 2.015 ;
      LAYER CONT ;
        RECT 2.87 1.62 3.09 1.84 ;
        RECT 4.045 2.345 4.265 2.565 ;
      LAYER VIA12 ;
        RECT 3.19 1.62 3.45 1.88 ;
    END
  END A1
  PIN S
    DIRECTION INOUT ;
    USE SIGNAL ;
    ANTENNAPARTIALCUTAREA 0.0676 LAYER VIA12 ;
    ANTENNAMODEL OXIDE1 ;
      ANTENNAGATEAREA 0.3168 LAYER METAL2 ;
      ANTENNAGATEAREA 0.3168 LAYER METAL1 ;
      ANTENNAMAXAREACAR 5.54072 LAYER METAL2 ;
      ANTENNAMAXCUTCAR 0.213384 LAYER VIA12 ;
    PORT
      LAYER POLY1 ;
        RECT 5.265 2.31 5.76 2.73 ;
        RECT 5.58 0.83 5.76 2.73 ;
        RECT 5.445 2.31 5.625 3.83 ;
        RECT 1.995 1.49 2.495 1.67 ;
        RECT 2.315 0.83 2.495 1.67 ;
        RECT 1.575 2.245 2.175 2.665 ;
        RECT 1.995 1.49 2.175 2.665 ;
        RECT 1.815 2.245 1.995 3.83 ;
      LAYER METAL1 ;
        RECT 4.555 2.295 5.7 2.745 ;
        RECT 1.89 3.56 4.785 3.79 ;
        RECT 4.555 2.295 4.785 3.79 ;
        RECT 1.89 2.285 2.12 3.79 ;
        RECT 1.615 2.285 2.12 2.625 ;
      LAYER METAL2 ;
        RECT 5.25 2.295 5.7 2.745 ;
      LAYER CONT ;
        RECT 1.675 2.345 1.895 2.565 ;
        RECT 5.365 2.41 5.585 2.63 ;
      LAYER VIA12 ;
        RECT 5.345 2.39 5.605 2.65 ;
    END
  END S
  PIN A0
    DIRECTION INOUT ;
    USE SIGNAL ;
    ANTENNAPARTIALCUTAREA 0.0676 LAYER VIA12 ;
    ANTENNAMODEL OXIDE1 ;
      ANTENNAGATEAREA 0.1584 LAYER METAL2 ;
      ANTENNAGATEAREA 0.1584 LAYER METAL1 ;
      ANTENNAMAXAREACAR 1.278409 LAYER METAL2 ;
      ANTENNAMAXCUTCAR 0.426768 LAYER VIA12 ;
    PORT
      LAYER POLY1 ;
        RECT 3.515 1.49 4.53 1.67 ;
        RECT 4.35 0.83 4.53 1.67 ;
        RECT 3.515 1.49 4.225 1.995 ;
        RECT 2.82 2.55 3.695 2.73 ;
        RECT 3.515 1.49 3.695 2.73 ;
        RECT 2.82 2.55 3 3.83 ;
      LAYER METAL1 ;
        RECT 3.79 1.56 4.24 2.01 ;
      LAYER METAL2 ;
        RECT 3.79 1.56 4.24 2.01 ;
      LAYER CONT ;
        RECT 3.905 1.675 4.125 1.895 ;
      LAYER VIA12 ;
        RECT 3.885 1.655 4.145 1.915 ;
    END
  END A0
  OBS
    LAYER METAL1 ;
      RECT 5.78 2.99 6.185 3.57 ;
      RECT 5.955 0.99 6.185 3.57 ;
      RECT 4.82 1.66 6.185 2 ;
      RECT 2.35 2.99 4.14 3.33 ;
      RECT 2.35 1.1 2.58 3.33 ;
      RECT 1.135 1.725 2.58 1.955 ;
      RECT 1.135 1.615 1.475 1.955 ;
      RECT 2.35 1.1 4.155 1.33 ;
      RECT 3.145 0.99 4.155 1.33 ;
  END
END mux2

MACRO mux2i
  CLASS CORE ;
  ORIGIN 0 -0.35 ;
  FOREIGN mux2i 0 0.35 ;
  SIZE 6.57 BY 4.04 ;
  SYMMETRY X Y ;
  SITE core ;
  PIN Y
    DIRECTION INOUT ;
    USE SIGNAL ;
    ANTENNAPARTIALCUTAREA 0.1352 LAYER VIA12 ;
    ANTENNADIFFAREA 0.5768 LAYER METAL2 ;
    ANTENNADIFFAREA 0.5768 LAYER METAL1 ;
    PORT
      LAYER DIFF ;
        RECT 1.395 2.95 1.935 3.61 ;
        RECT 0.95 1.45 1.57 1.67 ;
        RECT 1.05 1.35 1.47 1.77 ;
      LAYER METAL1 ;
        RECT 1.55 2.77 1.78 3.33 ;
        RECT 1.055 2.77 1.78 3 ;
        RECT 1.055 1.39 1.375 1.73 ;
        RECT 0.905 1.89 1.285 2.79 ;
        RECT 1.055 1.39 1.285 3 ;
      LAYER METAL2 ;
        RECT 0.87 1.89 1.32 2.79 ;
      LAYER CONT ;
        RECT 1.15 1.45 1.37 1.67 ;
        RECT 1.555 3.05 1.775 3.27 ;
      LAYER VIA12 ;
        RECT 0.965 2.47 1.225 2.73 ;
        RECT 0.965 1.95 1.225 2.21 ;
    END
  END Y
  PIN VSS
    DIRECTION INOUT ;
    USE GROUND ;
    PORT
      LAYER METAL1 ;
        RECT -0.57 0 7.14 0.7 ;
        RECT 5.905 0 6.135 1.33 ;
        RECT 3.525 0 3.755 1.33 ;
    END
  END VSS
  PIN A0
    DIRECTION INOUT ;
    USE SIGNAL ;
    ANTENNAPARTIALCUTAREA 0.1352 LAYER VIA12 ;
    ANTENNAMODEL OXIDE1 ;
      ANTENNAGATEAREA 0.1584 LAYER METAL2 ;
      ANTENNAGATEAREA 0.1584 LAYER METAL1 ;
      ANTENNAMAXAREACAR 2.755682 LAYER METAL2 ;
      ANTENNAMAXCUTCAR 0.853535 LAYER VIA12 ;
    PORT
      LAYER POLY1 ;
        RECT 1.215 2.67 1.395 3.83 ;
        RECT 0.155 2.67 1.395 2.85 ;
        RECT 0.155 1.97 0.95 2.85 ;
        RECT 0.77 1.23 0.95 2.85 ;
        RECT 0.155 1.97 0.575 2.9 ;
      LAYER METAL1 ;
        RECT 0.14 1.97 0.59 2.94 ;
      LAYER METAL2 ;
        RECT 0.14 1.97 0.59 2.94 ;
      LAYER CONT ;
        RECT 0.255 2.58 0.475 2.8 ;
        RECT 0.255 2.11 0.475 2.33 ;
      LAYER VIA12 ;
        RECT 0.235 2.585 0.495 2.845 ;
        RECT 0.235 2.065 0.495 2.325 ;
    END
  END A0
  PIN VDD
    DIRECTION INOUT ;
    USE POWER ;
    PORT
      LAYER METAL1 ;
        RECT -0.57 4.04 7.14 4.74 ;
        RECT 5.42 2.99 5.65 4.74 ;
        RECT 2.7 3.23 2.93 4.74 ;
    END
  END VDD
  PIN A1
    DIRECTION INOUT ;
    USE SIGNAL ;
    ANTENNAPARTIALCUTAREA 0.0676 LAYER VIA12 ;
    ANTENNAMODEL OXIDE1 ;
      ANTENNAGATEAREA 0.1584 LAYER METAL2 ;
      ANTENNAGATEAREA 0.1584 LAYER METAL1 ;
      ANTENNAMAXAREACAR 1.278409 LAYER METAL2 ;
      ANTENNAMAXCUTCAR 0.426768 LAYER VIA12 ;
    PORT
      LAYER POLY1 ;
        RECT 1.935 1.89 2.115 3.83 ;
        RECT 1.57 1.89 2.115 2.455 ;
        RECT 1.57 1.23 1.75 2.455 ;
      LAYER METAL1 ;
        RECT 1.6 2.02 2.05 2.47 ;
      LAYER METAL2 ;
        RECT 1.6 2.02 2.05 2.47 ;
      LAYER CONT ;
        RECT 1.715 2.135 1.935 2.355 ;
      LAYER VIA12 ;
        RECT 1.695 2.115 1.955 2.375 ;
    END
  END A1
  PIN S
    DIRECTION INOUT ;
    USE SIGNAL ;
    ANTENNAPARTIALCUTAREA 0.1352 LAYER VIA12 ;
    ANTENNAMODEL OXIDE1 ;
      ANTENNAGATEAREA 0.3168 LAYER METAL2 ;
      ANTENNAGATEAREA 0.3168 LAYER METAL1 ;
      ANTENNAMAXAREACAR 1.079545 LAYER METAL2 ;
      ANTENNAMAXCUTCAR 0.426768 LAYER VIA12 ;
    PORT
      LAYER POLY1 ;
        RECT 5.995 1.795 6.415 2.685 ;
        RECT 5.085 1.795 6.415 2.52 ;
        RECT 5.53 0.83 5.71 2.52 ;
        RECT 5.085 1.795 5.265 3.83 ;
        RECT 3.085 2.245 6.415 2.425 ;
        RECT 3.95 1.795 6.415 2.425 ;
        RECT 3.95 0.83 4.13 2.425 ;
        RECT 3.085 2.245 3.265 3.83 ;
      LAYER METAL1 ;
        RECT 6.015 1.79 6.395 2.69 ;
      LAYER METAL2 ;
        RECT 5.98 1.79 6.43 2.69 ;
      LAYER CONT ;
        RECT 6.095 2.365 6.315 2.585 ;
        RECT 6.095 1.895 6.315 2.115 ;
      LAYER VIA12 ;
        RECT 6.075 2.37 6.335 2.63 ;
        RECT 6.075 1.85 6.335 2.11 ;
    END
  END S
  OBS
    LAYER METAL1 ;
      RECT 4.7 2.02 4.93 3.57 ;
      RECT 2.405 2.02 2.745 2.36 ;
      RECT 2.405 2.02 5.335 2.255 ;
      RECT 5.105 0.99 5.335 2.255 ;
      RECT 1.945 1.56 4.555 1.79 ;
      RECT 4.325 0.99 4.555 1.79 ;
      RECT 1.945 1.39 2.175 1.79 ;
      RECT 0.83 3.56 2.355 3.79 ;
      RECT 2.125 2.77 2.355 3.79 ;
      RECT 3.42 2.77 3.65 3.57 ;
      RECT 0.83 3.23 1.06 3.79 ;
      RECT 2.125 2.77 3.65 3 ;
      RECT 0.345 0.93 0.575 1.73 ;
      RECT 2.725 0.93 2.955 1.33 ;
      RECT 0.345 0.93 2.955 1.16 ;
  END
END mux2i

MACRO nand2_1
  CLASS CORE ;
  ORIGIN 0 -0.35 ;
  FOREIGN nand2_1 0 0.35 ;
  SIZE 2.92 BY 4.04 ;
  SYMMETRY X Y ;
  SITE core ;
  PIN A
    DIRECTION INOUT ;
    USE SIGNAL ;
    ANTENNAPARTIALCUTAREA 0.1352 LAYER VIA12 ;
    ANTENNAMODEL OXIDE1 ;
      ANTENNAGATEAREA 0.198 LAYER METAL2 ;
      ANTENNAGATEAREA 0.198 LAYER METAL1 ;
      ANTENNAMAXAREACAR 1.887879 LAYER METAL2 ;
      ANTENNAMAXCUTCAR 0.682828 LAYER VIA12 ;
    PORT
      LAYER POLY1 ;
        RECT 0.155 1.66 1.335 1.84 ;
        RECT 1.155 0.83 1.335 1.84 ;
        RECT 1.01 2.55 1.19 3.83 ;
        RECT 0.155 2.55 1.19 2.73 ;
        RECT 0.155 1.66 0.575 2.73 ;
      LAYER METAL1 ;
        RECT 0.155 1.66 0.575 2.55 ;
      LAYER METAL2 ;
        RECT 0.14 1.66 0.59 2.55 ;
      LAYER CONT ;
        RECT 0.255 2.23 0.475 2.45 ;
        RECT 0.255 1.76 0.475 1.98 ;
      LAYER VIA12 ;
        RECT 0.235 2.235 0.495 2.495 ;
        RECT 0.235 1.715 0.495 1.975 ;
    END
  END A
  PIN B
    DIRECTION INOUT ;
    USE SIGNAL ;
    ANTENNAPARTIALCUTAREA 0.1352 LAYER VIA12 ;
    ANTENNAMODEL OXIDE1 ;
      ANTENNAGATEAREA 0.198 LAYER METAL2 ;
      ANTENNAGATEAREA 0.198 LAYER METAL1 ;
      ANTENNAMAXAREACAR 1.887879 LAYER METAL2 ;
      ANTENNAMAXCUTCAR 0.682828 LAYER VIA12 ;
    PORT
      LAYER POLY1 ;
        RECT 1.73 2.55 2.765 2.73 ;
        RECT 2.345 1.66 2.765 2.73 ;
        RECT 1.585 1.66 2.765 1.84 ;
        RECT 1.73 2.55 1.91 3.83 ;
        RECT 1.585 0.83 1.765 1.84 ;
      LAYER METAL1 ;
        RECT 2.345 1.66 2.765 2.55 ;
      LAYER METAL2 ;
        RECT 2.33 1.66 2.78 2.55 ;
      LAYER CONT ;
        RECT 2.445 2.23 2.665 2.45 ;
        RECT 2.445 1.76 2.665 1.98 ;
      LAYER VIA12 ;
        RECT 2.425 2.235 2.685 2.495 ;
        RECT 2.425 1.715 2.685 1.975 ;
    END
  END B
  PIN Y
    DIRECTION INOUT ;
    USE SIGNAL ;
    ANTENNAPARTIALCUTAREA 0.1352 LAYER VIA12 ;
    ANTENNADIFFAREA 0.5676 LAYER METAL2 ;
    ANTENNADIFFAREA 0.5676 LAYER METAL1 ;
    PORT
      LAYER DIFF ;
        RECT 1.765 1.05 2.245 1.49 ;
        RECT 1.19 2.95 1.73 3.61 ;
      LAYER METAL1 ;
        RECT 1.345 1.09 2.15 1.45 ;
        RECT 1.345 1.09 2.115 2.52 ;
        RECT 1.345 1.09 1.575 3.57 ;
      LAYER METAL2 ;
        RECT 1.6 1.66 2.05 2.52 ;
      LAYER CONT ;
        RECT 1.35 3.17 1.57 3.39 ;
        RECT 1.925 1.16 2.145 1.38 ;
      LAYER VIA12 ;
        RECT 1.695 2.22 1.955 2.48 ;
        RECT 1.695 1.7 1.955 1.96 ;
    END
  END Y
  PIN VDD
    DIRECTION INOUT ;
    USE POWER ;
    PORT
      LAYER METAL1 ;
        RECT -0.57 4.04 3.49 4.74 ;
        RECT 2.065 2.99 2.295 4.74 ;
        RECT 0.625 2.99 0.855 4.74 ;
    END
  END VDD
  PIN VSS
    DIRECTION INOUT ;
    USE GROUND ;
    PORT
      LAYER METAL1 ;
        RECT -0.57 0 3.49 0.7 ;
        RECT 0.77 0 1 1.45 ;
    END
  END VSS
END nand2_1

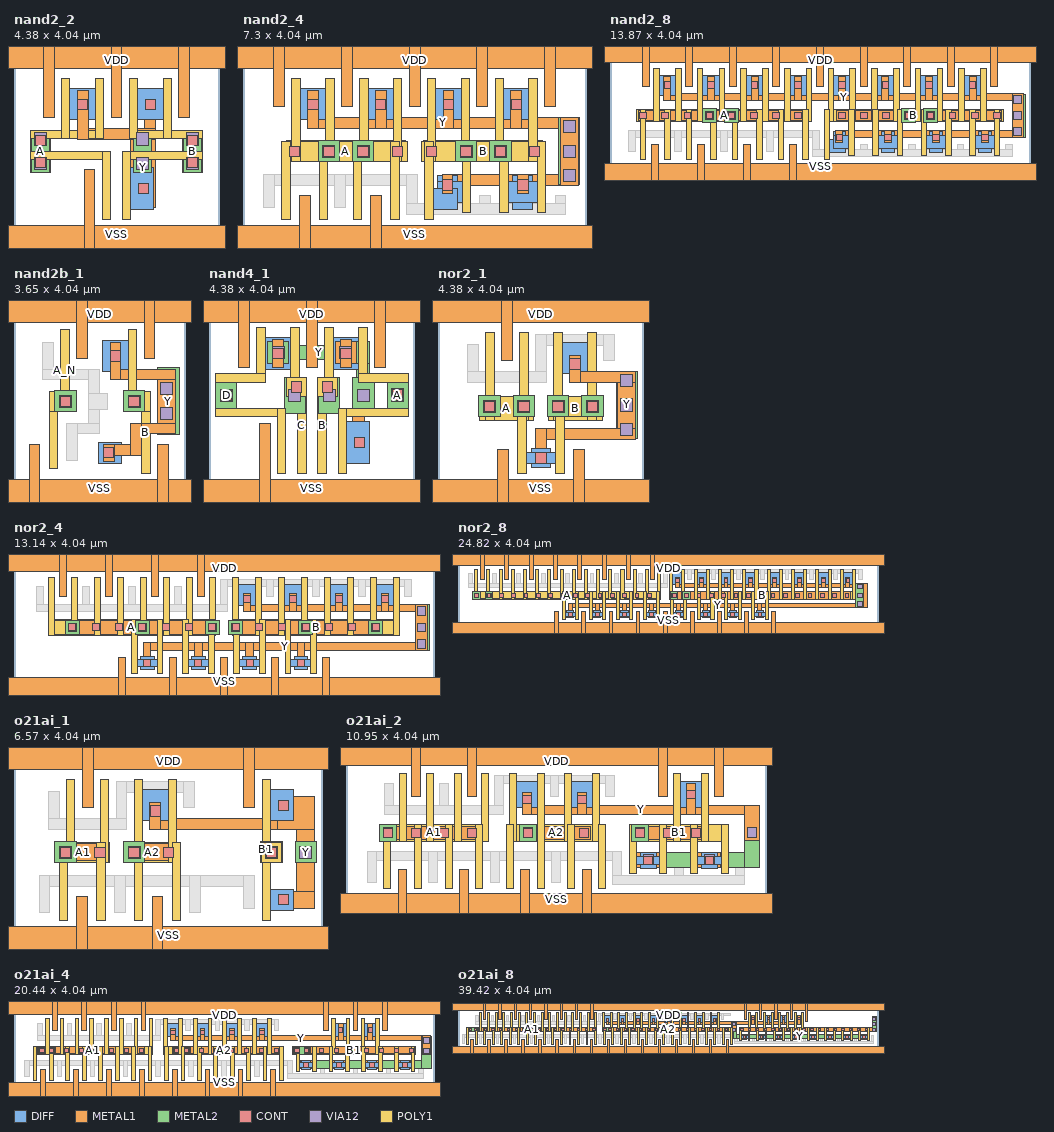
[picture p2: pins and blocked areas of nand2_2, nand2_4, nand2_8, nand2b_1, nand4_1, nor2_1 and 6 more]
MACRO nand2_2
  CLASS CORE ;
  ORIGIN 0 -0.35 ;
  FOREIGN nand2_2 0 0.35 ;
  SIZE 4.38 BY 4.04 ;
  SYMMETRY X Y ;
  SITE core ;
  PIN Y
    DIRECTION INOUT ;
    USE SIGNAL ;
    ANTENNAPARTIALCUTAREA 0.1352 LAYER VIA12 ;
    ANTENNADIFFAREA 1.1352 LAYER METAL2 ;
    ANTENNADIFFAREA 1.1352 LAYER METAL1 ;
    PORT
      LAYER DIFF ;
        RECT 2.63 2.95 3.17 3.61 ;
        RECT 2.485 1.05 2.965 1.93 ;
        RECT 1.19 2.95 1.73 3.61 ;
      LAYER METAL1 ;
        RECT 2.785 1.09 3.015 3.57 ;
        RECT 1.345 2.53 3.015 2.76 ;
        RECT 2.485 1.09 3.015 2.76 ;
        RECT 1.345 2.53 1.575 3.57 ;
      LAYER METAL2 ;
        RECT 2.55 1.83 2.93 2.73 ;
      LAYER CONT ;
        RECT 1.35 3.17 1.57 3.39 ;
        RECT 2.645 1.38 2.865 1.6 ;
        RECT 2.79 3.17 3.01 3.39 ;
      LAYER VIA12 ;
        RECT 2.61 2.41 2.87 2.67 ;
        RECT 2.61 1.89 2.87 2.15 ;
    END
  END Y
  PIN VSS
    DIRECTION INOUT ;
    USE GROUND ;
    PORT
      LAYER METAL1 ;
        RECT -0.57 0 4.95 0.7 ;
        RECT 1.49 0 1.72 1.89 ;
    END
  END VSS
  PIN A
    DIRECTION INOUT ;
    USE SIGNAL ;
    ANTENNAPARTIALCUTAREA 0.1352 LAYER VIA12 ;
    ANTENNAMODEL OXIDE1 ;
      ANTENNAGATEAREA 0.396 LAYER METAL2 ;
      ANTENNAGATEAREA 0.396 LAYER METAL1 ;
      ANTENNAMAXAREACAR 0.863636 LAYER METAL2 ;
      ANTENNAMAXCUTCAR 0.341414 LAYER VIA12 ;
    PORT
      LAYER POLY1 ;
        RECT 0.35 2.1 2.055 2.28 ;
        RECT 1.875 0.83 2.055 2.28 ;
        RECT 1.73 2.55 1.91 3.83 ;
        RECT 0.35 2.55 1.91 2.73 ;
        RECT 1.01 2.55 1.19 3.83 ;
        RECT 0.35 1.835 0.77 2.73 ;
      LAYER METAL1 ;
        RECT 0.37 1.83 0.75 2.73 ;
      LAYER METAL2 ;
        RECT 0.37 1.83 0.75 2.73 ;
      LAYER CONT ;
        RECT 0.45 2.405 0.67 2.625 ;
        RECT 0.45 1.935 0.67 2.155 ;
      LAYER VIA12 ;
        RECT 0.43 2.41 0.69 2.67 ;
        RECT 0.43 1.89 0.69 2.15 ;
    END
  END A
  PIN B
    DIRECTION INOUT ;
    USE SIGNAL ;
    ANTENNAPARTIALCUTAREA 0.1352 LAYER VIA12 ;
    ANTENNAMODEL OXIDE1 ;
      ANTENNAGATEAREA 0.396 LAYER METAL2 ;
      ANTENNAGATEAREA 0.396 LAYER METAL1 ;
      ANTENNAMAXAREACAR 0.863636 LAYER METAL2 ;
      ANTENNAMAXCUTCAR 0.341414 LAYER VIA12 ;
    PORT
      LAYER POLY1 ;
        RECT 2.45 2.55 4.01 2.73 ;
        RECT 3.59 1.835 4.01 2.73 ;
        RECT 2.305 2.1 4.01 2.28 ;
        RECT 3.17 2.55 3.35 3.83 ;
        RECT 2.45 2.55 2.63 3.83 ;
        RECT 2.305 0.83 2.485 2.28 ;
      LAYER METAL1 ;
        RECT 3.61 1.83 3.99 2.73 ;
      LAYER METAL2 ;
        RECT 3.61 1.83 3.99 2.73 ;
      LAYER CONT ;
        RECT 3.69 2.405 3.91 2.625 ;
        RECT 3.69 1.935 3.91 2.155 ;
      LAYER VIA12 ;
        RECT 3.67 2.41 3.93 2.67 ;
        RECT 3.67 1.89 3.93 2.15 ;
    END
  END B
  PIN VDD
    DIRECTION INOUT ;
    USE POWER ;
    PORT
      LAYER METAL1 ;
        RECT -0.57 4.04 4.95 4.74 ;
        RECT 3.505 2.99 3.735 4.74 ;
        RECT 2.065 2.99 2.295 4.74 ;
        RECT 0.625 2.99 0.855 4.74 ;
    END
  END VDD
END nand2_2

MACRO nand2_4
  CLASS CORE ;
  ORIGIN 0 -0.35 ;
  FOREIGN nand2_4 0 0.35 ;
  SIZE 7.3 BY 4.04 ;
  SYMMETRY X Y ;
  SITE core ;
  PIN VDD
    DIRECTION INOUT ;
    USE POWER ;
    PORT
      LAYER METAL1 ;
        RECT -0.57 4.04 7.87 4.74 ;
        RECT 6.415 3.23 6.645 4.74 ;
        RECT 4.975 3.23 5.205 4.74 ;
        RECT 3.535 3.23 3.765 4.74 ;
        RECT 2.095 3.23 2.325 4.74 ;
        RECT 0.655 3.23 0.885 4.74 ;
    END
  END VDD
  PIN B
    DIRECTION INOUT ;
    USE SIGNAL ;
    ANTENNAPARTIALMETALAREA 0.2025 LAYER METAL2 ;
    ANTENNAPARTIALCUTAREA 0.1352 LAYER VIA12 ;
    ANTENNAMODEL OXIDE1 ;
      ANTENNAGATEAREA 0.792 LAYER METAL2 ;
      ANTENNAGATEAREA 0.792 LAYER METAL1 ;
      ANTENNAMAXAREACAR 1.693182 LAYER METAL2 ;
      ANTENNAMAXCUTCAR 0.170707 LAYER VIA12 ;
    PORT
      LAYER POLY1 ;
        RECT 3.805 2.07 6.44 2.49 ;
        RECT 6.26 0.97 6.44 2.49 ;
        RECT 6.08 2.07 6.26 3.83 ;
        RECT 5.46 0.97 5.64 2.49 ;
        RECT 5.36 2.07 5.54 3.83 ;
        RECT 4.66 0.97 4.84 2.49 ;
        RECT 4.64 2.07 4.82 3.83 ;
        RECT 3.92 2.07 4.1 3.83 ;
        RECT 3.86 0.83 4.04 2.49 ;
      LAYER METAL1 ;
        RECT 3.845 2.055 6.375 2.505 ;
      LAYER METAL2 ;
        RECT 5.25 2.055 5.7 2.505 ;
        RECT 4.52 2.055 4.97 2.505 ;
      LAYER CONT ;
        RECT 3.905 2.17 4.125 2.39 ;
        RECT 4.635 2.17 4.855 2.39 ;
        RECT 5.365 2.17 5.585 2.39 ;
        RECT 6.095 2.17 6.315 2.39 ;
      LAYER VIA12 ;
        RECT 4.615 2.15 4.875 2.41 ;
        RECT 5.345 2.15 5.605 2.41 ;
    END
  END B
  PIN Y
    DIRECTION INOUT ;
    USE SIGNAL ;
    ANTENNAPARTIALCUTAREA 0.2028 LAYER VIA12 ;
    ANTENNADIFFAREA 2.2064 LAYER METAL2 ;
    ANTENNADIFFAREA 2.2064 LAYER METAL1 ;
    PORT
      LAYER DIFF ;
        RECT 5.64 1.19 6.26 1.63 ;
        RECT 5.74 1.05 6.16 1.77 ;
        RECT 5.54 2.95 6.08 3.61 ;
        RECT 4.14 1.19 4.66 1.63 ;
        RECT 4.14 1.05 4.56 1.77 ;
        RECT 4.04 1.05 4.56 1.49 ;
        RECT 4.1 2.95 4.64 3.61 ;
        RECT 2.66 2.95 3.2 3.61 ;
        RECT 1.22 2.95 1.76 3.61 ;
      LAYER METAL1 ;
        RECT 1.375 2.77 7.125 3 ;
        RECT 6.745 1.56 7.125 3 ;
        RECT 4.235 1.56 7.125 1.79 ;
        RECT 5.835 1.39 6.065 1.79 ;
        RECT 5.695 2.77 5.925 3.57 ;
        RECT 4.255 2.77 4.485 3.57 ;
        RECT 4.235 1.39 4.465 1.79 ;
        RECT 2.815 2.77 3.045 3.57 ;
        RECT 1.375 2.77 1.605 3.57 ;
      LAYER METAL2 ;
        RECT 6.71 1.57 7.16 2.99 ;
      LAYER CONT ;
        RECT 1.38 3.17 1.6 3.39 ;
        RECT 2.82 3.17 3.04 3.39 ;
        RECT 4.24 1.45 4.46 1.67 ;
        RECT 4.26 3.17 4.48 3.39 ;
        RECT 5.7 3.17 5.92 3.39 ;
        RECT 5.84 1.45 6.06 1.67 ;
      LAYER VIA12 ;
        RECT 6.805 2.67 7.065 2.93 ;
        RECT 6.805 2.15 7.065 2.41 ;
        RECT 6.805 1.63 7.065 1.89 ;
    END
  END Y
  PIN A
    DIRECTION INOUT ;
    USE SIGNAL ;
    ANTENNAPARTIALMETALAREA 0.2025 LAYER METAL2 ;
    ANTENNAPARTIALCUTAREA 0.1352 LAYER VIA12 ;
    ANTENNAMODEL OXIDE1 ;
      ANTENNAGATEAREA 0.792 LAYER METAL2 ;
      ANTENNAGATEAREA 0.792 LAYER METAL1 ;
      ANTENNAMAXAREACAR 1.693182 LAYER METAL2 ;
      ANTENNAMAXCUTCAR 0.170707 LAYER VIA12 ;
    PORT
      LAYER POLY1 ;
        RECT 0.82 2.07 3.495 2.49 ;
        RECT 3.2 2.07 3.38 3.83 ;
        RECT 3.14 0.83 3.32 2.49 ;
        RECT 2.48 2.07 2.66 3.83 ;
        RECT 2.34 0.83 2.52 2.49 ;
        RECT 1.76 2.07 1.94 3.83 ;
        RECT 1.62 0.83 1.8 2.49 ;
        RECT 1.04 2.07 1.22 3.83 ;
        RECT 0.82 0.83 1 2.49 ;
      LAYER METAL1 ;
        RECT 0.925 2.055 3.455 2.505 ;
      LAYER METAL2 ;
        RECT 2.33 2.055 2.78 2.505 ;
        RECT 1.6 2.055 2.05 2.505 ;
      LAYER CONT ;
        RECT 0.985 2.17 1.205 2.39 ;
        RECT 1.715 2.17 1.935 2.39 ;
        RECT 2.445 2.17 2.665 2.39 ;
        RECT 3.175 2.17 3.395 2.39 ;
      LAYER VIA12 ;
        RECT 1.695 2.15 1.955 2.41 ;
        RECT 2.425 2.15 2.685 2.41 ;
    END
  END A
  PIN VSS
    DIRECTION INOUT ;
    USE GROUND ;
    PORT
      LAYER METAL1 ;
        RECT -0.57 0 7.87 0.7 ;
        RECT 2.715 0 2.945 1.33 ;
        RECT 1.195 0 1.425 1.33 ;
    END
  END VSS
  OBS
    LAYER METAL1 ;
      RECT 0.435 1.56 3.705 1.79 ;
      RECT 3.475 0.93 3.705 1.79 ;
      RECT 1.955 1.09 2.185 1.79 ;
      RECT 0.435 1.09 0.665 1.79 ;
      RECT 6.635 0.93 6.865 1.33 ;
      RECT 5.035 0.93 5.265 1.33 ;
      RECT 3.475 0.93 6.865 1.16 ;
  END
END nand2_4

MACRO nand2_8
  CLASS CORE ;
  ORIGIN 0 -0.35 ;
  FOREIGN nand2_8 0 0.35 ;
  SIZE 13.87 BY 4.04 ;
  SYMMETRY X Y ;
  SITE core ;
  PIN A
    DIRECTION INOUT ;
    USE SIGNAL ;
    ANTENNAPARTIALMETALAREA 0.2025 LAYER METAL2 ;
    ANTENNAPARTIALCUTAREA 0.1352 LAYER VIA12 ;
    ANTENNAMODEL OXIDE1 ;
      ANTENNAGATEAREA 1.584 LAYER METAL2 ;
      ANTENNAGATEAREA 1.584 LAYER METAL1 ;
      ANTENNAMAXAREACAR 1.360164 LAYER METAL2 ;
      ANTENNAMAXCUTCAR 0.085354 LAYER VIA12 ;
    PORT
      LAYER POLY1 ;
        RECT 6.485 2.07 6.665 3.83 ;
        RECT 6.365 0.83 6.545 2.49 ;
        RECT 0.885 2.07 6.665 2.49 ;
        RECT 5.765 2.07 5.945 3.83 ;
        RECT 5.565 0.83 5.745 2.49 ;
        RECT 5.045 2.07 5.225 3.83 ;
        RECT 4.845 0.83 5.025 2.49 ;
        RECT 4.325 2.07 4.505 3.83 ;
        RECT 4.045 0.83 4.225 2.49 ;
        RECT 3.605 2.07 3.785 3.83 ;
        RECT 3.325 0.83 3.505 2.49 ;
        RECT 2.885 2.07 3.065 3.83 ;
        RECT 2.525 0.83 2.705 2.49 ;
        RECT 2.165 2.07 2.345 3.83 ;
        RECT 1.805 0.83 1.985 2.49 ;
        RECT 1.445 2.07 1.625 3.83 ;
        RECT 1.005 0.83 1.185 2.49 ;
      LAYER METAL1 ;
        RECT 0.925 2.11 6.375 2.45 ;
        RECT 3.79 2.055 4.24 2.505 ;
        RECT 3.06 2.055 3.51 2.505 ;
      LAYER METAL2 ;
        RECT 3.79 2.055 4.24 2.505 ;
        RECT 3.06 2.055 3.51 2.505 ;
      LAYER CONT ;
        RECT 0.985 2.17 1.205 2.39 ;
        RECT 1.715 2.17 1.935 2.39 ;
        RECT 2.445 2.17 2.665 2.39 ;
        RECT 3.175 2.17 3.395 2.39 ;
        RECT 3.905 2.17 4.125 2.39 ;
        RECT 4.635 2.17 4.855 2.39 ;
        RECT 5.365 2.17 5.585 2.39 ;
        RECT 6.095 2.17 6.315 2.39 ;
      LAYER VIA12 ;
        RECT 3.155 2.15 3.415 2.41 ;
        RECT 3.885 2.15 4.145 2.41 ;
    END
  END A
  PIN VSS
    DIRECTION INOUT ;
    USE GROUND ;
    PORT
      LAYER METAL1 ;
        RECT -0.57 0 14.44 0.7 ;
        RECT 5.94 0 6.17 1.33 ;
        RECT 4.42 0 4.65 1.33 ;
        RECT 2.9 0 3.13 1.33 ;
        RECT 1.38 0 1.61 1.33 ;
    END
  END VSS
  PIN VDD
    DIRECTION INOUT ;
    USE POWER ;
    PORT
      LAYER METAL1 ;
        RECT -0.57 4.04 14.44 4.74 ;
        RECT 12.58 3.23 12.81 4.74 ;
        RECT 11.14 3.23 11.37 4.74 ;
        RECT 9.7 3.23 9.93 4.74 ;
        RECT 8.26 3.23 8.49 4.74 ;
        RECT 6.82 3.23 7.05 4.74 ;
        RECT 5.38 3.23 5.61 4.74 ;
        RECT 3.94 3.23 4.17 4.74 ;
        RECT 2.5 3.23 2.73 4.74 ;
        RECT 1.06 3.23 1.29 4.74 ;
    END
  END VDD
  PIN Y
    DIRECTION INOUT ;
    USE SIGNAL ;
    ANTENNAPARTIALCUTAREA 0.2028 LAYER VIA12 ;
    ANTENNADIFFAREA 4.4128 LAYER METAL2 ;
    ANTENNADIFFAREA 4.4128 LAYER METAL1 ;
    PORT
      LAYER DIFF ;
        RECT 12.065 1.19 12.685 1.63 ;
        RECT 12.165 1.05 12.585 1.77 ;
        RECT 11.705 2.95 12.245 3.61 ;
        RECT 10.465 1.19 11.085 1.63 ;
        RECT 10.565 1.05 10.985 1.77 ;
        RECT 10.265 2.95 10.805 3.61 ;
        RECT 8.865 1.19 9.485 1.63 ;
        RECT 8.965 1.05 9.385 1.77 ;
        RECT 8.825 2.95 9.365 3.61 ;
        RECT 7.385 2.95 7.925 3.61 ;
        RECT 7.365 1.19 7.885 1.63 ;
        RECT 7.365 1.05 7.785 1.77 ;
        RECT 7.265 1.05 7.785 1.49 ;
        RECT 5.945 2.95 6.485 3.61 ;
        RECT 4.505 2.95 5.045 3.61 ;
        RECT 3.065 2.95 3.605 3.61 ;
        RECT 1.625 2.95 2.165 3.61 ;
      LAYER METAL1 ;
        RECT 1.78 2.77 13.66 3 ;
        RECT 13.28 1.56 13.66 3 ;
        RECT 7.46 1.56 13.66 1.79 ;
        RECT 12.26 1.39 12.49 1.79 ;
        RECT 11.86 2.77 12.09 3.57 ;
        RECT 10.66 1.39 10.89 1.79 ;
        RECT 10.42 2.77 10.65 3.57 ;
        RECT 9.06 1.39 9.29 1.79 ;
        RECT 8.98 2.77 9.21 3.57 ;
        RECT 7.54 2.77 7.77 3.57 ;
        RECT 7.46 1.39 7.69 1.79 ;
        RECT 6.1 2.77 6.33 3.57 ;
        RECT 4.66 2.77 4.89 3.57 ;
        RECT 3.22 2.77 3.45 3.57 ;
        RECT 1.78 2.77 2.01 3.57 ;
      LAYER METAL2 ;
        RECT 13.28 1.57 13.73 2.99 ;
      LAYER CONT ;
        RECT 1.785 3.17 2.005 3.39 ;
        RECT 3.225 3.17 3.445 3.39 ;
        RECT 4.665 3.17 4.885 3.39 ;
        RECT 6.105 3.17 6.325 3.39 ;
        RECT 7.465 1.45 7.685 1.67 ;
        RECT 7.545 3.17 7.765 3.39 ;
        RECT 8.985 3.17 9.205 3.39 ;
        RECT 9.065 1.45 9.285 1.67 ;
        RECT 10.425 3.17 10.645 3.39 ;
        RECT 10.665 1.45 10.885 1.67 ;
        RECT 11.865 3.17 12.085 3.39 ;
        RECT 12.265 1.45 12.485 1.67 ;
      LAYER VIA12 ;
        RECT 13.34 2.67 13.6 2.93 ;
        RECT 13.34 2.15 13.6 2.41 ;
        RECT 13.34 1.63 13.6 1.89 ;
    END
  END Y
  PIN B
    DIRECTION INOUT ;
    USE SIGNAL ;
    ANTENNAPARTIALMETALAREA 0.2025 LAYER METAL2 ;
    ANTENNAPARTIALCUTAREA 0.1352 LAYER VIA12 ;
    ANTENNAMODEL OXIDE1 ;
      ANTENNAGATEAREA 1.584 LAYER METAL2 ;
      ANTENNAGATEAREA 1.584 LAYER METAL1 ;
      ANTENNAMAXAREACAR 1.360164 LAYER METAL2 ;
      ANTENNAMAXCUTCAR 0.085354 LAYER VIA12 ;
    PORT
      LAYER POLY1 ;
        RECT 7.085 2.07 12.985 2.49 ;
        RECT 12.685 0.97 12.865 2.49 ;
        RECT 12.245 2.07 12.425 3.83 ;
        RECT 11.885 0.97 12.065 2.49 ;
        RECT 11.525 2.07 11.705 3.83 ;
        RECT 11.085 0.97 11.265 2.49 ;
        RECT 10.805 2.07 10.985 3.83 ;
        RECT 10.285 0.97 10.465 2.49 ;
        RECT 10.085 2.07 10.265 3.83 ;
        RECT 9.485 0.97 9.665 2.49 ;
        RECT 9.365 2.07 9.545 3.83 ;
        RECT 8.685 0.97 8.865 2.49 ;
        RECT 8.645 2.07 8.825 3.83 ;
        RECT 7.925 2.07 8.105 3.83 ;
        RECT 7.885 0.97 8.065 2.49 ;
        RECT 7.205 2.07 7.385 3.83 ;
        RECT 7.085 0.83 7.265 2.49 ;
      LAYER METAL1 ;
        RECT 7.495 2.11 12.945 2.45 ;
        RECT 10.36 2.055 10.81 2.505 ;
        RECT 9.63 2.055 10.08 2.505 ;
      LAYER METAL2 ;
        RECT 10.36 2.055 10.81 2.505 ;
        RECT 9.63 2.055 10.08 2.505 ;
      LAYER CONT ;
        RECT 7.555 2.17 7.775 2.39 ;
        RECT 8.285 2.17 8.505 2.39 ;
        RECT 9.015 2.17 9.235 2.39 ;
        RECT 9.745 2.17 9.965 2.39 ;
        RECT 10.475 2.17 10.695 2.39 ;
        RECT 11.205 2.17 11.425 2.39 ;
        RECT 11.935 2.17 12.155 2.39 ;
        RECT 12.665 2.17 12.885 2.39 ;
      LAYER VIA12 ;
        RECT 9.725 2.15 9.985 2.41 ;
        RECT 10.455 2.15 10.715 2.41 ;
    END
  END B
  OBS
    LAYER METAL1 ;
      RECT 0.62 1.56 6.93 1.79 ;
      RECT 6.7 0.93 6.93 1.79 ;
      RECT 5.18 1.09 5.41 1.79 ;
      RECT 3.66 1.09 3.89 1.79 ;
      RECT 2.14 1.09 2.37 1.79 ;
      RECT 0.62 1.09 0.85 1.79 ;
      RECT 13.06 0.93 13.29 1.33 ;
      RECT 11.46 0.93 11.69 1.33 ;
      RECT 9.86 0.93 10.09 1.33 ;
      RECT 8.26 0.93 8.49 1.33 ;
      RECT 6.7 0.93 13.29 1.16 ;
  END
END nand2_8

MACRO nand2b_1
  CLASS CORE ;
  ORIGIN 0 -0.35 ;
  FOREIGN nand2b_1 0 0.35 ;
  SIZE 3.65 BY 4.04 ;
  SYMMETRY X Y ;
  SITE core ;
  PIN VSS
    DIRECTION INOUT ;
    USE GROUND ;
    PORT
      LAYER METAL1 ;
        RECT -0.57 0 4.22 0.7 ;
        RECT 3.05 0 3.28 1.44 ;
        RECT 0.32 0 0.55 1.44 ;
    END
  END VSS
  PIN B
    DIRECTION INOUT ;
    USE SIGNAL ;
    ANTENNAPARTIALCUTAREA 0.0676 LAYER VIA12 ;
    ANTENNAMODEL OXIDE1 ;
      ANTENNAGATEAREA 0.198 LAYER METAL2 ;
      ANTENNAGATEAREA 0.198 LAYER METAL1 ;
      ANTENNAMAXAREACAR 1.022727 LAYER METAL2 ;
      ANTENNAMAXCUTCAR 0.341414 LAYER VIA12 ;
    PORT
      LAYER POLY1 ;
        RECT 2.345 2.155 2.895 2.575 ;
        RECT 2.715 0.83 2.895 2.575 ;
        RECT 2.43 2.155 2.61 3.88 ;
      LAYER METAL1 ;
        RECT 2.33 2.14 2.78 2.59 ;
      LAYER METAL2 ;
        RECT 2.33 2.14 2.78 2.59 ;
      LAYER CONT ;
        RECT 2.445 2.255 2.665 2.475 ;
      LAYER VIA12 ;
        RECT 2.425 2.235 2.685 2.495 ;
    END
  END B
  PIN Y
    DIRECTION INOUT ;
    USE SIGNAL ;
    ANTENNAPARTIALCUTAREA 0.1352 LAYER VIA12 ;
    ANTENNADIFFAREA 0.5676 LAYER METAL2 ;
    ANTENNADIFFAREA 0.5676 LAYER METAL1 ;
    PORT
      LAYER DIFF ;
        RECT 1.89 3 2.43 3.66 ;
        RECT 1.805 1.05 2.285 1.49 ;
      LAYER METAL1 ;
        RECT 2.045 2.82 3.44 3.05 ;
        RECT 3.06 1.67 3.44 3.05 ;
        RECT 2.47 1.67 3.44 1.9 ;
        RECT 2.47 1.22 2.705 1.9 ;
        RECT 1.9 1.22 2.705 1.45 ;
        RECT 2.045 2.82 2.275 3.62 ;
        RECT 1.9 1.09 2.13 1.45 ;
      LAYER METAL2 ;
        RECT 3.06 1.66 3.51 3.08 ;
      LAYER CONT ;
        RECT 1.905 1.16 2.125 1.38 ;
        RECT 2.05 3.22 2.27 3.44 ;
      LAYER VIA12 ;
        RECT 3.12 2.5 3.38 2.76 ;
        RECT 3.12 1.98 3.38 2.24 ;
    END
  END Y
  PIN VDD
    DIRECTION INOUT ;
    USE POWER ;
    PORT
      LAYER METAL1 ;
        RECT -0.57 4.04 4.22 4.74 ;
        RECT 2.765 3.28 2.995 4.74 ;
        RECT 1.325 3.28 1.555 4.74 ;
    END
  END VDD
  PIN A_N
    DIRECTION INOUT ;
    USE SIGNAL ;
    ANTENNAPARTIALCUTAREA 0.0676 LAYER VIA12 ;
    ANTENNAMODEL OXIDE1 ;
      ANTENNAGATEAREA 0.1584 LAYER METAL2 ;
      ANTENNAGATEAREA 0.1584 LAYER METAL1 ;
      ANTENNAMAXAREACAR 1.278409 LAYER METAL2 ;
      ANTENNAMAXCUTCAR 0.426768 LAYER VIA12 ;
    PORT
      LAYER POLY1 ;
        RECT 0.745 2.155 1.305 2.575 ;
        RECT 0.99 2.155 1.17 3.88 ;
        RECT 0.745 0.94 0.925 2.575 ;
      LAYER METAL1 ;
        RECT 0.87 2.14 1.32 2.59 ;
      LAYER METAL2 ;
        RECT 0.87 2.14 1.32 2.59 ;
      LAYER CONT ;
        RECT 0.985 2.255 1.205 2.475 ;
      LAYER VIA12 ;
        RECT 0.965 2.235 1.225 2.495 ;
    END
  END A_N
  OBS
    LAYER METAL1 ;
      RECT 0.605 2.82 0.835 3.62 ;
      RECT 0.605 2.82 1.815 3.05 ;
      RECT 1.585 1.67 1.815 3.05 ;
      RECT 1.585 2.195 1.995 2.535 ;
      RECT 1.12 1.67 1.815 1.9 ;
      RECT 1.12 1.1 1.35 1.9 ;
  END
END nand2b_1

MACRO nand4_1
  CLASS CORE ;
  ORIGIN 0 -0.35 ;
  FOREIGN nand4_1 0 0.35 ;
  SIZE 4.38 BY 4.04 ;
  SYMMETRY X Y ;
  SITE core ;
  PIN VDD
    DIRECTION INOUT ;
    USE POWER ;
    PORT
      LAYER METAL1 ;
        RECT -0.57 4.04 4.95 4.74 ;
        RECT 3.515 3.09 3.745 4.74 ;
        RECT 2.075 3.09 2.305 4.74 ;
        RECT 0.635 3.09 0.865 4.74 ;
    END
  END VDD
  PIN Y
    DIRECTION INOUT ;
    USE SIGNAL ;
    ANTENNAPARTIALCUTAREA 0.0676 LAYER VIA12 ;
    ANTENNADIFFAREA 1.1352 LAYER METAL2 ;
    ANTENNADIFFAREA 0.3564 LAYER METAL1 ;
    PORT
      LAYER DIFF ;
        RECT 2.925 1.05 3.405 1.93 ;
        RECT 2.64 3.05 3.18 3.71 ;
        RECT 1.2 3.05 1.74 3.71 ;
      LAYER METAL1 ;
        RECT 3.06 2.11 3.51 2.86 ;
        RECT 3.06 1.09 3.31 2.86 ;
        RECT 2.685 3.175 3.135 3.625 ;
        RECT 2.795 3.09 3.025 3.67 ;
        RECT 1.245 3.175 1.695 3.625 ;
        RECT 1.355 3.09 1.585 3.67 ;
      LAYER METAL2 ;
        RECT 3.06 2.11 3.51 2.86 ;
        RECT 2.685 3.175 3.415 3.625 ;
        RECT 3.135 2.11 3.415 3.625 ;
        RECT 1.245 3.26 3.415 3.54 ;
        RECT 1.245 3.175 1.695 3.625 ;
      LAYER CONT ;
        RECT 1.36 3.27 1.58 3.49 ;
        RECT 2.8 3.27 3.02 3.49 ;
        RECT 3.085 1.38 3.305 1.6 ;
      LAYER VIA12 ;
        RECT 1.34 3.27 1.6 3.53 ;
        RECT 2.78 3.27 3.04 3.53 ;
        RECT 3.155 2.355 3.415 2.615 ;
    END
  END Y
  PIN VSS
    DIRECTION INOUT ;
    USE GROUND ;
    PORT
      LAYER METAL1 ;
        RECT -0.57 0 4.95 0.7 ;
        RECT 1.07 0 1.3 1.89 ;
    END
  END VSS
  PIN B
    DIRECTION INOUT ;
    USE SIGNAL ;
    ANTENNAPARTIALCUTAREA 0.0676 LAYER VIA12 ;
    ANTENNAMODEL OXIDE1 ;
      ANTENNAGATEAREA 0.2772 LAYER METAL2 ;
      ANTENNAGATEAREA 0.2772 LAYER METAL1 ;
      ANTENNAMAXAREACAR 1.258117 LAYER METAL2 ;
      ANTENNAMAXCUTCAR 0.243867 LAYER VIA12 ;
    PORT
      LAYER POLY1 ;
        RECT 2.315 2.46 2.735 2.88 ;
        RECT 2.46 2.46 2.64 3.93 ;
        RECT 2.315 0.83 2.495 2.88 ;
      LAYER METAL1 ;
        RECT 2.315 2.11 2.78 2.86 ;
      LAYER METAL2 ;
        RECT 2.33 2.11 2.78 2.86 ;
      LAYER CONT ;
        RECT 2.415 2.56 2.635 2.78 ;
      LAYER VIA12 ;
        RECT 2.425 2.355 2.685 2.615 ;
    END
  END B
  PIN C
    DIRECTION INOUT ;
    USE SIGNAL ;
    ANTENNAPARTIALCUTAREA 0.0676 LAYER VIA12 ;
    ANTENNAMODEL OXIDE1 ;
      ANTENNAGATEAREA 0.2772 LAYER METAL2 ;
      ANTENNAGATEAREA 0.2772 LAYER METAL1 ;
      ANTENNAMAXAREACAR 1.258117 LAYER METAL2 ;
      ANTENNAMAXCUTCAR 0.243867 LAYER VIA12 ;
    PORT
      LAYER POLY1 ;
        RECT 1.645 2.46 2.065 2.88 ;
        RECT 1.885 0.83 2.065 2.88 ;
        RECT 1.74 2.46 1.92 3.93 ;
      LAYER METAL1 ;
        RECT 1.6 2.11 2.065 2.86 ;
      LAYER METAL2 ;
        RECT 1.6 2.11 2.05 2.86 ;
      LAYER CONT ;
        RECT 1.745 2.56 1.965 2.78 ;
      LAYER VIA12 ;
        RECT 1.695 2.355 1.955 2.615 ;
    END
  END C
  PIN D
    DIRECTION INOUT ;
    USE SIGNAL ;
    ANTENNAPARTIALCUTAREA 0.0676 LAYER VIA12 ;
    ANTENNAMODEL OXIDE1 ;
      ANTENNAGATEAREA 0.2772 LAYER METAL2 ;
      ANTENNAGATEAREA 0.2772 LAYER METAL1 ;
      ANTENNAMAXAREACAR 1.217532 LAYER METAL2 ;
      ANTENNAMAXCUTCAR 0.243867 LAYER VIA12 ;
    PORT
      LAYER POLY1 ;
        RECT 0.14 2.03 1.635 2.21 ;
        RECT 1.455 0.83 1.635 2.21 ;
        RECT 1.02 2.77 1.2 3.93 ;
        RECT 0.14 2.77 1.2 2.95 ;
        RECT 0.14 2.03 0.59 2.95 ;
      LAYER METAL1 ;
        RECT 0.14 2.11 0.59 2.86 ;
      LAYER METAL2 ;
        RECT 0.14 2.11 0.59 2.86 ;
      LAYER CONT ;
        RECT 0.255 2.375 0.475 2.595 ;
      LAYER VIA12 ;
        RECT 0.235 2.355 0.495 2.615 ;
    END
  END D
  PIN A
    DIRECTION INOUT ;
    USE SIGNAL ;
    ANTENNAPARTIALCUTAREA 0.0676 LAYER VIA12 ;
    ANTENNAMODEL OXIDE1 ;
      ANTENNAGATEAREA 0.2772 LAYER METAL2 ;
      ANTENNAGATEAREA 0.2772 LAYER METAL1 ;
      ANTENNAMAXAREACAR 1.136364 LAYER METAL2 ;
      ANTENNAMAXCUTCAR 0.243867 LAYER VIA12 ;
    PORT
      LAYER POLY1 ;
        RECT 3.18 2.77 4.24 2.95 ;
        RECT 3.79 2.03 4.24 2.95 ;
        RECT 2.745 2.03 4.24 2.21 ;
        RECT 3.18 2.77 3.36 3.93 ;
        RECT 2.745 0.83 2.925 2.21 ;
      LAYER METAL1 ;
        RECT 3.79 2.15 4.24 2.85 ;
      LAYER METAL2 ;
        RECT 3.79 2.15 4.24 2.85 ;
      LAYER CONT ;
        RECT 3.905 2.39 4.125 2.61 ;
      LAYER VIA12 ;
        RECT 3.885 2.37 4.145 2.63 ;
    END
  END A
  PROPERTY deviceLevel "CatenaDesignType" ;
  PROPERTY CatenaDesignType "deviceLevel" ;
END nand4_1

MACRO nor2_1
  CLASS CORE ;
  ORIGIN 0 -0.35 ;
  FOREIGN nor2_1 0 0.35 ;
  SIZE 4.38 BY 4.04 ;
  SYMMETRY X Y ;
  SITE core ;
  PIN Y
    DIRECTION INOUT ;
    USE SIGNAL ;
    ANTENNAPARTIALCUTAREA 0.2028 LAYER VIA12 ;
    ANTENNADIFFAREA 0.5768 LAYER METAL2 ;
    ANTENNADIFFAREA 0.5768 LAYER METAL1 ;
    PORT
      LAYER DIFF ;
        RECT 2.64 2.95 3.18 3.61 ;
        RECT 1.88 1.05 2.5 1.27 ;
        RECT 1.98 0.95 2.4 1.37 ;
      LAYER METAL1 ;
        RECT 2.795 2.77 4.205 3 ;
        RECT 3.825 1.56 4.205 3 ;
        RECT 2.075 1.56 4.205 1.79 ;
        RECT 2.795 2.77 3.025 3.33 ;
        RECT 2.075 0.99 2.305 1.79 ;
      LAYER METAL2 ;
        RECT 3.79 1.575 4.24 2.995 ;
      LAYER CONT ;
        RECT 2.08 1.05 2.3 1.27 ;
        RECT 2.8 3.05 3.02 3.27 ;
      LAYER VIA12 ;
        RECT 3.885 2.675 4.145 2.935 ;
        RECT 3.885 2.155 4.145 2.415 ;
        RECT 3.885 1.635 4.145 1.895 ;
    END
  END Y
  PIN VSS
    DIRECTION INOUT ;
    USE GROUND ;
    PORT
      LAYER METAL1 ;
        RECT -0.57 0 4.95 0.7 ;
        RECT 2.875 0 3.105 1.33 ;
        RECT 1.275 0 1.505 1.33 ;
    END
  END VSS
  PIN A
    DIRECTION INOUT ;
    USE SIGNAL ;
    ANTENNAPARTIALMETALAREA 0.2025 LAYER METAL2 ;
    ANTENNAPARTIALMETALAREA 0.2025 LAYER METAL1 ;
    ANTENNAPARTIALCUTAREA 0.1352 LAYER VIA12 ;
    ANTENNAMODEL OXIDE1 ;
      ANTENNAGATEAREA 0.2772 LAYER METAL2 ;
      ANTENNAGATEAREA 0.2772 LAYER METAL1 ;
      ANTENNAMAXAREACAR 2.191558 LAYER METAL2 ;
      ANTENNAMAXAREACAR 0.730519 LAYER METAL1 ;
      ANTENNAMAXCUTCAR 0.487734 LAYER VIA12 ;
    PORT
      LAYER POLY1 ;
        RECT 0.885 1.965 2.035 2.465 ;
        RECT 1.74 1.965 1.92 3.83 ;
        RECT 1.7 0.83 1.88 2.465 ;
        RECT 1.02 1.965 1.2 3.83 ;
      LAYER METAL1 ;
        RECT 1.6 2.03 2.05 2.48 ;
        RECT 0.87 2.03 1.32 2.48 ;
      LAYER METAL2 ;
        RECT 1.6 2.03 2.05 2.48 ;
        RECT 0.87 2.03 1.32 2.48 ;
      LAYER CONT ;
        RECT 0.985 2.145 1.205 2.365 ;
        RECT 1.715 2.145 1.935 2.365 ;
      LAYER VIA12 ;
        RECT 0.965 2.125 1.225 2.385 ;
        RECT 1.695 2.125 1.955 2.385 ;
    END
  END A
  PIN VDD
    DIRECTION INOUT ;
    USE POWER ;
    PORT
      LAYER METAL1 ;
        RECT -0.57 4.04 4.95 4.74 ;
        RECT 1.355 3.23 1.585 4.74 ;
    END
  END VDD
  PIN B
    DIRECTION INOUT ;
    USE SIGNAL ;
    ANTENNAPARTIALMETALAREA 0.2025 LAYER METAL2 ;
    ANTENNAPARTIALMETALAREA 0.2025 LAYER METAL1 ;
    ANTENNAPARTIALCUTAREA 0.1352 LAYER VIA12 ;
    ANTENNAMODEL OXIDE1 ;
      ANTENNAGATEAREA 0.2772 LAYER METAL2 ;
      ANTENNAGATEAREA 0.2772 LAYER METAL1 ;
      ANTENNAMAXAREACAR 2.191558 LAYER METAL2 ;
      ANTENNAMAXAREACAR 0.730519 LAYER METAL1 ;
      ANTENNAMAXCUTCAR 0.487734 LAYER VIA12 ;
    PORT
      LAYER POLY1 ;
        RECT 2.345 2.045 3.495 2.465 ;
        RECT 2.345 1.965 3.49 2.465 ;
        RECT 3.18 1.965 3.36 3.83 ;
        RECT 2.5 0.83 2.68 2.465 ;
        RECT 2.46 1.965 2.64 3.83 ;
      LAYER METAL1 ;
        RECT 3.06 2.03 3.51 2.48 ;
        RECT 2.33 2.03 2.78 2.48 ;
      LAYER METAL2 ;
        RECT 3.06 2.03 3.51 2.48 ;
        RECT 2.33 2.03 2.78 2.48 ;
      LAYER CONT ;
        RECT 2.445 2.145 2.665 2.365 ;
        RECT 3.175 2.145 3.395 2.365 ;
      LAYER VIA12 ;
        RECT 2.425 2.125 2.685 2.385 ;
        RECT 3.155 2.125 3.415 2.385 ;
    END
  END B
  OBS
    LAYER METAL1 ;
      RECT 2.075 3.56 3.745 3.79 ;
      RECT 3.515 3.23 3.745 3.79 ;
      RECT 0.635 2.77 0.865 3.57 ;
      RECT 2.075 2.77 2.305 3.79 ;
      RECT 0.635 2.77 2.305 3 ;
  END
END nor2_1

MACRO nor2_4
  CLASS CORE ;
  ORIGIN 0 -0.35 ;
  FOREIGN nor2_4 0 0.35 ;
  SIZE 13.14 BY 4.04 ;
  SYMMETRY X Y ;
  SITE core ;
  PIN Y
    DIRECTION INOUT ;
    USE SIGNAL ;
    ANTENNAPARTIALCUTAREA 0.2028 LAYER VIA12 ;
    ANTENNADIFFAREA 2.3072 LAYER METAL2 ;
    ANTENNADIFFAREA 2.3072 LAYER METAL1 ;
    PORT
      LAYER DIFF ;
        RECT 11.34 2.95 11.88 3.61 ;
        RECT 9.9 2.95 10.44 3.61 ;
        RECT 8.66 1.05 9.28 1.27 ;
        RECT 8.76 0.95 9.18 1.37 ;
        RECT 8.46 2.95 9 3.61 ;
        RECT 7.06 1.05 7.68 1.27 ;
        RECT 7.16 0.95 7.58 1.37 ;
        RECT 7.02 2.95 7.56 3.61 ;
        RECT 5.46 1.05 6.08 1.27 ;
        RECT 5.56 0.95 5.98 1.37 ;
        RECT 3.86 1.05 4.48 1.27 ;
        RECT 3.96 0.95 4.38 1.37 ;
      LAYER METAL1 ;
        RECT 7.175 2.77 12.93 3 ;
        RECT 12.55 1.56 12.93 3 ;
        RECT 4.055 1.56 12.93 1.79 ;
        RECT 11.495 2.77 11.725 3.33 ;
        RECT 10.055 2.77 10.285 3.33 ;
        RECT 8.855 0.99 9.085 1.79 ;
        RECT 8.615 2.77 8.845 3.33 ;
        RECT 7.255 0.99 7.485 1.79 ;
        RECT 7.175 2.77 7.405 3.33 ;
        RECT 5.655 0.99 5.885 1.79 ;
        RECT 4.055 0.99 4.285 1.79 ;
      LAYER METAL2 ;
        RECT 12.55 1.565 13 2.985 ;
      LAYER CONT ;
        RECT 4.06 1.05 4.28 1.27 ;
        RECT 5.66 1.05 5.88 1.27 ;
        RECT 7.18 3.05 7.4 3.27 ;
        RECT 7.26 1.05 7.48 1.27 ;
        RECT 8.62 3.05 8.84 3.27 ;
        RECT 8.86 1.05 9.08 1.27 ;
        RECT 10.06 3.05 10.28 3.27 ;
        RECT 11.5 3.05 11.72 3.27 ;
      LAYER VIA12 ;
        RECT 12.61 2.665 12.87 2.925 ;
        RECT 12.61 2.145 12.87 2.405 ;
        RECT 12.61 1.625 12.87 1.885 ;
    END
  END Y
  PIN VSS
    DIRECTION INOUT ;
    USE GROUND ;
    PORT
      LAYER METAL1 ;
        RECT -0.57 0 13.71 0.7 ;
        RECT 9.655 0 9.885 1.33 ;
        RECT 8.055 0 8.285 1.33 ;
        RECT 6.455 0 6.685 1.33 ;
        RECT 4.855 0 5.085 1.33 ;
        RECT 3.255 0 3.485 1.33 ;
    END
  END VSS
  PIN A
    DIRECTION INOUT ;
    USE SIGNAL ;
    ANTENNAPARTIALMETALAREA 0.405 LAYER METAL2 ;
    ANTENNAPARTIALCUTAREA 0.2028 LAYER VIA12 ;
    ANTENNAMODEL OXIDE1 ;
      ANTENNAGATEAREA 1.1088 LAYER METAL2 ;
      ANTENNAGATEAREA 1.1088 LAYER METAL1 ;
      ANTENNAMAXAREACAR 2.325487 LAYER METAL2 ;
      ANTENNAMAXCUTCAR 0.1829 LAYER VIA12 ;
    PORT
      LAYER POLY1 ;
        RECT 1.08 2.065 6.415 2.485 ;
        RECT 6.12 2.03 6.3 3.83 ;
        RECT 6.08 0.83 6.26 2.53 ;
        RECT 1.08 2.03 6.3 2.53 ;
        RECT 5.4 2.03 5.58 3.83 ;
        RECT 5.28 0.83 5.46 2.53 ;
        RECT 4.68 2.03 4.86 3.83 ;
        RECT 4.48 0.83 4.66 2.53 ;
        RECT 3.96 2.03 4.14 3.83 ;
        RECT 3.68 0.83 3.86 2.53 ;
        RECT 3.24 2.03 3.42 3.83 ;
        RECT 2.52 2.03 2.7 3.83 ;
        RECT 1.8 2.03 1.98 3.83 ;
        RECT 1.08 2.03 1.26 3.83 ;
      LAYER METAL1 ;
        RECT 1.6 2.05 6.43 2.5 ;
      LAYER METAL2 ;
        RECT 5.98 2.05 6.43 2.5 ;
        RECT 3.79 2.05 4.24 2.5 ;
        RECT 1.6 2.05 2.05 2.5 ;
      LAYER CONT ;
        RECT 1.715 2.165 1.935 2.385 ;
        RECT 2.445 2.165 2.665 2.385 ;
        RECT 3.175 2.165 3.395 2.385 ;
        RECT 3.905 2.165 4.125 2.385 ;
        RECT 4.635 2.165 4.855 2.385 ;
        RECT 5.365 2.165 5.585 2.385 ;
        RECT 6.095 2.165 6.315 2.385 ;
      LAYER VIA12 ;
        RECT 1.695 2.145 1.955 2.405 ;
        RECT 3.885 2.145 4.145 2.405 ;
        RECT 6.075 2.145 6.335 2.405 ;
    END
  END A
  PIN VDD
    DIRECTION INOUT ;
    USE POWER ;
    PORT
      LAYER METAL1 ;
        RECT -0.57 4.04 13.71 4.74 ;
        RECT 5.735 3.23 5.965 4.74 ;
        RECT 4.295 3.23 4.525 4.74 ;
        RECT 2.855 3.23 3.085 4.74 ;
        RECT 1.415 3.23 1.645 4.74 ;
    END
  END VDD
  PIN B
    DIRECTION INOUT ;
    USE SIGNAL ;
    ANTENNAPARTIALMETALAREA 0.405 LAYER METAL2 ;
    ANTENNAPARTIALCUTAREA 0.2028 LAYER VIA12 ;
    ANTENNAMODEL OXIDE1 ;
      ANTENNAGATEAREA 1.1088 LAYER METAL2 ;
      ANTENNAGATEAREA 1.1088 LAYER METAL1 ;
      ANTENNAMAXAREACAR 2.325487 LAYER METAL2 ;
      ANTENNAMAXCUTCAR 0.1829 LAYER VIA12 ;
    PORT
      LAYER POLY1 ;
        RECT 11.88 2.03 12.06 3.83 ;
        RECT 6.84 2.03 12.06 2.53 ;
        RECT 11.16 2.03 11.34 3.83 ;
        RECT 10.44 2.03 10.62 3.83 ;
        RECT 9.72 2.03 9.9 3.83 ;
        RECT 9.28 0.83 9.46 2.53 ;
        RECT 9 2.03 9.18 3.83 ;
        RECT 8.48 0.83 8.66 2.53 ;
        RECT 8.28 2.03 8.46 3.83 ;
        RECT 7.68 0.83 7.86 2.53 ;
        RECT 7.56 2.03 7.74 3.83 ;
        RECT 6.88 0.83 7.06 2.53 ;
        RECT 6.84 2.03 7.02 3.83 ;
        RECT 6.725 2.065 12.06 2.485 ;
      LAYER METAL1 ;
        RECT 6.71 2.05 11.54 2.5 ;
      LAYER METAL2 ;
        RECT 11.09 2.05 11.54 2.5 ;
        RECT 8.9 2.05 9.35 2.5 ;
        RECT 6.71 2.05 7.16 2.5 ;
      LAYER CONT ;
        RECT 6.825 2.165 7.045 2.385 ;
        RECT 7.555 2.165 7.775 2.385 ;
        RECT 8.285 2.165 8.505 2.385 ;
        RECT 9.015 2.165 9.235 2.385 ;
        RECT 9.745 2.165 9.965 2.385 ;
        RECT 10.475 2.165 10.695 2.385 ;
        RECT 11.205 2.165 11.425 2.385 ;
      LAYER VIA12 ;
        RECT 6.805 2.145 7.065 2.405 ;
        RECT 8.995 2.145 9.255 2.405 ;
        RECT 11.185 2.145 11.445 2.405 ;
    END
  END B
  OBS
    LAYER METAL1 ;
      RECT 6.455 3.56 12.445 3.79 ;
      RECT 12.215 3.23 12.445 3.79 ;
      RECT 5.015 2.77 5.245 3.57 ;
      RECT 3.575 2.77 3.805 3.57 ;
      RECT 2.135 2.77 2.365 3.57 ;
      RECT 0.695 2.77 0.925 3.57 ;
      RECT 10.775 3.23 11.005 3.79 ;
      RECT 9.335 3.23 9.565 3.79 ;
      RECT 7.895 3.23 8.125 3.79 ;
      RECT 6.455 2.77 6.685 3.79 ;
      RECT 0.695 2.77 6.685 3 ;
  END
END nor2_4

MACRO nor2_8
  CLASS CORE ;
  ORIGIN 0 -0.35 ;
  FOREIGN nor2_8 0 0.35 ;
  SIZE 24.82 BY 4.04 ;
  SYMMETRY X Y ;
  SITE core ;
  PIN Y
    DIRECTION INOUT ;
    USE SIGNAL ;
    ANTENNAPARTIALCUTAREA 0.2028 LAYER VIA12 ;
    ANTENNADIFFAREA 4.6144 LAYER METAL2 ;
    ANTENNADIFFAREA 4.6144 LAYER METAL1 ;
    PORT
      LAYER DIFF ;
        RECT 22.77 2.95 23.31 3.61 ;
        RECT 21.33 2.95 21.87 3.61 ;
        RECT 19.89 2.95 20.43 3.61 ;
        RECT 18.45 2.95 18.99 3.61 ;
        RECT 17.53 1.05 18.15 1.27 ;
        RECT 17.63 0.95 18.05 1.37 ;
        RECT 17.01 2.95 17.55 3.61 ;
        RECT 15.93 1.05 16.55 1.27 ;
        RECT 16.03 0.95 16.45 1.37 ;
        RECT 15.57 2.95 16.11 3.61 ;
        RECT 14.33 1.05 14.95 1.27 ;
        RECT 14.43 0.95 14.85 1.37 ;
        RECT 14.13 2.95 14.67 3.61 ;
        RECT 12.73 1.05 13.35 1.27 ;
        RECT 12.83 0.95 13.25 1.37 ;
        RECT 12.69 2.95 13.23 3.61 ;
        RECT 11.13 1.05 11.75 1.27 ;
        RECT 11.23 0.95 11.65 1.37 ;
        RECT 9.53 1.05 10.15 1.27 ;
        RECT 9.63 0.95 10.05 1.37 ;
        RECT 7.93 1.05 8.55 1.27 ;
        RECT 8.03 0.95 8.45 1.37 ;
        RECT 6.33 1.05 6.95 1.27 ;
        RECT 6.43 0.95 6.85 1.37 ;
      LAYER METAL1 ;
        RECT 12.845 2.77 24.195 3 ;
        RECT 23.57 1.56 24.195 3 ;
        RECT 6.525 1.56 24.195 1.79 ;
        RECT 22.925 2.77 23.155 3.33 ;
        RECT 21.485 2.77 21.715 3.33 ;
        RECT 20.045 2.77 20.275 3.33 ;
        RECT 18.605 2.77 18.835 3.33 ;
        RECT 17.725 0.99 17.955 1.79 ;
        RECT 17.165 2.77 17.395 3.33 ;
        RECT 16.125 0.99 16.355 1.79 ;
        RECT 15.725 2.77 15.955 3.33 ;
        RECT 14.525 0.99 14.755 1.79 ;
        RECT 14.285 2.77 14.515 3.33 ;
        RECT 12.925 0.99 13.155 1.79 ;
        RECT 12.845 2.77 13.075 3.33 ;
        RECT 11.325 0.99 11.555 1.79 ;
        RECT 9.725 0.99 9.955 1.79 ;
        RECT 8.125 0.99 8.355 1.79 ;
        RECT 6.525 0.99 6.755 1.79 ;
      LAYER METAL2 ;
        RECT 23.5 1.56 23.95 3 ;
      LAYER CONT ;
        RECT 6.53 1.05 6.75 1.27 ;
        RECT 8.13 1.05 8.35 1.27 ;
        RECT 9.73 1.05 9.95 1.27 ;
        RECT 11.33 1.05 11.55 1.27 ;
        RECT 12.85 3.05 13.07 3.27 ;
        RECT 12.93 1.05 13.15 1.27 ;
        RECT 14.29 3.05 14.51 3.27 ;
        RECT 14.53 1.05 14.75 1.27 ;
        RECT 15.73 3.05 15.95 3.27 ;
        RECT 16.13 1.05 16.35 1.27 ;
        RECT 17.17 3.05 17.39 3.27 ;
        RECT 17.73 1.05 17.95 1.27 ;
        RECT 18.61 3.05 18.83 3.27 ;
        RECT 20.05 3.05 20.27 3.27 ;
        RECT 21.49 3.05 21.71 3.27 ;
        RECT 22.93 3.05 23.15 3.27 ;
      LAYER VIA12 ;
        RECT 23.63 2.67 23.89 2.93 ;
        RECT 23.63 2.15 23.89 2.41 ;
        RECT 23.63 1.63 23.89 1.89 ;
    END
  END Y
  PIN VSS
    DIRECTION INOUT ;
    USE GROUND ;
    PORT
      LAYER METAL1 ;
        RECT -0.57 0 25.39 0.7 ;
        RECT 18.525 0 18.755 1.33 ;
        RECT 16.925 0 17.155 1.33 ;
        RECT 15.325 0 15.555 1.33 ;
        RECT 13.725 0 13.955 1.33 ;
        RECT 12.125 0 12.355 1.33 ;
        RECT 10.525 0 10.755 1.33 ;
        RECT 8.925 0 9.155 1.33 ;
        RECT 7.325 0 7.555 1.33 ;
        RECT 5.725 0 5.955 1.33 ;
    END
  END VSS
  PIN A
    DIRECTION INOUT ;
    USE SIGNAL ;
    ANTENNAPARTIALMETALAREA 0.2025 LAYER METAL2 ;
    ANTENNAPARTIALCUTAREA 0.1352 LAYER VIA12 ;
    ANTENNAMODEL OXIDE1 ;
      ANTENNAGATEAREA 2.2176 LAYER METAL2 ;
      ANTENNAGATEAREA 2.2176 LAYER METAL1 ;
      ANTENNAMAXAREACAR 2.25345 LAYER METAL2 ;
      ANTENNAMAXCUTCAR 0.060967 LAYER VIA12 ;
    PORT
      LAYER POLY1 ;
        RECT 11.79 2.055 11.97 3.83 ;
        RECT 11.75 0.83 11.93 2.505 ;
        RECT 0.99 2.055 11.97 2.505 ;
        RECT 11.07 2.055 11.25 3.83 ;
        RECT 10.95 0.83 11.13 2.505 ;
        RECT 10.35 2.055 10.53 3.83 ;
        RECT 10.15 0.83 10.33 2.505 ;
        RECT 9.63 2.055 9.81 3.83 ;
        RECT 9.35 0.83 9.53 2.505 ;
        RECT 8.91 2.055 9.09 3.83 ;
        RECT 8.55 0.83 8.73 2.505 ;
        RECT 8.19 2.055 8.37 3.83 ;
        RECT 7.75 0.83 7.93 2.505 ;
        RECT 7.47 2.055 7.65 3.83 ;
        RECT 6.95 0.83 7.13 2.505 ;
        RECT 6.75 2.055 6.93 3.83 ;
        RECT 6.15 0.83 6.33 2.505 ;
        RECT 6.03 2.055 6.21 3.83 ;
        RECT 5.31 2.055 5.49 3.83 ;
        RECT 4.59 2.055 4.77 3.83 ;
        RECT 3.87 2.055 4.05 3.83 ;
        RECT 3.15 2.055 3.33 3.83 ;
        RECT 2.43 2.055 2.61 3.83 ;
        RECT 1.71 2.055 1.89 3.83 ;
        RECT 0.99 2.055 1.17 3.83 ;
        RECT 0.885 2.07 11.97 2.49 ;
      LAYER METAL1 ;
        RECT 0.87 2.055 11.525 2.505 ;
      LAYER METAL2 ;
        RECT 1.6 2.055 2.05 2.505 ;
        RECT 0.87 2.055 1.32 2.505 ;
      LAYER CONT ;
        RECT 0.985 2.17 1.205 2.39 ;
        RECT 1.715 2.17 1.935 2.39 ;
        RECT 2.445 2.17 2.665 2.39 ;
        RECT 3.175 2.17 3.395 2.39 ;
        RECT 3.905 2.17 4.125 2.39 ;
        RECT 4.635 2.17 4.855 2.39 ;
        RECT 5.365 2.17 5.585 2.39 ;
        RECT 6.095 2.17 6.315 2.39 ;
        RECT 6.825 2.17 7.045 2.39 ;
        RECT 7.555 2.17 7.775 2.39 ;
        RECT 8.285 2.17 8.505 2.39 ;
        RECT 9.015 2.17 9.235 2.39 ;
        RECT 9.745 2.17 9.965 2.39 ;
        RECT 10.475 2.17 10.695 2.39 ;
        RECT 11.205 2.17 11.425 2.39 ;
      LAYER VIA12 ;
        RECT 0.965 2.15 1.225 2.41 ;
        RECT 1.695 2.15 1.955 2.41 ;
    END
  END A
  PIN VDD
    DIRECTION INOUT ;
    USE POWER ;
    PORT
      LAYER METAL1 ;
        RECT -0.57 4.04 25.39 4.74 ;
        RECT 11.405 3.23 11.635 4.74 ;
        RECT 9.965 3.23 10.195 4.74 ;
        RECT 8.525 3.23 8.755 4.74 ;
        RECT 7.085 3.23 7.315 4.74 ;
        RECT 5.645 3.23 5.875 4.74 ;
        RECT 4.205 3.23 4.435 4.74 ;
        RECT 2.765 3.23 2.995 4.74 ;
        RECT 1.325 3.23 1.555 4.74 ;
    END
  END VDD
  PIN B
    DIRECTION INOUT ;
    USE SIGNAL ;
    ANTENNAPARTIALMETALAREA 0.2025 LAYER METAL2 ;
    ANTENNAPARTIALCUTAREA 0.1352 LAYER VIA12 ;
    ANTENNAMODEL OXIDE1 ;
      ANTENNAGATEAREA 2.2176 LAYER METAL2 ;
      ANTENNAGATEAREA 2.2176 LAYER METAL1 ;
      ANTENNAMAXAREACAR 2.25345 LAYER METAL2 ;
      ANTENNAMAXCUTCAR 0.060967 LAYER VIA12 ;
    PORT
      LAYER POLY1 ;
        RECT 23.31 2.055 23.49 3.83 ;
        RECT 12.51 2.055 23.49 2.505 ;
        RECT 22.59 2.055 22.77 3.83 ;
        RECT 21.87 2.055 22.05 3.83 ;
        RECT 21.15 2.055 21.33 3.83 ;
        RECT 20.43 2.055 20.61 3.83 ;
        RECT 19.71 2.055 19.89 3.83 ;
        RECT 18.99 2.055 19.17 3.83 ;
        RECT 18.27 2.055 18.45 3.83 ;
        RECT 18.15 0.83 18.33 2.505 ;
        RECT 17.55 2.055 17.73 3.83 ;
        RECT 17.35 0.83 17.53 2.505 ;
        RECT 16.83 2.055 17.01 3.83 ;
        RECT 16.55 0.83 16.73 2.505 ;
        RECT 16.11 2.055 16.29 3.83 ;
        RECT 15.75 0.83 15.93 2.505 ;
        RECT 15.39 2.055 15.57 3.83 ;
        RECT 14.95 0.83 15.13 2.505 ;
        RECT 14.67 2.055 14.85 3.83 ;
        RECT 14.15 0.83 14.33 2.505 ;
        RECT 13.95 2.055 14.13 3.83 ;
        RECT 13.35 0.83 13.53 2.505 ;
        RECT 13.23 2.055 13.41 3.83 ;
        RECT 12.55 0.83 12.73 2.505 ;
        RECT 12.51 2.055 12.69 3.83 ;
      LAYER METAL1 ;
        RECT 12.55 2.055 23.205 2.505 ;
      LAYER METAL2 ;
        RECT 13.28 2.055 13.73 2.505 ;
        RECT 12.55 2.055 13 2.505 ;
      LAYER CONT ;
        RECT 12.665 2.17 12.885 2.39 ;
        RECT 13.395 2.17 13.615 2.39 ;
        RECT 14.125 2.17 14.345 2.39 ;
        RECT 14.855 2.17 15.075 2.39 ;
        RECT 15.585 2.17 15.805 2.39 ;
        RECT 16.315 2.17 16.535 2.39 ;
        RECT 17.045 2.17 17.265 2.39 ;
        RECT 17.775 2.17 17.995 2.39 ;
        RECT 18.505 2.17 18.725 2.39 ;
        RECT 19.235 2.17 19.455 2.39 ;
        RECT 19.965 2.17 20.185 2.39 ;
        RECT 20.695 2.17 20.915 2.39 ;
        RECT 21.425 2.17 21.645 2.39 ;
        RECT 22.155 2.17 22.375 2.39 ;
        RECT 22.885 2.17 23.105 2.39 ;
      LAYER VIA12 ;
        RECT 12.645 2.15 12.905 2.41 ;
        RECT 13.375 2.15 13.635 2.41 ;
    END
  END B
  OBS
    LAYER METAL1 ;
      RECT 12.125 3.56 23.875 3.79 ;
      RECT 23.645 3.23 23.875 3.79 ;
      RECT 10.685 2.77 10.915 3.57 ;
      RECT 9.245 2.77 9.475 3.57 ;
      RECT 7.805 2.77 8.035 3.57 ;
      RECT 6.365 2.77 6.595 3.57 ;
      RECT 4.925 2.77 5.155 3.57 ;
      RECT 3.485 2.77 3.715 3.57 ;
      RECT 2.045 2.77 2.275 3.57 ;
      RECT 0.605 2.77 0.835 3.57 ;
      RECT 22.205 3.23 22.435 3.79 ;
      RECT 20.765 3.23 20.995 3.79 ;
      RECT 19.325 3.23 19.555 3.79 ;
      RECT 17.885 3.23 18.115 3.79 ;
      RECT 16.445 3.23 16.675 3.79 ;
      RECT 15.005 3.23 15.235 3.79 ;
      RECT 13.565 3.23 13.795 3.79 ;
      RECT 12.125 2.77 12.355 3.79 ;
      RECT 0.605 2.77 12.355 3 ;
  END
END nor2_8

MACRO o21ai_1
  CLASS CORE ;
  ORIGIN 0 -0.35 ;
  FOREIGN o21ai_1 0 0.35 ;
  SIZE 6.57 BY 4.04 ;
  SYMMETRY X Y ;
  SITE core ;
  PIN VSS
    DIRECTION INOUT ;
    USE GROUND ;
    PORT
      LAYER METAL1 ;
        RECT -0.57 0 7.14 0.7 ;
        RECT 2.935 0 3.165 1.33 ;
        RECT 1.335 0 1.565 1.33 ;
    END
  END VSS
  PIN A2
    DIRECTION INOUT ;
    USE SIGNAL ;
    ANTENNAPARTIALCUTAREA 0.0676 LAYER VIA12 ;
    ANTENNAMODEL OXIDE1 ;
      ANTENNAGATEAREA 0.3168 LAYER METAL2 ;
      ANTENNAGATEAREA 0.3168 LAYER METAL1 ;
      ANTENNAMAXAREACAR 1.40625 LAYER METAL2 ;
      ANTENNAMAXCUTCAR 0.213384 LAYER VIA12 ;
    PORT
      LAYER POLY1 ;
        RECT 2.345 2.07 3.54 2.49 ;
        RECT 3.36 0.83 3.54 2.49 ;
        RECT 3.275 2.07 3.455 3.83 ;
        RECT 2.56 0.83 2.74 2.49 ;
        RECT 2.555 2.07 2.735 3.83 ;
      LAYER METAL1 ;
        RECT 2.33 2.11 3.455 2.47 ;
        RECT 2.33 2.055 2.78 2.505 ;
      LAYER METAL2 ;
        RECT 2.33 2.055 2.78 2.505 ;
      LAYER CONT ;
        RECT 2.445 2.17 2.665 2.39 ;
        RECT 3.175 2.17 3.395 2.39 ;
      LAYER VIA12 ;
        RECT 2.425 2.15 2.685 2.41 ;
    END
  END A2
  PIN Y
    DIRECTION INOUT ;
    USE SIGNAL ;
    ANTENNAPARTIALCUTAREA 0.0676 LAYER VIA12 ;
    ANTENNADIFFAREA 0.8844 LAYER METAL2 ;
    ANTENNADIFFAREA 0.8844 LAYER METAL1 ;
    PORT
      LAYER DIFF ;
        RECT 5.455 1.05 5.935 1.49 ;
        RECT 5.455 2.95 5.935 3.61 ;
        RECT 2.735 2.95 3.275 3.61 ;
      LAYER METAL1 ;
        RECT 5.61 2.77 6.395 3.46 ;
        RECT 6.015 1.09 6.395 3.46 ;
        RECT 5.61 1.09 6.395 1.45 ;
        RECT 2.89 2.77 6.395 3 ;
        RECT 2.89 2.77 3.12 3.33 ;
      LAYER METAL2 ;
        RECT 5.98 2.055 6.43 2.505 ;
      LAYER CONT ;
        RECT 2.895 3.05 3.115 3.27 ;
        RECT 5.615 3.17 5.835 3.39 ;
        RECT 5.615 1.16 5.835 1.38 ;
      LAYER VIA12 ;
        RECT 6.075 2.15 6.335 2.41 ;
    END
  END Y
  PIN B1
    DIRECTION INOUT ;
    USE SIGNAL ;
    ANTENNAPARTIALCUTAREA 0.0676 LAYER VIA12 ;
    ANTENNAMODEL OXIDE1 ;
      ANTENNAGATEAREA 0.198 LAYER METAL2 ;
      ANTENNAGATEAREA 0.198 LAYER METAL1 ;
      ANTENNAMAXAREACAR 1.022727 LAYER METAL2 ;
      ANTENNAMAXCUTCAR 0.341414 LAYER VIA12 ;
    PORT
      LAYER POLY1 ;
        RECT 5.265 2.07 5.685 2.49 ;
        RECT 5.275 0.83 5.455 3.83 ;
      LAYER METAL1 ;
        RECT 5.25 2.055 5.7 2.505 ;
      LAYER METAL2 ;
        RECT 5.25 2.055 5.7 2.505 ;
      LAYER CONT ;
        RECT 5.365 2.17 5.585 2.39 ;
      LAYER VIA12 ;
        RECT 5.345 2.15 5.605 2.41 ;
    END
  END B1
  PIN A1
    DIRECTION INOUT ;
    USE SIGNAL ;
    ANTENNAPARTIALCUTAREA 0.0676 LAYER VIA12 ;
    ANTENNAMODEL OXIDE1 ;
      ANTENNAGATEAREA 0.3168 LAYER METAL2 ;
      ANTENNAGATEAREA 0.3168 LAYER METAL1 ;
      ANTENNAMAXAREACAR 1.40625 LAYER METAL2 ;
      ANTENNAMAXCUTCAR 0.213384 LAYER VIA12 ;
    PORT
      LAYER POLY1 ;
        RECT 0.885 2.07 2.035 2.49 ;
        RECT 1.835 2.07 2.015 3.83 ;
        RECT 1.76 0.83 1.94 2.49 ;
        RECT 1.115 2.07 1.295 3.83 ;
        RECT 0.96 0.83 1.14 2.49 ;
      LAYER METAL1 ;
        RECT 0.87 2.11 1.995 2.47 ;
        RECT 0.87 2.055 1.32 2.505 ;
      LAYER METAL2 ;
        RECT 0.87 2.055 1.32 2.505 ;
      LAYER CONT ;
        RECT 0.985 2.17 1.205 2.39 ;
        RECT 1.715 2.17 1.935 2.39 ;
      LAYER VIA12 ;
        RECT 0.965 2.15 1.225 2.41 ;
    END
  END A1
  PIN VDD
    DIRECTION INOUT ;
    USE POWER ;
    PORT
      LAYER METAL1 ;
        RECT -0.57 4.04 7.14 4.74 ;
        RECT 4.89 3.23 5.12 4.74 ;
        RECT 1.45 3.23 1.68 4.74 ;
    END
  END VDD
  OBS
    LAYER METAL1 ;
      RECT 0.535 1.56 5.12 1.79 ;
      RECT 4.89 1.09 5.12 1.79 ;
      RECT 3.735 0.99 3.965 1.79 ;
      RECT 2.135 0.99 2.365 1.79 ;
      RECT 0.535 0.99 0.765 1.79 ;
      RECT 2.17 3.56 3.84 3.79 ;
      RECT 3.61 3.23 3.84 3.79 ;
      RECT 0.73 2.77 0.96 3.57 ;
      RECT 2.17 2.77 2.4 3.79 ;
      RECT 0.73 2.77 2.4 3 ;
  END
END o21ai_1

MACRO o21ai_2
  CLASS CORE ;
  ORIGIN 0 -0.35 ;
  FOREIGN o21ai_2 0 0.35 ;
  SIZE 10.95 BY 4.04 ;
  SYMMETRY X Y ;
  SITE core ;
  PIN VSS
    DIRECTION INOUT ;
    USE GROUND ;
    PORT
      LAYER METAL1 ;
        RECT -0.57 0 11.52 0.7 ;
        RECT 6.16 0 6.39 1.33 ;
        RECT 4.56 0 4.79 1.33 ;
        RECT 2.96 0 3.19 1.33 ;
        RECT 1.36 0 1.59 1.33 ;
    END
  END VSS
  PIN A2
    DIRECTION INOUT ;
    USE SIGNAL ;
    ANTENNAPARTIALCUTAREA 0.0676 LAYER VIA12 ;
    ANTENNAMODEL OXIDE1 ;
      ANTENNAGATEAREA 0.6336 LAYER METAL2 ;
      ANTENNAGATEAREA 0.6336 LAYER METAL1 ;
      ANTENNAMAXAREACAR 1.073548 LAYER METAL2 ;
      ANTENNAMAXCUTCAR 0.106692 LAYER VIA12 ;
    PORT
      LAYER POLY1 ;
        RECT 4.185 2.07 6.765 2.49 ;
        RECT 6.585 0.83 6.765 2.49 ;
        RECT 6.425 2.07 6.605 3.83 ;
        RECT 5.785 0.83 5.965 2.49 ;
        RECT 5.705 2.07 5.885 3.83 ;
        RECT 4.985 0.83 5.165 3.83 ;
        RECT 4.265 2.07 4.445 3.83 ;
        RECT 4.185 0.83 4.365 2.49 ;
      LAYER METAL1 ;
        RECT 4.52 2.11 6.375 2.45 ;
        RECT 4.52 2.055 4.97 2.505 ;
      LAYER METAL2 ;
        RECT 4.52 2.055 4.97 2.505 ;
      LAYER CONT ;
        RECT 4.635 2.17 4.855 2.39 ;
        RECT 5.365 2.17 5.585 2.39 ;
        RECT 6.095 2.17 6.315 2.39 ;
      LAYER VIA12 ;
        RECT 4.615 2.15 4.875 2.41 ;
    END
  END A2
  PIN Y
    DIRECTION INOUT ;
    USE SIGNAL ;
    ANTENNAPARTIALCUTAREA 0.0676 LAYER VIA12 ;
    ANTENNADIFFAREA 1.51 LAYER METAL2 ;
    ANTENNADIFFAREA 0.2204 LAYER METAL1 ;
    PORT
      LAYER DIFF ;
        RECT 9.165 1.45 9.785 1.67 ;
        RECT 9.265 1.35 9.685 1.77 ;
        RECT 8.725 2.95 9.265 3.61 ;
        RECT 7.565 1.45 8.185 1.67 ;
        RECT 7.665 1.35 8.085 1.77 ;
        RECT 5.885 2.95 6.425 3.61 ;
        RECT 4.445 2.95 4.985 3.61 ;
      LAYER METAL1 ;
        RECT 4.6 2.77 10.775 3 ;
        RECT 10.395 2.09 10.775 3 ;
        RECT 8.88 2.77 9.11 3.57 ;
        RECT 6.04 2.77 6.27 3.33 ;
        RECT 4.6 2.77 4.83 3.33 ;
        RECT 9.165 1.39 9.775 1.77 ;
        RECT 7.565 1.39 8.175 1.77 ;
      LAYER METAL2 ;
        RECT 10.395 1.39 10.775 2.47 ;
        RECT 7.69 1.39 10.775 1.77 ;
      LAYER CONT ;
        RECT 4.605 3.05 4.825 3.27 ;
        RECT 6.045 3.05 6.265 3.27 ;
        RECT 7.765 1.45 7.985 1.67 ;
        RECT 8.885 3.17 9.105 3.39 ;
        RECT 9.365 1.45 9.585 1.67 ;
      LAYER VIA12 ;
        RECT 7.75 1.45 8.01 1.71 ;
        RECT 9.35 1.45 9.61 1.71 ;
        RECT 10.455 2.15 10.715 2.41 ;
    END
  END Y
  PIN B1
    DIRECTION INOUT ;
    USE SIGNAL ;
    ANTENNAPARTIALCUTAREA 0.0676 LAYER VIA12 ;
    ANTENNAMODEL OXIDE1 ;
      ANTENNAGATEAREA 0.396 LAYER METAL2 ;
      ANTENNAGATEAREA 0.396 LAYER METAL1 ;
      ANTENNAMAXAREACAR 1.717677 LAYER METAL2 ;
      ANTENNAMAXCUTCAR 0.170707 LAYER VIA12 ;
    PORT
      LAYER POLY1 ;
        RECT 7.385 2.07 9.965 2.49 ;
        RECT 9.785 1.23 9.965 2.49 ;
        RECT 9.265 2.07 9.445 3.83 ;
        RECT 8.985 1.23 9.165 2.49 ;
        RECT 8.545 2.07 8.725 3.83 ;
        RECT 8.185 1.23 8.365 2.49 ;
        RECT 7.385 1.23 7.565 2.49 ;
      LAYER METAL1 ;
        RECT 7.44 2.11 9.295 2.45 ;
        RECT 7.44 2.055 7.89 2.505 ;
      LAYER METAL2 ;
        RECT 7.44 2.055 7.89 2.505 ;
      LAYER CONT ;
        RECT 7.555 2.17 7.775 2.39 ;
        RECT 8.285 2.17 8.505 2.39 ;
        RECT 9.015 2.17 9.235 2.39 ;
      LAYER VIA12 ;
        RECT 7.535 2.15 7.795 2.41 ;
    END
  END B1
  PIN A1
    DIRECTION INOUT ;
    USE SIGNAL ;
    ANTENNAPARTIALCUTAREA 0.0676 LAYER VIA12 ;
    ANTENNAMODEL OXIDE1 ;
      ANTENNAGATEAREA 0.6336 LAYER METAL2 ;
      ANTENNAGATEAREA 0.6336 LAYER METAL1 ;
      ANTENNAMAXAREACAR 1.465278 LAYER METAL2 ;
      ANTENNAMAXCUTCAR 0.106692 LAYER VIA12 ;
    PORT
      LAYER POLY1 ;
        RECT 3.545 2.07 3.725 3.83 ;
        RECT 3.385 0.83 3.565 2.49 ;
        RECT 0.885 2.07 3.725 2.49 ;
        RECT 2.825 2.07 3.005 3.83 ;
        RECT 2.585 0.83 2.765 2.49 ;
        RECT 2.105 2.07 2.285 3.83 ;
        RECT 1.785 0.83 1.965 2.49 ;
        RECT 1.385 2.07 1.565 3.83 ;
        RECT 0.985 0.83 1.165 2.49 ;
      LAYER METAL1 ;
        RECT 0.87 2.11 3.455 2.45 ;
        RECT 0.87 2.055 1.32 2.505 ;
      LAYER METAL2 ;
        RECT 0.87 2.055 1.32 2.505 ;
      LAYER CONT ;
        RECT 0.985 2.17 1.205 2.39 ;
        RECT 1.715 2.17 1.935 2.39 ;
        RECT 2.445 2.17 2.665 2.39 ;
        RECT 3.175 2.17 3.395 2.39 ;
      LAYER VIA12 ;
        RECT 0.965 2.15 1.225 2.41 ;
    END
  END A1
  PIN VDD
    DIRECTION INOUT ;
    USE POWER ;
    PORT
      LAYER METAL1 ;
        RECT -0.57 4.04 11.52 4.74 ;
        RECT 9.6 3.23 9.83 4.74 ;
        RECT 8.16 3.23 8.39 4.74 ;
        RECT 3.16 3.23 3.39 4.74 ;
        RECT 1.72 3.23 1.95 4.74 ;
    END
  END VDD
  OBS
    LAYER METAL1 ;
      RECT 0.56 1.56 7.19 1.79 ;
      RECT 6.96 0.93 7.19 1.79 ;
      RECT 10.16 0.93 10.39 1.73 ;
      RECT 8.56 0.93 8.79 1.73 ;
      RECT 5.36 0.99 5.59 1.79 ;
      RECT 3.76 0.99 3.99 1.79 ;
      RECT 2.16 0.99 2.39 1.79 ;
      RECT 0.56 0.99 0.79 1.79 ;
      RECT 6.96 0.93 10.39 1.16 ;
      RECT 3.88 3.56 6.99 3.79 ;
      RECT 6.76 3.23 6.99 3.79 ;
      RECT 2.44 2.77 2.67 3.57 ;
      RECT 1 2.77 1.23 3.57 ;
      RECT 5.32 3.23 5.55 3.79 ;
      RECT 3.88 2.77 4.11 3.79 ;
      RECT 1 2.77 4.11 3 ;
  END
END o21ai_2

MACRO o21ai_4
  CLASS CORE ;
  ORIGIN 0 -0.35 ;
  FOREIGN o21ai_4 0 0.35 ;
  SIZE 20.44 BY 4.04 ;
  SYMMETRY X Y ;
  SITE core ;
  PIN VSS
    DIRECTION INOUT ;
    USE GROUND ;
    PORT
      LAYER METAL1 ;
        RECT -0.57 0 21.01 0.7 ;
        RECT 12.505 0 12.735 1.33 ;
        RECT 10.905 0 11.135 1.33 ;
        RECT 9.305 0 9.535 1.33 ;
        RECT 7.705 0 7.935 1.33 ;
        RECT 6.105 0 6.335 1.33 ;
        RECT 4.505 0 4.735 1.33 ;
        RECT 2.905 0 3.135 1.33 ;
        RECT 1.305 0 1.535 1.33 ;
    END
  END VSS
  PIN B1
    DIRECTION INOUT ;
    USE SIGNAL ;
    ANTENNAPARTIALCUTAREA 0.1352 LAYER VIA12 ;
    ANTENNAMODEL OXIDE1 ;
      ANTENNAGATEAREA 0.792 LAYER METAL2 ;
      ANTENNAGATEAREA 0.792 LAYER METAL1 ;
      ANTENNAMAXAREACAR 2.606187 LAYER METAL2 ;
      ANTENNAMAXCUTCAR 0.170707 LAYER VIA12 ;
    PORT
      LAYER POLY1 ;
        RECT 13.555 2.07 19.555 2.49 ;
        RECT 19.33 1.23 19.51 2.49 ;
        RECT 18.53 1.23 18.71 2.49 ;
        RECT 17.73 1.23 17.91 2.49 ;
        RECT 17.61 2.07 17.79 3.83 ;
        RECT 16.93 1.23 17.11 2.49 ;
        RECT 16.89 2.07 17.07 3.83 ;
        RECT 16.17 2.07 16.35 3.83 ;
        RECT 16.13 1.23 16.31 2.49 ;
        RECT 15.45 2.07 15.63 3.83 ;
        RECT 15.33 1.23 15.51 2.49 ;
        RECT 14.53 1.23 14.71 2.49 ;
        RECT 13.73 1.23 13.91 2.49 ;
      LAYER METAL1 ;
        RECT 13.55 2.11 19.515 2.45 ;
        RECT 13.55 2.09 14.45 2.47 ;
      LAYER METAL2 ;
        RECT 13.55 2.09 14.45 2.47 ;
      LAYER CONT ;
        RECT 13.655 2.17 13.875 2.39 ;
        RECT 14.125 2.17 14.345 2.39 ;
        RECT 14.855 2.17 15.075 2.39 ;
        RECT 15.585 2.17 15.805 2.39 ;
        RECT 16.315 2.17 16.535 2.39 ;
        RECT 17.045 2.17 17.265 2.39 ;
        RECT 17.775 2.17 17.995 2.39 ;
        RECT 18.505 2.17 18.725 2.39 ;
        RECT 19.235 2.17 19.455 2.39 ;
      LAYER VIA12 ;
        RECT 13.61 2.15 13.87 2.41 ;
        RECT 14.13 2.15 14.39 2.41 ;
    END
  END B1
  PIN A2
    DIRECTION INOUT ;
    USE SIGNAL ;
    ANTENNAPARTIALCUTAREA 0.1352 LAYER VIA12 ;
    ANTENNAMODEL OXIDE1 ;
      ANTENNAGATEAREA 1.2672 LAYER METAL2 ;
      ANTENNAGATEAREA 1.2672 LAYER METAL1 ;
      ANTENNAMAXAREACAR 1.434343 LAYER METAL2 ;
      ANTENNAMAXCUTCAR 0.106692 LAYER VIA12 ;
    PORT
      LAYER POLY1 ;
        RECT 7.29 2.07 13.11 2.49 ;
        RECT 12.93 0.83 13.11 2.49 ;
        RECT 12.33 2.07 12.51 3.83 ;
        RECT 12.13 0.83 12.31 2.49 ;
        RECT 11.61 2.07 11.79 3.83 ;
        RECT 11.33 0.83 11.51 2.49 ;
        RECT 10.89 2.07 11.07 3.83 ;
        RECT 10.53 0.83 10.71 2.49 ;
        RECT 10.17 2.07 10.35 3.83 ;
        RECT 9.73 0.83 9.91 2.49 ;
        RECT 9.45 2.07 9.63 3.83 ;
        RECT 8.93 0.83 9.11 2.49 ;
        RECT 8.73 2.07 8.91 3.83 ;
        RECT 8.13 0.83 8.31 2.49 ;
        RECT 8.01 2.07 8.19 3.83 ;
        RECT 7.33 0.83 7.51 2.49 ;
        RECT 7.29 2.07 7.47 3.83 ;
      LAYER METAL1 ;
        RECT 7.705 2.11 12.945 2.45 ;
        RECT 7.705 2.09 8.605 2.47 ;
      LAYER METAL2 ;
        RECT 7.705 2.09 8.605 2.47 ;
      LAYER CONT ;
        RECT 7.81 2.17 8.03 2.39 ;
        RECT 8.28 2.17 8.5 2.39 ;
        RECT 9.015 2.17 9.235 2.39 ;
        RECT 9.745 2.17 9.965 2.39 ;
        RECT 10.475 2.17 10.695 2.39 ;
        RECT 11.205 2.17 11.425 2.39 ;
        RECT 11.935 2.17 12.155 2.39 ;
        RECT 12.665 2.17 12.885 2.39 ;
      LAYER VIA12 ;
        RECT 7.765 2.15 8.025 2.41 ;
        RECT 8.285 2.15 8.545 2.41 ;
    END
  END A2
  PIN VDD
    DIRECTION INOUT ;
    USE POWER ;
    PORT
      LAYER METAL1 ;
        RECT -0.57 4.04 21.01 4.74 ;
        RECT 17.945 3.23 18.175 4.74 ;
        RECT 16.505 3.23 16.735 4.74 ;
        RECT 15.065 3.23 15.295 4.74 ;
        RECT 6.185 3.23 6.415 4.74 ;
        RECT 4.745 3.23 4.975 4.74 ;
        RECT 3.305 3.23 3.535 4.74 ;
        RECT 1.865 3.23 2.095 4.74 ;
    END
  END VDD
  PIN A1
    DIRECTION INOUT ;
    USE SIGNAL ;
    ANTENNAPARTIALCUTAREA 0.1352 LAYER VIA12 ;
    ANTENNAMODEL OXIDE1 ;
      ANTENNAGATEAREA 1.2672 LAYER METAL2 ;
      ANTENNAGATEAREA 1.2672 LAYER METAL1 ;
      ANTENNAMAXAREACAR 1.433002 LAYER METAL2 ;
      ANTENNAMAXCUTCAR 0.106692 LAYER VIA12 ;
    PORT
      LAYER POLY1 ;
        RECT 6.57 2.07 6.75 3.83 ;
        RECT 6.53 0.83 6.71 2.49 ;
        RECT 0.93 2.07 6.75 2.49 ;
        RECT 5.85 2.07 6.03 3.83 ;
        RECT 5.73 0.83 5.91 2.49 ;
        RECT 5.13 2.07 5.31 3.83 ;
        RECT 4.93 0.83 5.11 2.49 ;
        RECT 4.41 2.07 4.59 3.83 ;
        RECT 4.13 0.83 4.31 2.49 ;
        RECT 3.69 2.07 3.87 3.83 ;
        RECT 3.33 0.83 3.51 2.49 ;
        RECT 2.97 2.07 3.15 3.83 ;
        RECT 2.53 0.83 2.71 2.49 ;
        RECT 2.25 2.07 2.43 3.83 ;
        RECT 1.73 0.83 1.91 2.49 ;
        RECT 1.53 2.07 1.71 3.83 ;
        RECT 0.93 0.83 1.11 2.49 ;
      LAYER METAL1 ;
        RECT 1.14 2.11 6.375 2.45 ;
        RECT 1.14 2.09 2.04 2.47 ;
      LAYER METAL2 ;
        RECT 1.14 2.09 2.04 2.47 ;
      LAYER CONT ;
        RECT 1.245 2.17 1.465 2.39 ;
        RECT 1.715 2.17 1.935 2.39 ;
        RECT 2.445 2.17 2.665 2.39 ;
        RECT 3.175 2.17 3.395 2.39 ;
        RECT 3.905 2.17 4.125 2.39 ;
        RECT 4.635 2.17 4.855 2.39 ;
        RECT 5.365 2.17 5.585 2.39 ;
        RECT 6.095 2.17 6.315 2.39 ;
      LAYER VIA12 ;
        RECT 1.2 2.15 1.46 2.41 ;
        RECT 1.72 2.15 1.98 2.41 ;
    END
  END A1
  PIN Y
    DIRECTION INOUT ;
    USE SIGNAL ;
    ANTENNAPARTIALCUTAREA 0.1352 LAYER VIA12 ;
    ANTENNADIFFAREA 3.02 LAYER METAL2 ;
    ANTENNADIFFAREA 0.2204 LAYER METAL1 ;
    PORT
      LAYER DIFF ;
        RECT 18.71 1.45 19.33 1.67 ;
        RECT 18.81 1.35 19.23 1.77 ;
        RECT 17.11 1.45 17.73 1.67 ;
        RECT 17.21 1.35 17.63 1.77 ;
        RECT 17.07 2.95 17.61 3.61 ;
        RECT 15.63 2.95 16.17 3.61 ;
        RECT 15.51 1.45 16.13 1.67 ;
        RECT 15.61 1.35 16.03 1.77 ;
        RECT 13.91 1.45 14.53 1.67 ;
        RECT 14.01 1.35 14.43 1.77 ;
        RECT 11.79 2.95 12.33 3.61 ;
        RECT 10.35 2.95 10.89 3.61 ;
        RECT 8.91 2.95 9.45 3.61 ;
        RECT 7.47 2.95 8.01 3.61 ;
      LAYER METAL1 ;
        RECT 7.625 2.765 20.27 2.995 ;
        RECT 19.89 2.055 20.27 2.995 ;
        RECT 17.225 2.765 17.455 3.57 ;
        RECT 15.785 2.765 16.015 3.57 ;
        RECT 11.945 2.765 12.175 3.33 ;
        RECT 10.505 2.765 10.735 3.33 ;
        RECT 9.065 2.765 9.295 3.33 ;
        RECT 7.625 2.765 7.855 3.33 ;
        RECT 18.72 1.39 19.32 1.77 ;
        RECT 17.12 1.39 17.72 1.77 ;
        RECT 15.52 1.39 16.12 1.77 ;
        RECT 13.92 1.39 14.52 1.77 ;
      LAYER METAL2 ;
        RECT 19.85 1.39 20.3 2.955 ;
        RECT 14.03 1.39 20.3 1.77 ;
      LAYER CONT ;
        RECT 7.63 3.05 7.85 3.27 ;
        RECT 9.07 3.05 9.29 3.27 ;
        RECT 10.51 3.05 10.73 3.27 ;
        RECT 11.95 3.05 12.17 3.27 ;
        RECT 14.11 1.45 14.33 1.67 ;
        RECT 15.71 1.45 15.93 1.67 ;
        RECT 15.79 3.17 16.01 3.39 ;
        RECT 17.23 3.17 17.45 3.39 ;
        RECT 17.31 1.45 17.53 1.67 ;
        RECT 18.91 1.45 19.13 1.67 ;
      LAYER VIA12 ;
        RECT 14.09 1.45 14.35 1.71 ;
        RECT 15.69 1.45 15.95 1.71 ;
        RECT 17.29 1.45 17.55 1.71 ;
        RECT 18.89 1.45 19.15 1.71 ;
        RECT 19.95 2.635 20.21 2.895 ;
        RECT 19.95 2.115 20.21 2.375 ;
    END
  END Y
  OBS
    LAYER METAL1 ;
      RECT 0.505 1.56 13.535 1.79 ;
      RECT 13.305 0.93 13.535 1.79 ;
      RECT 19.705 0.93 19.935 1.73 ;
      RECT 18.105 0.93 18.335 1.73 ;
      RECT 16.505 0.93 16.735 1.73 ;
      RECT 14.905 0.93 15.135 1.73 ;
      RECT 11.705 0.99 11.935 1.79 ;
      RECT 10.105 0.99 10.335 1.79 ;
      RECT 8.505 0.99 8.735 1.79 ;
      RECT 6.905 0.99 7.135 1.79 ;
      RECT 5.305 0.99 5.535 1.79 ;
      RECT 3.705 0.99 3.935 1.79 ;
      RECT 2.105 0.99 2.335 1.79 ;
      RECT 0.505 0.99 0.735 1.79 ;
      RECT 13.305 0.93 19.935 1.16 ;
      RECT 6.905 3.56 12.895 3.79 ;
      RECT 12.665 3.23 12.895 3.79 ;
      RECT 5.465 2.765 5.695 3.57 ;
      RECT 4.025 2.765 4.255 3.57 ;
      RECT 2.585 2.765 2.815 3.57 ;
      RECT 1.145 2.765 1.375 3.57 ;
      RECT 11.225 3.23 11.455 3.79 ;
      RECT 9.785 3.23 10.015 3.79 ;
      RECT 8.345 3.23 8.575 3.79 ;
      RECT 6.905 2.765 7.135 3.79 ;
      RECT 1.145 2.765 7.135 2.995 ;
  END
END o21ai_4

MACRO o21ai_8
  CLASS CORE ;
  ORIGIN 0 -0.35 ;
  FOREIGN o21ai_8 0 0.35 ;
  SIZE 39.42 BY 4.04 ;
  SYMMETRY X Y ;
  SITE core ;
  PIN VSS
    DIRECTION INOUT ;
    USE GROUND ;
    PORT
      LAYER METAL1 ;
        RECT -0.57 0 39.99 0.7 ;
        RECT 25.195 0 25.425 1.33 ;
        RECT 23.595 0 23.825 1.33 ;
        RECT 21.995 0 22.225 1.33 ;
        RECT 20.395 0 20.625 1.33 ;
        RECT 18.795 0 19.025 1.33 ;
        RECT 17.195 0 17.425 1.33 ;
        RECT 15.595 0 15.825 1.33 ;
        RECT 13.995 0 14.225 1.33 ;
        RECT 12.395 0 12.625 1.33 ;
        RECT 10.795 0 11.025 1.33 ;
        RECT 9.195 0 9.425 1.33 ;
        RECT 7.595 0 7.825 1.33 ;
        RECT 5.995 0 6.225 1.33 ;
        RECT 4.395 0 4.625 1.33 ;
        RECT 2.795 0 3.025 1.33 ;
        RECT 1.195 0 1.425 1.33 ;
    END
  END VSS
  PIN B1
    DIRECTION INOUT ;
    USE SIGNAL ;
    ANTENNAPARTIALCUTAREA 0.2028 LAYER VIA12 ;
    ANTENNAMODEL OXIDE1 ;
      ANTENNAGATEAREA 1.584 LAYER METAL2 ;
      ANTENNAGATEAREA 1.584 LAYER METAL1 ;
      ANTENNAMAXAREACAR 3.000126 LAYER METAL2 ;
      ANTENNAMAXCUTCAR 0.12803 LAYER VIA12 ;
    PORT
      LAYER POLY1 ;
        RECT 26.42 2.07 38.6 2.49 ;
        RECT 38.42 1.23 38.6 2.49 ;
        RECT 37.62 1.23 37.8 2.49 ;
        RECT 36.82 1.23 37 2.49 ;
        RECT 36.02 1.23 36.2 2.49 ;
        RECT 35.22 1.23 35.4 2.49 ;
        RECT 34.42 1.23 34.6 2.49 ;
        RECT 33.62 1.23 33.8 2.49 ;
        RECT 32.82 1.23 33 2.49 ;
        RECT 32.27 2.07 32.45 3.83 ;
        RECT 32.02 1.23 32.2 2.49 ;
        RECT 31.55 2.07 31.73 3.83 ;
        RECT 31.22 1.23 31.4 2.49 ;
        RECT 30.83 2.07 31.01 3.83 ;
        RECT 30.42 1.23 30.6 2.49 ;
        RECT 30.11 2.07 30.29 3.83 ;
        RECT 29.62 1.23 29.8 2.49 ;
        RECT 29.39 2.07 29.57 3.83 ;
        RECT 28.82 1.23 29 2.49 ;
        RECT 28.67 2.07 28.85 3.83 ;
        RECT 28.02 1.23 28.2 2.49 ;
        RECT 27.95 2.07 28.13 3.83 ;
        RECT 27.23 2.07 27.41 3.83 ;
        RECT 27.22 1.23 27.4 2.49 ;
        RECT 26.42 1.23 26.6 2.49 ;
      LAYER METAL1 ;
        RECT 38.865 2.06 39.245 3.48 ;
        RECT 26.475 2.11 39.245 2.45 ;
      LAYER METAL2 ;
        RECT 38.865 2.06 39.245 3.48 ;
      LAYER CONT ;
        RECT 26.535 2.17 26.755 2.39 ;
        RECT 27.265 2.17 27.485 2.39 ;
        RECT 27.995 2.17 28.215 2.39 ;
        RECT 28.725 2.17 28.945 2.39 ;
        RECT 29.455 2.17 29.675 2.39 ;
        RECT 30.185 2.17 30.405 2.39 ;
        RECT 30.915 2.17 31.135 2.39 ;
        RECT 31.645 2.17 31.865 2.39 ;
        RECT 32.375 2.17 32.595 2.39 ;
        RECT 33.105 2.17 33.325 2.39 ;
        RECT 33.835 2.17 34.055 2.39 ;
        RECT 34.565 2.17 34.785 2.39 ;
        RECT 35.295 2.17 35.515 2.39 ;
        RECT 36.025 2.17 36.245 2.39 ;
        RECT 36.755 2.17 36.975 2.39 ;
        RECT 37.485 2.17 37.705 2.39 ;
        RECT 38.215 2.17 38.435 2.39 ;
      LAYER VIA12 ;
        RECT 38.925 3.16 39.185 3.42 ;
        RECT 38.925 2.64 39.185 2.9 ;
        RECT 38.925 2.12 39.185 2.38 ;
    END
  END B1
  PIN Y
    DIRECTION INOUT ;
    USE SIGNAL ;
    ANTENNAPARTIALCUTAREA 0.1352 LAYER VIA12 ;
    ANTENNADIFFAREA 6.04 LAYER METAL2 ;
    ANTENNADIFFAREA 0.2204 LAYER METAL1 ;
    PORT
      LAYER DIFF ;
        RECT 37.8 1.45 38.42 1.67 ;
        RECT 37.9 1.35 38.32 1.77 ;
        RECT 36.2 1.45 36.82 1.67 ;
        RECT 36.3 1.35 36.72 1.77 ;
        RECT 34.6 1.45 35.22 1.67 ;
        RECT 34.7 1.35 35.12 1.77 ;
        RECT 33 1.45 33.62 1.67 ;
        RECT 33.1 1.35 33.52 1.77 ;
        RECT 31.73 2.95 32.27 3.61 ;
        RECT 31.4 1.45 32.02 1.67 ;
        RECT 31.5 1.35 31.92 1.77 ;
        RECT 30.29 2.95 30.83 3.61 ;
        RECT 29.8 1.45 30.42 1.67 ;
        RECT 29.9 1.35 30.32 1.77 ;
        RECT 28.85 2.95 29.39 3.61 ;
        RECT 28.2 1.45 28.82 1.67 ;
        RECT 28.3 1.35 28.72 1.77 ;
        RECT 27.41 2.95 27.95 3.61 ;
        RECT 26.6 1.45 27.22 1.67 ;
        RECT 26.7 1.35 27.12 1.77 ;
        RECT 23.835 2.95 24.375 3.61 ;
        RECT 22.395 2.95 22.935 3.61 ;
        RECT 20.955 2.95 21.495 3.61 ;
        RECT 19.515 2.95 20.055 3.61 ;
        RECT 18.075 2.95 18.615 3.61 ;
        RECT 16.635 2.95 17.175 3.61 ;
        RECT 15.195 2.95 15.735 3.61 ;
        RECT 13.755 2.95 14.295 3.61 ;
      LAYER METAL1 ;
        RECT 37.81 1.39 38.41 1.77 ;
        RECT 36.21 1.39 36.81 1.77 ;
        RECT 34.61 1.39 35.21 1.77 ;
        RECT 33.01 1.39 33.61 1.77 ;
        RECT 31.885 2.77 32.115 3.57 ;
        RECT 13.91 2.77 32.115 3 ;
        RECT 30.445 2.77 30.675 3.57 ;
        RECT 29.005 2.77 29.235 3.57 ;
        RECT 27.565 2.77 27.795 3.57 ;
        RECT 25.725 2.055 26.105 3 ;
        RECT 23.99 2.77 24.22 3.33 ;
        RECT 22.55 2.77 22.78 3.33 ;
        RECT 21.11 2.77 21.34 3.33 ;
        RECT 19.67 2.77 19.9 3.33 ;
        RECT 18.23 2.77 18.46 3.33 ;
        RECT 16.79 2.77 17.02 3.33 ;
        RECT 15.35 2.77 15.58 3.33 ;
        RECT 13.91 2.77 14.14 3.33 ;
        RECT 31.41 1.39 32.01 1.77 ;
        RECT 29.81 1.39 30.41 1.77 ;
        RECT 28.21 1.39 28.81 1.77 ;
        RECT 26.61 1.39 27.21 1.77 ;
      LAYER METAL2 ;
        RECT 25.86 1.39 38.3 1.77 ;
        RECT 25.69 2.055 26.14 2.955 ;
        RECT 25.86 1.39 26.14 2.955 ;
      LAYER CONT ;
        RECT 13.915 3.05 14.135 3.27 ;
        RECT 15.355 3.05 15.575 3.27 ;
        RECT 16.795 3.05 17.015 3.27 ;
        RECT 18.235 3.05 18.455 3.27 ;
        RECT 19.675 3.05 19.895 3.27 ;
        RECT 21.115 3.05 21.335 3.27 ;
        RECT 22.555 3.05 22.775 3.27 ;
        RECT 23.995 3.05 24.215 3.27 ;
        RECT 26.8 1.45 27.02 1.67 ;
        RECT 27.57 3.17 27.79 3.39 ;
        RECT 28.4 1.45 28.62 1.67 ;
        RECT 29.01 3.17 29.23 3.39 ;
        RECT 30 1.45 30.22 1.67 ;
        RECT 30.45 3.17 30.67 3.39 ;
        RECT 31.6 1.45 31.82 1.67 ;
        RECT 31.89 3.17 32.11 3.39 ;
        RECT 33.2 1.45 33.42 1.67 ;
        RECT 34.8 1.45 35.02 1.67 ;
        RECT 36.4 1.45 36.62 1.67 ;
        RECT 38 1.45 38.22 1.67 ;
      LAYER VIA12 ;
        RECT 25.785 2.635 26.045 2.895 ;
        RECT 25.785 2.115 26.045 2.375 ;
        RECT 26.78 1.45 27.04 1.71 ;
        RECT 28.38 1.45 28.64 1.71 ;
        RECT 29.98 1.45 30.24 1.71 ;
        RECT 31.58 1.45 31.84 1.71 ;
        RECT 33.18 1.45 33.44 1.71 ;
        RECT 34.78 1.45 35.04 1.71 ;
        RECT 36.38 1.45 36.64 1.71 ;
        RECT 37.98 1.45 38.24 1.71 ;
    END
  END Y
  PIN A1
    DIRECTION INOUT ;
    USE SIGNAL ;
    ANTENNAPARTIALCUTAREA 0.1352 LAYER VIA12 ;
    ANTENNAMODEL OXIDE1 ;
      ANTENNAGATEAREA 2.5344 LAYER METAL2 ;
      ANTENNAGATEAREA 2.5344 LAYER METAL1 ;
      ANTENNAMAXAREACAR 1.654632 LAYER METAL2 ;
      ANTENNAMAXCUTCAR 0.053346 LAYER VIA12 ;
    PORT
      LAYER POLY1 ;
        RECT 12.855 2.07 13.035 3.83 ;
        RECT 12.82 0.83 13 2.49 ;
        RECT 0.82 2.07 13.035 2.49 ;
        RECT 12.135 2.07 12.315 3.83 ;
        RECT 12.02 0.83 12.2 2.49 ;
        RECT 11.415 2.07 11.595 3.83 ;
        RECT 11.22 0.83 11.4 2.49 ;
        RECT 10.695 2.07 10.875 3.83 ;
        RECT 10.42 0.83 10.6 2.49 ;
        RECT 9.975 2.07 10.155 3.83 ;
        RECT 9.62 0.83 9.8 2.49 ;
        RECT 9.255 2.07 9.435 3.83 ;
        RECT 8.82 0.83 9 2.49 ;
        RECT 8.535 2.07 8.715 3.83 ;
        RECT 8.02 0.83 8.2 2.49 ;
        RECT 7.815 2.07 7.995 3.83 ;
        RECT 7.22 0.83 7.4 2.49 ;
        RECT 7.095 2.07 7.275 3.83 ;
        RECT 6.42 0.83 6.6 2.49 ;
        RECT 6.375 2.07 6.555 3.83 ;
        RECT 5.655 2.07 5.835 3.83 ;
        RECT 5.62 0.83 5.8 2.49 ;
        RECT 4.935 2.07 5.115 3.83 ;
        RECT 4.82 0.83 5 2.49 ;
        RECT 4.215 2.07 4.395 3.83 ;
        RECT 4.02 0.83 4.2 2.49 ;
        RECT 3.495 2.07 3.675 3.83 ;
        RECT 3.22 0.83 3.4 2.49 ;
        RECT 2.775 2.07 2.955 3.83 ;
        RECT 2.42 0.83 2.6 2.49 ;
        RECT 2.055 2.07 2.235 3.83 ;
        RECT 1.62 0.83 1.8 2.49 ;
        RECT 0.82 0.83 1 2.49 ;
      LAYER METAL1 ;
        RECT 0.925 2.11 12.945 2.45 ;
        RECT 0.925 2.055 1.895 2.505 ;
      LAYER METAL2 ;
        RECT 0.96 2.09 1.86 2.47 ;
      LAYER CONT ;
        RECT 1.065 2.17 1.285 2.39 ;
        RECT 1.535 2.17 1.755 2.39 ;
        RECT 2.445 2.17 2.665 2.39 ;
        RECT 3.175 2.17 3.395 2.39 ;
        RECT 3.905 2.17 4.125 2.39 ;
        RECT 4.635 2.17 4.855 2.39 ;
        RECT 5.365 2.17 5.585 2.39 ;
        RECT 6.095 2.17 6.315 2.39 ;
        RECT 6.825 2.17 7.045 2.39 ;
        RECT 7.555 2.17 7.775 2.39 ;
        RECT 8.285 2.17 8.505 2.39 ;
        RECT 9.015 2.17 9.235 2.39 ;
        RECT 9.745 2.17 9.965 2.39 ;
        RECT 10.475 2.17 10.695 2.39 ;
        RECT 11.205 2.17 11.425 2.39 ;
        RECT 11.935 2.17 12.155 2.39 ;
        RECT 12.665 2.17 12.885 2.39 ;
      LAYER VIA12 ;
        RECT 1.02 2.15 1.28 2.41 ;
        RECT 1.54 2.15 1.8 2.41 ;
    END
  END A1
  PIN A2
    DIRECTION INOUT ;
    USE SIGNAL ;
    ANTENNAPARTIALCUTAREA 0.1352 LAYER VIA12 ;
    ANTENNAMODEL OXIDE1 ;
      ANTENNAGATEAREA 2.5344 LAYER METAL2 ;
      ANTENNAGATEAREA 2.5344 LAYER METAL1 ;
      ANTENNAMAXAREACAR 1.627801 LAYER METAL2 ;
      ANTENNAMAXCUTCAR 0.053346 LAYER VIA12 ;
    PORT
      LAYER POLY1 ;
        RECT 13.575 2.07 25.8 2.49 ;
        RECT 25.62 0.83 25.8 2.49 ;
        RECT 24.82 0.83 25 2.49 ;
        RECT 24.375 2.07 24.555 3.83 ;
        RECT 24.02 0.83 24.2 2.49 ;
        RECT 23.655 2.07 23.835 3.83 ;
        RECT 23.22 0.83 23.4 2.49 ;
        RECT 22.935 2.07 23.115 3.83 ;
        RECT 22.42 0.83 22.6 2.49 ;
        RECT 22.215 2.07 22.395 3.83 ;
        RECT 21.62 0.83 21.8 2.49 ;
        RECT 21.495 2.07 21.675 3.83 ;
        RECT 20.82 0.83 21 2.49 ;
        RECT 20.775 2.07 20.955 3.83 ;
        RECT 20.055 2.07 20.235 3.83 ;
        RECT 20.02 0.83 20.2 2.49 ;
        RECT 19.335 2.07 19.515 3.83 ;
        RECT 19.22 0.83 19.4 2.49 ;
        RECT 18.615 2.07 18.795 3.83 ;
        RECT 18.42 0.83 18.6 2.49 ;
        RECT 17.895 2.07 18.075 3.83 ;
        RECT 17.62 0.83 17.8 2.49 ;
        RECT 17.175 2.07 17.355 3.83 ;
        RECT 16.82 0.83 17 2.49 ;
        RECT 16.455 2.07 16.635 3.83 ;
        RECT 16.02 0.83 16.2 2.49 ;
        RECT 15.735 2.07 15.915 3.83 ;
        RECT 15.22 0.83 15.4 2.49 ;
        RECT 15.015 2.07 15.195 3.83 ;
        RECT 14.42 0.83 14.6 2.49 ;
        RECT 14.295 2.07 14.475 3.83 ;
        RECT 13.62 0.83 13.8 2.49 ;
        RECT 13.575 2.07 13.755 3.83 ;
      LAYER METAL1 ;
        RECT 13.535 2.11 25.355 2.45 ;
        RECT 13.535 2.055 14.505 2.505 ;
      LAYER METAL2 ;
        RECT 13.57 2.09 14.47 2.47 ;
      LAYER CONT ;
        RECT 13.675 2.17 13.895 2.39 ;
        RECT 14.145 2.17 14.365 2.39 ;
        RECT 14.855 2.17 15.075 2.39 ;
        RECT 15.585 2.17 15.805 2.39 ;
        RECT 16.315 2.17 16.535 2.39 ;
        RECT 17.045 2.17 17.265 2.39 ;
        RECT 17.775 2.17 17.995 2.39 ;
        RECT 18.505 2.17 18.725 2.39 ;
        RECT 19.235 2.17 19.455 2.39 ;
        RECT 19.965 2.17 20.185 2.39 ;
        RECT 20.695 2.17 20.915 2.39 ;
        RECT 21.425 2.17 21.645 2.39 ;
        RECT 22.155 2.17 22.375 2.39 ;
        RECT 22.885 2.17 23.105 2.39 ;
        RECT 23.615 2.17 23.835 2.39 ;
        RECT 24.345 2.17 24.565 2.39 ;
        RECT 25.075 2.17 25.295 2.39 ;
      LAYER VIA12 ;
        RECT 13.63 2.15 13.89 2.41 ;
        RECT 14.15 2.15 14.41 2.41 ;
    END
  END A2
  PIN VDD
    DIRECTION INOUT ;
    USE POWER ;
    PORT
      LAYER METAL1 ;
        RECT -0.57 4.04 39.99 4.74 ;
        RECT 32.605 2.99 32.835 4.74 ;
        RECT 31.165 3.23 31.395 4.74 ;
        RECT 29.725 3.23 29.955 4.74 ;
        RECT 28.285 3.23 28.515 4.74 ;
        RECT 26.845 3.23 27.075 4.74 ;
        RECT 12.47 3.23 12.7 4.74 ;
        RECT 11.03 3.23 11.26 4.74 ;
        RECT 9.59 3.23 9.82 4.74 ;
        RECT 8.15 3.23 8.38 4.74 ;
        RECT 6.71 3.23 6.94 4.74 ;
        RECT 5.27 3.23 5.5 4.74 ;
        RECT 3.83 3.23 4.06 4.74 ;
        RECT 2.39 3.23 2.62 4.74 ;
    END
  END VDD
  OBS
    LAYER METAL1 ;
      RECT 0.395 1.56 26.225 1.79 ;
      RECT 25.995 0.93 26.225 1.79 ;
      RECT 38.795 0.93 39.025 1.73 ;
      RECT 37.195 0.93 37.425 1.73 ;
      RECT 35.595 0.93 35.825 1.73 ;
      RECT 33.995 0.93 34.225 1.73 ;
      RECT 32.395 0.93 32.625 1.73 ;
      RECT 30.795 0.93 31.025 1.73 ;
      RECT 29.195 0.93 29.425 1.73 ;
      RECT 27.595 0.93 27.825 1.73 ;
      RECT 24.395 0.99 24.625 1.79 ;
      RECT 22.795 0.99 23.025 1.79 ;
      RECT 21.195 0.99 21.425 1.79 ;
      RECT 19.595 0.99 19.825 1.79 ;
      RECT 17.995 0.99 18.225 1.79 ;
      RECT 16.395 0.99 16.625 1.79 ;
      RECT 14.795 0.99 15.025 1.79 ;
      RECT 13.195 0.99 13.425 1.79 ;
      RECT 11.595 0.99 11.825 1.79 ;
      RECT 9.995 0.99 10.225 1.79 ;
      RECT 8.395 0.99 8.625 1.79 ;
      RECT 6.795 0.99 7.025 1.79 ;
      RECT 5.195 0.99 5.425 1.79 ;
      RECT 3.595 0.99 3.825 1.79 ;
      RECT 1.995 0.99 2.225 1.79 ;
      RECT 0.395 0.99 0.625 1.79 ;
      RECT 25.995 0.93 39.025 1.16 ;
      RECT 13.19 3.56 25.545 3.79 ;
      RECT 11.75 2.77 11.98 3.57 ;
      RECT 10.31 2.77 10.54 3.57 ;
      RECT 8.87 2.77 9.1 3.57 ;
      RECT 7.43 2.77 7.66 3.57 ;
      RECT 5.99 2.77 6.22 3.57 ;
      RECT 4.55 2.77 4.78 3.57 ;
      RECT 3.11 2.77 3.34 3.57 ;
      RECT 1.67 2.77 1.9 3.57 ;
      RECT 24.71 3.23 24.94 3.79 ;
      RECT 23.27 3.23 23.5 3.79 ;
      RECT 21.83 3.23 22.06 3.79 ;
      RECT 20.39 3.23 20.62 3.79 ;
      RECT 18.95 3.23 19.18 3.79 ;
      RECT 17.51 3.23 17.74 3.79 ;
      RECT 16.07 3.23 16.3 3.79 ;
      RECT 14.63 3.23 14.86 3.79 ;
      RECT 13.19 2.77 13.42 3.79 ;
      RECT 1.67 2.77 13.42 3 ;
  END
END o21ai_8

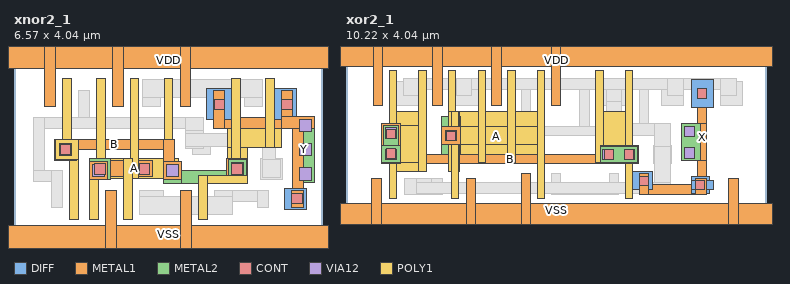
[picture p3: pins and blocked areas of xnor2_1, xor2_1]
MACRO xnor2_1
  CLASS CORE ;
  ORIGIN 0 -0.35 ;
  FOREIGN xnor2_1 0 0.35 ;
  SIZE 6.57 BY 4.04 ;
  SYMMETRY X Y ;
  SITE core ;
  PIN VSS
    DIRECTION INOUT ;
    USE GROUND ;
    PORT
      LAYER METAL1 ;
        RECT -0.57 0 7.14 0.7 ;
        RECT 3.545 0 3.78 1.45 ;
        RECT 1.95 0 2.18 1.45 ;
    END
  END VSS
  PIN A
    DIRECTION INOUT ;
    USE SIGNAL ;
    ANTENNAPARTIALCUTAREA 0.0676 LAYER VIA12 ;
    ANTENNAMODEL OXIDE1 ;
      ANTENNAGATEAREA 0.5148 LAYER METAL2 ;
      ANTENNAGATEAREA 0.5148 LAYER METAL1 ;
      ANTENNAMAXAREACAR 0.927448 LAYER METAL2 ;
      ANTENNAMAXCUTCAR 0.131313 LAYER VIA12 ;
    PORT
      LAYER POLY1 ;
        RECT 1.615 1.695 3.495 2.115 ;
        RECT 3.195 1.695 3.375 3.83 ;
        RECT 2.475 1.695 2.655 3.83 ;
        RECT 2.335 0.83 2.515 2.115 ;
        RECT 1.755 1.695 1.935 3.83 ;
        RECT 1.615 0.83 1.795 2.115 ;
      LAYER METAL1 ;
        RECT 1.655 1.735 2.95 2.075 ;
        RECT 1.605 1.68 1.985 2.06 ;
      LAYER METAL2 ;
        RECT 1.6 1.68 2.05 2.13 ;
      LAYER CONT ;
        RECT 1.715 1.795 1.935 2.015 ;
        RECT 2.67 1.795 2.89 2.015 ;
      LAYER VIA12 ;
        RECT 1.665 1.74 1.925 2 ;
    END
  END A
  PIN Y
    DIRECTION INOUT ;
    USE SIGNAL ;
    ANTENNAPARTIALCUTAREA 0.2028 LAYER VIA12 ;
    ANTENNADIFFAREA 0.8844 LAYER METAL2 ;
    ANTENNADIFFAREA 0.8844 LAYER METAL1 ;
    PORT
      LAYER DIFF ;
        RECT 5.75 1.05 6.23 1.49 ;
        RECT 5.535 2.95 6.015 3.61 ;
        RECT 4.095 2.95 4.635 3.61 ;
      LAYER METAL1 ;
        RECT 5.69 2.77 6.395 3.025 ;
        RECT 5.93 1.605 6.395 3.025 ;
        RECT 5.93 1.09 6.16 3.025 ;
        RECT 5.905 1.09 6.16 1.45 ;
        RECT 5.69 2.77 5.92 3.57 ;
        RECT 4.25 2.77 6.395 3 ;
        RECT 4.25 2.77 4.48 3.57 ;
      LAYER METAL2 ;
        RECT 6.015 1.605 6.395 3.025 ;
      LAYER CONT ;
        RECT 4.255 3.17 4.475 3.39 ;
        RECT 5.695 3.17 5.915 3.39 ;
        RECT 5.91 1.16 6.13 1.38 ;
      LAYER VIA12 ;
        RECT 6.075 2.705 6.335 2.965 ;
        RECT 6.075 2.185 6.335 2.445 ;
        RECT 6.075 1.665 6.335 1.925 ;
    END
  END Y
  PIN VDD
    DIRECTION INOUT ;
    USE POWER ;
    PORT
      LAYER METAL1 ;
        RECT -0.57 4.04 7.14 4.74 ;
        RECT 3.53 3.23 3.76 4.74 ;
        RECT 2.09 3.23 2.32 4.74 ;
        RECT 0.65 3.23 0.88 4.74 ;
    END
  END VDD
  PIN B
    DIRECTION INOUT ;
    USE SIGNAL ;
    ANTENNAPARTIALMETALAREA 0.6491 LAYER METAL2 ;
    ANTENNAPARTIALCUTAREA 0.1352 LAYER VIA12 ;
    ANTENNAMODEL OXIDE1 ;
      ANTENNAGATEAREA 0.5148 LAYER METAL2 ;
      ANTENNAGATEAREA 0.198 LAYER METAL1 ;
      ANTENNAMAXAREACAR 5.73108 LAYER METAL2 ;
      ANTENNAMAXCUTCAR 0.682828 LAYER VIA12 ;
    PORT
      LAYER POLY1 ;
        RECT 4.535 2.365 5.685 2.76 ;
        RECT 5.355 2.365 5.535 3.83 ;
        RECT 4.535 1.59 4.955 2.76 ;
        RECT 4.635 1.59 4.815 3.83 ;
        RECT 3.93 1.59 4.955 1.77 ;
        RECT 3.93 0.83 4.11 1.77 ;
        RECT 0.885 2.105 1.365 2.525 ;
        RECT 1.185 0.83 1.365 2.525 ;
        RECT 1.035 2.105 1.215 3.83 ;
      LAYER METAL1 ;
        RECT 4.52 1.68 4.97 2.13 ;
        RECT 3.18 1.68 3.56 2.06 ;
        RECT 0.87 2.31 3.41 2.54 ;
        RECT 3.18 1.68 3.41 2.54 ;
        RECT 0.87 2.09 1.32 2.54 ;
      LAYER METAL2 ;
        RECT 4.555 1.59 4.935 2.095 ;
        RECT 3.18 1.59 4.935 1.87 ;
        RECT 3.18 1.59 3.56 2.06 ;
        RECT 0.87 2.09 1.32 2.54 ;
      LAYER CONT ;
        RECT 0.985 2.205 1.205 2.425 ;
        RECT 4.635 1.795 4.855 2.015 ;
      LAYER VIA12 ;
        RECT 0.965 2.185 1.225 2.445 ;
        RECT 3.24 1.74 3.5 2 ;
        RECT 4.615 1.775 4.875 2.035 ;
    END
  END B
  OBS
    LAYER METAL1 ;
      RECT 4.265 1.22 5.415 1.45 ;
      RECT 5.185 1.09 5.415 1.45 ;
      RECT 4.265 0.93 4.645 1.45 ;
      RECT 1.37 2.77 1.6 3.57 ;
      RECT 0.41 2.77 4.02 3 ;
      RECT 3.64 2.34 4.02 3 ;
      RECT 0.41 1.63 0.64 3 ;
      RECT 3.79 2.2 4.185 2.54 ;
      RECT 0.41 1.63 1.03 1.86 ;
      RECT 0.8 1.09 1.03 1.86 ;
      RECT 5.25 1.68 5.7 2.13 ;
      RECT 4.895 3.23 5.275 3.81 ;
      RECT 2.67 0.93 3.175 1.45 ;
      RECT 2.735 3.23 3.115 3.81 ;
    LAYER VIA12 ;
      RECT 5.345 1.775 5.605 2.035 ;
      RECT 4.955 3.49 5.215 3.75 ;
      RECT 4.325 0.99 4.585 1.25 ;
      RECT 3.7 2.4 3.96 2.66 ;
      RECT 2.795 3.49 3.055 3.75 ;
      RECT 2.73 0.99 2.99 1.25 ;
    LAYER METAL2 ;
      RECT 3.64 2.34 4.02 2.72 ;
      RECT 3.64 2.375 5.565 2.655 ;
      RECT 5.285 1.715 5.565 2.655 ;
      RECT 5.285 1.715 5.665 2.095 ;
      RECT 2.735 3.43 5.275 3.81 ;
      RECT 2.67 0.93 4.645 1.31 ;
  END
END xnor2_1

MACRO xor2_1
  CLASS CORE ;
  ORIGIN 0 -0.35 ;
  FOREIGN xor2_1 0 0.35 ;
  SIZE 10.22 BY 4.04 ;
  SYMMETRY X Y ;
  SITE core ;
  PIN VDD
    DIRECTION INOUT ;
    USE POWER ;
    PORT
      LAYER METAL1 ;
        RECT -0.57 4.04 10.79 4.74 ;
        RECT 4.99 3.09 5.22 4.74 ;
        RECT 3.55 3.09 3.78 4.74 ;
        RECT 2.11 3.09 2.34 4.74 ;
        RECT 0.67 3.09 0.9 4.74 ;
    END
  END VDD
  PIN X
    DIRECTION INOUT ;
    USE SIGNAL ;
    ANTENNAPARTIALCUTAREA 0.1352 LAYER VIA12 ;
    ANTENNADIFFAREA 0.766 LAYER METAL2 ;
    ANTENNADIFFAREA 0.766 LAYER METAL1 ;
    PORT
      LAYER DIFF ;
        RECT 8.415 1.04 8.935 1.26 ;
        RECT 8.415 0.94 8.835 1.36 ;
        RECT 8.395 3.05 8.935 3.71 ;
        RECT 6.975 1.04 7.455 1.48 ;
      LAYER METAL1 ;
        RECT 8.55 0.93 8.78 3.67 ;
        RECT 8.17 1.745 8.78 2.645 ;
        RECT 8.51 0.93 8.78 1.32 ;
        RECT 7.13 0.93 8.78 1.16 ;
        RECT 7.13 0.93 7.36 1.44 ;
      LAYER METAL2 ;
        RECT 8.17 1.745 8.62 2.645 ;
      LAYER CONT ;
        RECT 7.135 1.15 7.355 1.37 ;
        RECT 8.515 1.04 8.735 1.26 ;
        RECT 8.555 3.27 8.775 3.49 ;
      LAYER VIA12 ;
        RECT 8.23 2.325 8.49 2.585 ;
        RECT 8.23 1.805 8.49 2.065 ;
    END
  END X
  PIN VSS
    DIRECTION INOUT ;
    USE GROUND ;
    PORT
      LAYER METAL1 ;
        RECT -0.57 0 10.79 0.7 ;
        RECT 9.31 0 9.54 1.32 ;
        RECT 4.27 0 4.5 1.44 ;
        RECT 2.93 0 3.16 1.32 ;
        RECT 0.63 0 0.86 1.32 ;
    END
  END VSS
  PIN B
    DIRECTION INOUT ;
    USE SIGNAL ;
    ANTENNAPARTIALMETALAREA 0.37105 LAYER METAL2 ;
    ANTENNAPARTIALCUTAREA 0.2704 LAYER VIA12 ;
    ANTENNAMODEL OXIDE1 ;
      ANTENNAGATEAREA 0.594 LAYER METAL2 ;
      ANTENNAGATEAREA 0.594 LAYER METAL1 ;
      ANTENNAMAXAREACAR 3.966498 LAYER METAL2 ;
      ANTENNAMAXCUTCAR 0.455219 LAYER VIA12 ;
    PORT
      LAYER POLY1 ;
        RECT 6.195 1.685 7.085 2.105 ;
        RECT 6.795 0.82 6.975 3.93 ;
        RECT 6.075 1.7 6.975 2.95 ;
        RECT 6.075 1.7 6.255 3.93 ;
        RECT 1.775 1.48 1.955 3.93 ;
        RECT 1.055 1.48 1.955 2.95 ;
        RECT 1.055 0.82 1.235 3.93 ;
        RECT 0.885 1.71 1.955 2.6 ;
      LAYER METAL1 ;
        RECT 6.155 1.67 7.125 2.12 ;
        RECT 0.87 1.67 7.125 1.9 ;
        RECT 0.87 1.67 1.32 2.64 ;
      LAYER METAL2 ;
        RECT 6.19 1.705 7.09 2.085 ;
        RECT 0.87 1.705 1.32 2.12 ;
        RECT 0.905 1.705 1.285 2.605 ;
      LAYER CONT ;
        RECT 0.985 2.28 1.205 2.5 ;
        RECT 0.985 1.81 1.205 2.03 ;
        RECT 6.295 1.785 6.515 2.005 ;
        RECT 6.765 1.785 6.985 2.005 ;
      LAYER VIA12 ;
        RECT 0.965 2.285 1.225 2.545 ;
        RECT 0.965 1.765 1.225 2.025 ;
        RECT 6.25 1.765 6.51 2.025 ;
        RECT 6.77 1.765 7.03 2.025 ;
    END
  END B
  PIN A
    DIRECTION INOUT ;
    USE SIGNAL ;
    ANTENNAPARTIALCUTAREA 0.0676 LAYER VIA12 ;
    ANTENNAMODEL OXIDE1 ;
      ANTENNAGATEAREA 0.594 LAYER METAL2 ;
      ANTENNAGATEAREA 0.594 LAYER METAL1 ;
      ANTENNAMAXAREACAR 0.340909 LAYER METAL2 ;
      ANTENNAMAXCUTCAR 0.113805 LAYER VIA12 ;
    PORT
      LAYER POLY1 ;
        RECT 4.655 0.82 4.835 3.93 ;
        RECT 2.495 1.7 4.835 2.95 ;
        RECT 3.935 1.7 4.115 3.93 ;
        RECT 3.215 1.7 3.395 3.93 ;
        RECT 2.495 1.48 2.765 2.95 ;
        RECT 2.555 0.82 2.735 2.95 ;
        RECT 2.495 1.48 2.675 3.93 ;
        RECT 2.345 2.145 4.835 2.565 ;
      LAYER METAL1 ;
        RECT 2.33 2.13 2.78 2.58 ;
      LAYER METAL2 ;
        RECT 2.33 1.9 2.78 2.83 ;
      LAYER CONT ;
        RECT 2.445 2.245 2.665 2.465 ;
      LAYER VIA12 ;
        RECT 2.425 2.225 2.685 2.485 ;
    END
  END A
  OBS
    LAYER METAL1 ;
      RECT 9.12 3.09 9.5 3.71 ;
      RECT 9.115 3.09 9.655 3.67 ;
      RECT 7.83 3.09 8.21 3.71 ;
      RECT 7.675 3.09 8.215 3.67 ;
      RECT 7.13 2.35 7.36 3.67 ;
      RECT 5.69 2.35 5.92 3.67 ;
      RECT 4.27 2.35 4.5 3.67 ;
      RECT 4.27 2.35 7.36 2.58 ;
      RECT 6.255 3.09 6.795 3.67 ;
      RECT 6.335 2.81 6.715 3.67 ;
      RECT 6.41 0.93 6.64 1.44 ;
      RECT 4.99 0.93 5.22 1.44 ;
      RECT 4.99 0.93 6.64 1.16 ;
      RECT 2.68 3.09 3.06 3.71 ;
      RECT 2.675 3.09 3.215 3.67 ;
      RECT 1.39 3.09 1.77 3.71 ;
      RECT 1.235 3.09 1.775 3.67 ;
      RECT 7.475 1.67 7.925 2.12 ;
      RECT 1.43 0.93 2.36 1.32 ;
    LAYER VIA12 ;
      RECT 9.18 3.39 9.44 3.65 ;
      RECT 7.89 3.39 8.15 3.65 ;
      RECT 7.57 1.765 7.83 2.025 ;
      RECT 6.395 2.87 6.655 3.13 ;
      RECT 2.74 3.39 3 3.65 ;
      RECT 1.765 0.995 2.025 1.255 ;
      RECT 1.45 3.39 1.71 3.65 ;
    LAYER METAL2 ;
      RECT 1.39 3.47 9.5 3.75 ;
      RECT 9.12 3.33 9.5 3.75 ;
      RECT 7.83 3.33 8.21 3.75 ;
      RECT 2.68 3.33 3.06 3.75 ;
      RECT 1.39 3.33 1.77 3.75 ;
      RECT 6.335 2.365 6.715 3.19 ;
      RECT 6.335 2.365 7.89 2.645 ;
      RECT 7.51 0.935 7.89 2.645 ;
      RECT 7.505 2.085 7.89 2.645 ;
      RECT 1.705 0.935 2.085 1.315 ;
      RECT 1.705 0.935 7.89 1.215 ;
  END
END xor2_1

END LIBRARY
